# Generated by FakeRAM 2.0
VERSION 5.7 ;
BUSBITCHARS "[]" ;
PROPERTYDEFINITIONS
  MACRO width INTEGER ;
  MACRO depth INTEGER ;
  MACRO banks INTEGER ;
END PROPERTYDEFINITIONS
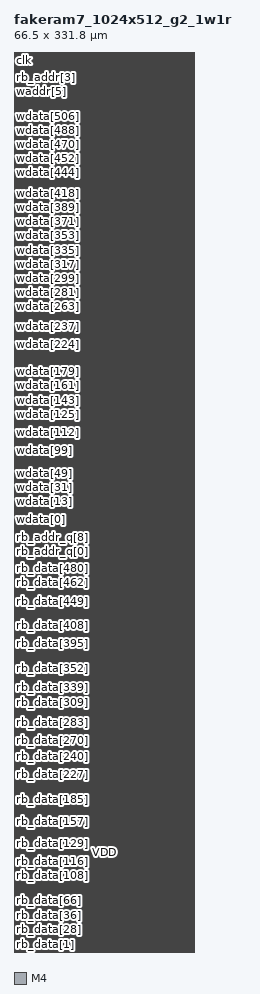
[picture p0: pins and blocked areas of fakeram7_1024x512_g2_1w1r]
MACRO fakeram7_1024x512_g2_1w1r
  PROPERTY width 512 ;
  PROPERTY depth 1024 ;
  PROPERTY banks 1 ;
  FOREIGN fakeram7_1024x512_g2_1w1r 0 0 ;
  SYMMETRY X Y R90 ;
  SIZE 66.5000 BY 331.8000 ;
  CLASS BLOCK ;
  PIN wdata[0]
    DIRECTION INPUT ;
    USE SIGNAL ;
    PORT
      LAYER M4 ;
      RECT 0.00000 159.36000 0.02400 159.38400 ;
    END
  END wdata[0]
  PIN wdata[1]
    DIRECTION INPUT ;
    USE SIGNAL ;
    PORT
      LAYER M4 ;
      RECT 0.00000 159.64800 0.02400 159.67200 ;
    END
  END wdata[1]
  PIN wdata[2]
    DIRECTION INPUT ;
    USE SIGNAL ;
    PORT
      LAYER M4 ;
      RECT 0.00000 159.93600 0.02400 159.96000 ;
    END
  END wdata[2]
  PIN wdata[3]
    DIRECTION INPUT ;
    USE SIGNAL ;
    PORT
      LAYER M4 ;
      RECT 0.00000 160.22400 0.02400 160.24800 ;
    END
  END wdata[3]
  PIN wdata[4]
    DIRECTION INPUT ;
    USE SIGNAL ;
    PORT
      LAYER M4 ;
      RECT 0.00000 160.51200 0.02400 160.53600 ;
    END
  END wdata[4]
  PIN wdata[5]
    DIRECTION INPUT ;
    USE SIGNAL ;
    PORT
      LAYER M4 ;
      RECT 0.00000 160.80000 0.02400 160.82400 ;
    END
  END wdata[5]
  PIN wdata[6]
    DIRECTION INPUT ;
    USE SIGNAL ;
    PORT
      LAYER M4 ;
      RECT 0.00000 161.08800 0.02400 161.11200 ;
    END
  END wdata[6]
  PIN wdata[7]
    DIRECTION INPUT ;
    USE SIGNAL ;
    PORT
      LAYER M4 ;
      RECT 0.00000 161.37600 0.02400 161.40000 ;
    END
  END wdata[7]
  PIN wdata[8]
    DIRECTION INPUT ;
    USE SIGNAL ;
    PORT
      LAYER M4 ;
      RECT 0.00000 161.66400 0.02400 161.68800 ;
    END
  END wdata[8]
  PIN wdata[9]
    DIRECTION INPUT ;
    USE SIGNAL ;
    PORT
      LAYER M4 ;
      RECT 0.00000 161.95200 0.02400 161.97600 ;
    END
  END wdata[9]
  PIN wdata[10]
    DIRECTION INPUT ;
    USE SIGNAL ;
    PORT
      LAYER M4 ;
      RECT 0.00000 162.24000 0.02400 162.26400 ;
    END
  END wdata[10]
  PIN wdata[11]
    DIRECTION INPUT ;
    USE SIGNAL ;
    PORT
      LAYER M4 ;
      RECT 0.00000 162.52800 0.02400 162.55200 ;
    END
  END wdata[11]
  PIN wdata[12]
    DIRECTION INPUT ;
    USE SIGNAL ;
    PORT
      LAYER M4 ;
      RECT 0.00000 162.81600 0.02400 162.84000 ;
    END
  END wdata[12]
  PIN wdata[13]
    DIRECTION INPUT ;
    USE SIGNAL ;
    PORT
      LAYER M4 ;
      RECT 0.00000 163.10400 0.02400 163.12800 ;
    END
  END wdata[13]
  PIN wdata[14]
    DIRECTION INPUT ;
    USE SIGNAL ;
    PORT
      LAYER M4 ;
      RECT 0.00000 163.39200 0.02400 163.41600 ;
    END
  END wdata[14]
  PIN wdata[15]
    DIRECTION INPUT ;
    USE SIGNAL ;
    PORT
      LAYER M4 ;
      RECT 0.00000 163.68000 0.02400 163.70400 ;
    END
  END wdata[15]
  PIN wdata[16]
    DIRECTION INPUT ;
    USE SIGNAL ;
    PORT
      LAYER M4 ;
      RECT 0.00000 163.96800 0.02400 163.99200 ;
    END
  END wdata[16]
  PIN wdata[17]
    DIRECTION INPUT ;
    USE SIGNAL ;
    PORT
      LAYER M4 ;
      RECT 0.00000 164.25600 0.02400 164.28000 ;
    END
  END wdata[17]
  PIN wdata[18]
    DIRECTION INPUT ;
    USE SIGNAL ;
    PORT
      LAYER M4 ;
      RECT 0.00000 164.54400 0.02400 164.56800 ;
    END
  END wdata[18]
  PIN wdata[19]
    DIRECTION INPUT ;
    USE SIGNAL ;
    PORT
      LAYER M4 ;
      RECT 0.00000 164.83200 0.02400 164.85600 ;
    END
  END wdata[19]
  PIN wdata[20]
    DIRECTION INPUT ;
    USE SIGNAL ;
    PORT
      LAYER M4 ;
      RECT 0.00000 165.12000 0.02400 165.14400 ;
    END
  END wdata[20]
  PIN wdata[21]
    DIRECTION INPUT ;
    USE SIGNAL ;
    PORT
      LAYER M4 ;
      RECT 0.00000 165.40800 0.02400 165.43200 ;
    END
  END wdata[21]
  PIN wdata[22]
    DIRECTION INPUT ;
    USE SIGNAL ;
    PORT
      LAYER M4 ;
      RECT 0.00000 165.69600 0.02400 165.72000 ;
    END
  END wdata[22]
  PIN wdata[23]
    DIRECTION INPUT ;
    USE SIGNAL ;
    PORT
      LAYER M4 ;
      RECT 0.00000 165.98400 0.02400 166.00800 ;
    END
  END wdata[23]
  PIN wdata[24]
    DIRECTION INPUT ;
    USE SIGNAL ;
    PORT
      LAYER M4 ;
      RECT 0.00000 166.27200 0.02400 166.29600 ;
    END
  END wdata[24]
  PIN wdata[25]
    DIRECTION INPUT ;
    USE SIGNAL ;
    PORT
      LAYER M4 ;
      RECT 0.00000 166.56000 0.02400 166.58400 ;
    END
  END wdata[25]
  PIN wdata[26]
    DIRECTION INPUT ;
    USE SIGNAL ;
    PORT
      LAYER M4 ;
      RECT 0.00000 166.84800 0.02400 166.87200 ;
    END
  END wdata[26]
  PIN wdata[27]
    DIRECTION INPUT ;
    USE SIGNAL ;
    PORT
      LAYER M4 ;
      RECT 0.00000 167.13600 0.02400 167.16000 ;
    END
  END wdata[27]
  PIN wdata[28]
    DIRECTION INPUT ;
    USE SIGNAL ;
    PORT
      LAYER M4 ;
      RECT 0.00000 167.42400 0.02400 167.44800 ;
    END
  END wdata[28]
  PIN wdata[29]
    DIRECTION INPUT ;
    USE SIGNAL ;
    PORT
      LAYER M4 ;
      RECT 0.00000 167.71200 0.02400 167.73600 ;
    END
  END wdata[29]
  PIN wdata[30]
    DIRECTION INPUT ;
    USE SIGNAL ;
    PORT
      LAYER M4 ;
      RECT 0.00000 168.00000 0.02400 168.02400 ;
    END
  END wdata[30]
  PIN wdata[31]
    DIRECTION INPUT ;
    USE SIGNAL ;
    PORT
      LAYER M4 ;
      RECT 0.00000 168.28800 0.02400 168.31200 ;
    END
  END wdata[31]
  PIN wdata[32]
    DIRECTION INPUT ;
    USE SIGNAL ;
    PORT
      LAYER M4 ;
      RECT 0.00000 168.57600 0.02400 168.60000 ;
    END
  END wdata[32]
  PIN wdata[33]
    DIRECTION INPUT ;
    USE SIGNAL ;
    PORT
      LAYER M4 ;
      RECT 0.00000 168.86400 0.02400 168.88800 ;
    END
  END wdata[33]
  PIN wdata[34]
    DIRECTION INPUT ;
    USE SIGNAL ;
    PORT
      LAYER M4 ;
      RECT 0.00000 169.15200 0.02400 169.17600 ;
    END
  END wdata[34]
  PIN wdata[35]
    DIRECTION INPUT ;
    USE SIGNAL ;
    PORT
      LAYER M4 ;
      RECT 0.00000 169.44000 0.02400 169.46400 ;
    END
  END wdata[35]
  PIN wdata[36]
    DIRECTION INPUT ;
    USE SIGNAL ;
    PORT
      LAYER M4 ;
      RECT 0.00000 169.72800 0.02400 169.75200 ;
    END
  END wdata[36]
  PIN wdata[37]
    DIRECTION INPUT ;
    USE SIGNAL ;
    PORT
      LAYER M4 ;
      RECT 0.00000 170.01600 0.02400 170.04000 ;
    END
  END wdata[37]
  PIN wdata[38]
    DIRECTION INPUT ;
    USE SIGNAL ;
    PORT
      LAYER M4 ;
      RECT 0.00000 170.30400 0.02400 170.32800 ;
    END
  END wdata[38]
  PIN wdata[39]
    DIRECTION INPUT ;
    USE SIGNAL ;
    PORT
      LAYER M4 ;
      RECT 0.00000 170.59200 0.02400 170.61600 ;
    END
  END wdata[39]
  PIN wdata[40]
    DIRECTION INPUT ;
    USE SIGNAL ;
    PORT
      LAYER M4 ;
      RECT 0.00000 170.88000 0.02400 170.90400 ;
    END
  END wdata[40]
  PIN wdata[41]
    DIRECTION INPUT ;
    USE SIGNAL ;
    PORT
      LAYER M4 ;
      RECT 0.00000 171.16800 0.02400 171.19200 ;
    END
  END wdata[41]
  PIN wdata[42]
    DIRECTION INPUT ;
    USE SIGNAL ;
    PORT
      LAYER M4 ;
      RECT 0.00000 171.45600 0.02400 171.48000 ;
    END
  END wdata[42]
  PIN wdata[43]
    DIRECTION INPUT ;
    USE SIGNAL ;
    PORT
      LAYER M4 ;
      RECT 0.00000 171.74400 0.02400 171.76800 ;
    END
  END wdata[43]
  PIN wdata[44]
    DIRECTION INPUT ;
    USE SIGNAL ;
    PORT
      LAYER M4 ;
      RECT 0.00000 172.03200 0.02400 172.05600 ;
    END
  END wdata[44]
  PIN wdata[45]
    DIRECTION INPUT ;
    USE SIGNAL ;
    PORT
      LAYER M4 ;
      RECT 0.00000 172.32000 0.02400 172.34400 ;
    END
  END wdata[45]
  PIN wdata[46]
    DIRECTION INPUT ;
    USE SIGNAL ;
    PORT
      LAYER M4 ;
      RECT 0.00000 172.60800 0.02400 172.63200 ;
    END
  END wdata[46]
  PIN wdata[47]
    DIRECTION INPUT ;
    USE SIGNAL ;
    PORT
      LAYER M4 ;
      RECT 0.00000 172.89600 0.02400 172.92000 ;
    END
  END wdata[47]
  PIN wdata[48]
    DIRECTION INPUT ;
    USE SIGNAL ;
    PORT
      LAYER M4 ;
      RECT 0.00000 173.18400 0.02400 173.20800 ;
    END
  END wdata[48]
  PIN wdata[49]
    DIRECTION INPUT ;
    USE SIGNAL ;
    PORT
      LAYER M4 ;
      RECT 0.00000 173.47200 0.02400 173.49600 ;
    END
  END wdata[49]
  PIN wdata[50]
    DIRECTION INPUT ;
    USE SIGNAL ;
    PORT
      LAYER M4 ;
      RECT 0.00000 173.76000 0.02400 173.78400 ;
    END
  END wdata[50]
  PIN wdata[51]
    DIRECTION INPUT ;
    USE SIGNAL ;
    PORT
      LAYER M4 ;
      RECT 0.00000 174.04800 0.02400 174.07200 ;
    END
  END wdata[51]
  PIN wdata[52]
    DIRECTION INPUT ;
    USE SIGNAL ;
    PORT
      LAYER M4 ;
      RECT 0.00000 174.33600 0.02400 174.36000 ;
    END
  END wdata[52]
  PIN wdata[53]
    DIRECTION INPUT ;
    USE SIGNAL ;
    PORT
      LAYER M4 ;
      RECT 0.00000 174.62400 0.02400 174.64800 ;
    END
  END wdata[53]
  PIN wdata[54]
    DIRECTION INPUT ;
    USE SIGNAL ;
    PORT
      LAYER M4 ;
      RECT 0.00000 174.91200 0.02400 174.93600 ;
    END
  END wdata[54]
  PIN wdata[55]
    DIRECTION INPUT ;
    USE SIGNAL ;
    PORT
      LAYER M4 ;
      RECT 0.00000 175.20000 0.02400 175.22400 ;
    END
  END wdata[55]
  PIN wdata[56]
    DIRECTION INPUT ;
    USE SIGNAL ;
    PORT
      LAYER M4 ;
      RECT 0.00000 175.48800 0.02400 175.51200 ;
    END
  END wdata[56]
  PIN wdata[57]
    DIRECTION INPUT ;
    USE SIGNAL ;
    PORT
      LAYER M4 ;
      RECT 0.00000 175.77600 0.02400 175.80000 ;
    END
  END wdata[57]
  PIN wdata[58]
    DIRECTION INPUT ;
    USE SIGNAL ;
    PORT
      LAYER M4 ;
      RECT 0.00000 176.06400 0.02400 176.08800 ;
    END
  END wdata[58]
  PIN wdata[59]
    DIRECTION INPUT ;
    USE SIGNAL ;
    PORT
      LAYER M4 ;
      RECT 0.00000 176.35200 0.02400 176.37600 ;
    END
  END wdata[59]
  PIN wdata[60]
    DIRECTION INPUT ;
    USE SIGNAL ;
    PORT
      LAYER M4 ;
      RECT 0.00000 176.64000 0.02400 176.66400 ;
    END
  END wdata[60]
  PIN wdata[61]
    DIRECTION INPUT ;
    USE SIGNAL ;
    PORT
      LAYER M4 ;
      RECT 0.00000 176.92800 0.02400 176.95200 ;
    END
  END wdata[61]
  PIN wdata[62]
    DIRECTION INPUT ;
    USE SIGNAL ;
    PORT
      LAYER M4 ;
      RECT 0.00000 177.21600 0.02400 177.24000 ;
    END
  END wdata[62]
  PIN wdata[63]
    DIRECTION INPUT ;
    USE SIGNAL ;
    PORT
      LAYER M4 ;
      RECT 0.00000 177.50400 0.02400 177.52800 ;
    END
  END wdata[63]
  PIN wdata[64]
    DIRECTION INPUT ;
    USE SIGNAL ;
    PORT
      LAYER M4 ;
      RECT 0.00000 177.79200 0.02400 177.81600 ;
    END
  END wdata[64]
  PIN wdata[65]
    DIRECTION INPUT ;
    USE SIGNAL ;
    PORT
      LAYER M4 ;
      RECT 0.00000 178.08000 0.02400 178.10400 ;
    END
  END wdata[65]
  PIN wdata[66]
    DIRECTION INPUT ;
    USE SIGNAL ;
    PORT
      LAYER M4 ;
      RECT 0.00000 178.36800 0.02400 178.39200 ;
    END
  END wdata[66]
  PIN wdata[67]
    DIRECTION INPUT ;
    USE SIGNAL ;
    PORT
      LAYER M4 ;
      RECT 0.00000 178.65600 0.02400 178.68000 ;
    END
  END wdata[67]
  PIN wdata[68]
    DIRECTION INPUT ;
    USE SIGNAL ;
    PORT
      LAYER M4 ;
      RECT 0.00000 178.94400 0.02400 178.96800 ;
    END
  END wdata[68]
  PIN wdata[69]
    DIRECTION INPUT ;
    USE SIGNAL ;
    PORT
      LAYER M4 ;
      RECT 0.00000 179.23200 0.02400 179.25600 ;
    END
  END wdata[69]
  PIN wdata[70]
    DIRECTION INPUT ;
    USE SIGNAL ;
    PORT
      LAYER M4 ;
      RECT 0.00000 179.52000 0.02400 179.54400 ;
    END
  END wdata[70]
  PIN wdata[71]
    DIRECTION INPUT ;
    USE SIGNAL ;
    PORT
      LAYER M4 ;
      RECT 0.00000 179.80800 0.02400 179.83200 ;
    END
  END wdata[71]
  PIN wdata[72]
    DIRECTION INPUT ;
    USE SIGNAL ;
    PORT
      LAYER M4 ;
      RECT 0.00000 180.09600 0.02400 180.12000 ;
    END
  END wdata[72]
  PIN wdata[73]
    DIRECTION INPUT ;
    USE SIGNAL ;
    PORT
      LAYER M4 ;
      RECT 0.00000 180.38400 0.02400 180.40800 ;
    END
  END wdata[73]
  PIN wdata[74]
    DIRECTION INPUT ;
    USE SIGNAL ;
    PORT
      LAYER M4 ;
      RECT 0.00000 180.67200 0.02400 180.69600 ;
    END
  END wdata[74]
  PIN wdata[75]
    DIRECTION INPUT ;
    USE SIGNAL ;
    PORT
      LAYER M4 ;
      RECT 0.00000 180.96000 0.02400 180.98400 ;
    END
  END wdata[75]
  PIN wdata[76]
    DIRECTION INPUT ;
    USE SIGNAL ;
    PORT
      LAYER M4 ;
      RECT 0.00000 181.24800 0.02400 181.27200 ;
    END
  END wdata[76]
  PIN wdata[77]
    DIRECTION INPUT ;
    USE SIGNAL ;
    PORT
      LAYER M4 ;
      RECT 0.00000 181.53600 0.02400 181.56000 ;
    END
  END wdata[77]
  PIN wdata[78]
    DIRECTION INPUT ;
    USE SIGNAL ;
    PORT
      LAYER M4 ;
      RECT 0.00000 181.82400 0.02400 181.84800 ;
    END
  END wdata[78]
  PIN wdata[79]
    DIRECTION INPUT ;
    USE SIGNAL ;
    PORT
      LAYER M4 ;
      RECT 0.00000 182.11200 0.02400 182.13600 ;
    END
  END wdata[79]
  PIN wdata[80]
    DIRECTION INPUT ;
    USE SIGNAL ;
    PORT
      LAYER M4 ;
      RECT 0.00000 182.40000 0.02400 182.42400 ;
    END
  END wdata[80]
  PIN wdata[81]
    DIRECTION INPUT ;
    USE SIGNAL ;
    PORT
      LAYER M4 ;
      RECT 0.00000 182.68800 0.02400 182.71200 ;
    END
  END wdata[81]
  PIN wdata[82]
    DIRECTION INPUT ;
    USE SIGNAL ;
    PORT
      LAYER M4 ;
      RECT 0.00000 182.97600 0.02400 183.00000 ;
    END
  END wdata[82]
  PIN wdata[83]
    DIRECTION INPUT ;
    USE SIGNAL ;
    PORT
      LAYER M4 ;
      RECT 0.00000 183.26400 0.02400 183.28800 ;
    END
  END wdata[83]
  PIN wdata[84]
    DIRECTION INPUT ;
    USE SIGNAL ;
    PORT
      LAYER M4 ;
      RECT 0.00000 183.55200 0.02400 183.57600 ;
    END
  END wdata[84]
  PIN wdata[85]
    DIRECTION INPUT ;
    USE SIGNAL ;
    PORT
      LAYER M4 ;
      RECT 0.00000 183.84000 0.02400 183.86400 ;
    END
  END wdata[85]
  PIN wdata[86]
    DIRECTION INPUT ;
    USE SIGNAL ;
    PORT
      LAYER M4 ;
      RECT 0.00000 184.12800 0.02400 184.15200 ;
    END
  END wdata[86]
  PIN wdata[87]
    DIRECTION INPUT ;
    USE SIGNAL ;
    PORT
      LAYER M4 ;
      RECT 0.00000 184.41600 0.02400 184.44000 ;
    END
  END wdata[87]
  PIN wdata[88]
    DIRECTION INPUT ;
    USE SIGNAL ;
    PORT
      LAYER M4 ;
      RECT 0.00000 184.70400 0.02400 184.72800 ;
    END
  END wdata[88]
  PIN wdata[89]
    DIRECTION INPUT ;
    USE SIGNAL ;
    PORT
      LAYER M4 ;
      RECT 0.00000 184.99200 0.02400 185.01600 ;
    END
  END wdata[89]
  PIN wdata[90]
    DIRECTION INPUT ;
    USE SIGNAL ;
    PORT
      LAYER M4 ;
      RECT 0.00000 185.28000 0.02400 185.30400 ;
    END
  END wdata[90]
  PIN wdata[91]
    DIRECTION INPUT ;
    USE SIGNAL ;
    PORT
      LAYER M4 ;
      RECT 0.00000 185.56800 0.02400 185.59200 ;
    END
  END wdata[91]
  PIN wdata[92]
    DIRECTION INPUT ;
    USE SIGNAL ;
    PORT
      LAYER M4 ;
      RECT 0.00000 185.85600 0.02400 185.88000 ;
    END
  END wdata[92]
  PIN wdata[93]
    DIRECTION INPUT ;
    USE SIGNAL ;
    PORT
      LAYER M4 ;
      RECT 0.00000 186.14400 0.02400 186.16800 ;
    END
  END wdata[93]
  PIN wdata[94]
    DIRECTION INPUT ;
    USE SIGNAL ;
    PORT
      LAYER M4 ;
      RECT 0.00000 186.43200 0.02400 186.45600 ;
    END
  END wdata[94]
  PIN wdata[95]
    DIRECTION INPUT ;
    USE SIGNAL ;
    PORT
      LAYER M4 ;
      RECT 0.00000 186.72000 0.02400 186.74400 ;
    END
  END wdata[95]
  PIN wdata[96]
    DIRECTION INPUT ;
    USE SIGNAL ;
    PORT
      LAYER M4 ;
      RECT 0.00000 187.00800 0.02400 187.03200 ;
    END
  END wdata[96]
  PIN wdata[97]
    DIRECTION INPUT ;
    USE SIGNAL ;
    PORT
      LAYER M4 ;
      RECT 0.00000 187.29600 0.02400 187.32000 ;
    END
  END wdata[97]
  PIN wdata[98]
    DIRECTION INPUT ;
    USE SIGNAL ;
    PORT
      LAYER M4 ;
      RECT 0.00000 187.58400 0.02400 187.60800 ;
    END
  END wdata[98]
  PIN wdata[99]
    DIRECTION INPUT ;
    USE SIGNAL ;
    PORT
      LAYER M4 ;
      RECT 0.00000 187.87200 0.02400 187.89600 ;
    END
  END wdata[99]
  PIN wdata[100]
    DIRECTION INPUT ;
    USE SIGNAL ;
    PORT
      LAYER M4 ;
      RECT 0.00000 188.16000 0.02400 188.18400 ;
    END
  END wdata[100]
  PIN wdata[101]
    DIRECTION INPUT ;
    USE SIGNAL ;
    PORT
      LAYER M4 ;
      RECT 0.00000 188.44800 0.02400 188.47200 ;
    END
  END wdata[101]
  PIN wdata[102]
    DIRECTION INPUT ;
    USE SIGNAL ;
    PORT
      LAYER M4 ;
      RECT 0.00000 188.73600 0.02400 188.76000 ;
    END
  END wdata[102]
  PIN wdata[103]
    DIRECTION INPUT ;
    USE SIGNAL ;
    PORT
      LAYER M4 ;
      RECT 0.00000 189.02400 0.02400 189.04800 ;
    END
  END wdata[103]
  PIN wdata[104]
    DIRECTION INPUT ;
    USE SIGNAL ;
    PORT
      LAYER M4 ;
      RECT 0.00000 189.31200 0.02400 189.33600 ;
    END
  END wdata[104]
  PIN wdata[105]
    DIRECTION INPUT ;
    USE SIGNAL ;
    PORT
      LAYER M4 ;
      RECT 0.00000 189.60000 0.02400 189.62400 ;
    END
  END wdata[105]
  PIN wdata[106]
    DIRECTION INPUT ;
    USE SIGNAL ;
    PORT
      LAYER M4 ;
      RECT 0.00000 189.88800 0.02400 189.91200 ;
    END
  END wdata[106]
  PIN wdata[107]
    DIRECTION INPUT ;
    USE SIGNAL ;
    PORT
      LAYER M4 ;
      RECT 0.00000 190.17600 0.02400 190.20000 ;
    END
  END wdata[107]
  PIN wdata[108]
    DIRECTION INPUT ;
    USE SIGNAL ;
    PORT
      LAYER M4 ;
      RECT 0.00000 190.46400 0.02400 190.48800 ;
    END
  END wdata[108]
  PIN wdata[109]
    DIRECTION INPUT ;
    USE SIGNAL ;
    PORT
      LAYER M4 ;
      RECT 0.00000 190.75200 0.02400 190.77600 ;
    END
  END wdata[109]
  PIN wdata[110]
    DIRECTION INPUT ;
    USE SIGNAL ;
    PORT
      LAYER M4 ;
      RECT 0.00000 191.04000 0.02400 191.06400 ;
    END
  END wdata[110]
  PIN wdata[111]
    DIRECTION INPUT ;
    USE SIGNAL ;
    PORT
      LAYER M4 ;
      RECT 0.00000 191.32800 0.02400 191.35200 ;
    END
  END wdata[111]
  PIN wdata[112]
    DIRECTION INPUT ;
    USE SIGNAL ;
    PORT
      LAYER M4 ;
      RECT 0.00000 191.61600 0.02400 191.64000 ;
    END
  END wdata[112]
  PIN wdata[113]
    DIRECTION INPUT ;
    USE SIGNAL ;
    PORT
      LAYER M4 ;
      RECT 0.00000 191.90400 0.02400 191.92800 ;
    END
  END wdata[113]
  PIN wdata[114]
    DIRECTION INPUT ;
    USE SIGNAL ;
    PORT
      LAYER M4 ;
      RECT 0.00000 192.19200 0.02400 192.21600 ;
    END
  END wdata[114]
  PIN wdata[115]
    DIRECTION INPUT ;
    USE SIGNAL ;
    PORT
      LAYER M4 ;
      RECT 0.00000 192.48000 0.02400 192.50400 ;
    END
  END wdata[115]
  PIN wdata[116]
    DIRECTION INPUT ;
    USE SIGNAL ;
    PORT
      LAYER M4 ;
      RECT 0.00000 192.76800 0.02400 192.79200 ;
    END
  END wdata[116]
  PIN wdata[117]
    DIRECTION INPUT ;
    USE SIGNAL ;
    PORT
      LAYER M4 ;
      RECT 0.00000 193.05600 0.02400 193.08000 ;
    END
  END wdata[117]
  PIN wdata[118]
    DIRECTION INPUT ;
    USE SIGNAL ;
    PORT
      LAYER M4 ;
      RECT 0.00000 193.34400 0.02400 193.36800 ;
    END
  END wdata[118]
  PIN wdata[119]
    DIRECTION INPUT ;
    USE SIGNAL ;
    PORT
      LAYER M4 ;
      RECT 0.00000 193.63200 0.02400 193.65600 ;
    END
  END wdata[119]
  PIN wdata[120]
    DIRECTION INPUT ;
    USE SIGNAL ;
    PORT
      LAYER M4 ;
      RECT 0.00000 193.92000 0.02400 193.94400 ;
    END
  END wdata[120]
  PIN wdata[121]
    DIRECTION INPUT ;
    USE SIGNAL ;
    PORT
      LAYER M4 ;
      RECT 0.00000 194.20800 0.02400 194.23200 ;
    END
  END wdata[121]
  PIN wdata[122]
    DIRECTION INPUT ;
    USE SIGNAL ;
    PORT
      LAYER M4 ;
      RECT 0.00000 194.49600 0.02400 194.52000 ;
    END
  END wdata[122]
  PIN wdata[123]
    DIRECTION INPUT ;
    USE SIGNAL ;
    PORT
      LAYER M4 ;
      RECT 0.00000 194.78400 0.02400 194.80800 ;
    END
  END wdata[123]
  PIN wdata[124]
    DIRECTION INPUT ;
    USE SIGNAL ;
    PORT
      LAYER M4 ;
      RECT 0.00000 195.07200 0.02400 195.09600 ;
    END
  END wdata[124]
  PIN wdata[125]
    DIRECTION INPUT ;
    USE SIGNAL ;
    PORT
      LAYER M4 ;
      RECT 0.00000 195.36000 0.02400 195.38400 ;
    END
  END wdata[125]
  PIN wdata[126]
    DIRECTION INPUT ;
    USE SIGNAL ;
    PORT
      LAYER M4 ;
      RECT 0.00000 195.64800 0.02400 195.67200 ;
    END
  END wdata[126]
  PIN wdata[127]
    DIRECTION INPUT ;
    USE SIGNAL ;
    PORT
      LAYER M4 ;
      RECT 0.00000 195.93600 0.02400 195.96000 ;
    END
  END wdata[127]
  PIN wdata[128]
    DIRECTION INPUT ;
    USE SIGNAL ;
    PORT
      LAYER M4 ;
      RECT 0.00000 196.22400 0.02400 196.24800 ;
    END
  END wdata[128]
  PIN wdata[129]
    DIRECTION INPUT ;
    USE SIGNAL ;
    PORT
      LAYER M4 ;
      RECT 0.00000 196.51200 0.02400 196.53600 ;
    END
  END wdata[129]
  PIN wdata[130]
    DIRECTION INPUT ;
    USE SIGNAL ;
    PORT
      LAYER M4 ;
      RECT 0.00000 196.80000 0.02400 196.82400 ;
    END
  END wdata[130]
  PIN wdata[131]
    DIRECTION INPUT ;
    USE SIGNAL ;
    PORT
      LAYER M4 ;
      RECT 0.00000 197.08800 0.02400 197.11200 ;
    END
  END wdata[131]
  PIN wdata[132]
    DIRECTION INPUT ;
    USE SIGNAL ;
    PORT
      LAYER M4 ;
      RECT 0.00000 197.37600 0.02400 197.40000 ;
    END
  END wdata[132]
  PIN wdata[133]
    DIRECTION INPUT ;
    USE SIGNAL ;
    PORT
      LAYER M4 ;
      RECT 0.00000 197.66400 0.02400 197.68800 ;
    END
  END wdata[133]
  PIN wdata[134]
    DIRECTION INPUT ;
    USE SIGNAL ;
    PORT
      LAYER M4 ;
      RECT 0.00000 197.95200 0.02400 197.97600 ;
    END
  END wdata[134]
  PIN wdata[135]
    DIRECTION INPUT ;
    USE SIGNAL ;
    PORT
      LAYER M4 ;
      RECT 0.00000 198.24000 0.02400 198.26400 ;
    END
  END wdata[135]
  PIN wdata[136]
    DIRECTION INPUT ;
    USE SIGNAL ;
    PORT
      LAYER M4 ;
      RECT 0.00000 198.52800 0.02400 198.55200 ;
    END
  END wdata[136]
  PIN wdata[137]
    DIRECTION INPUT ;
    USE SIGNAL ;
    PORT
      LAYER M4 ;
      RECT 0.00000 198.81600 0.02400 198.84000 ;
    END
  END wdata[137]
  PIN wdata[138]
    DIRECTION INPUT ;
    USE SIGNAL ;
    PORT
      LAYER M4 ;
      RECT 0.00000 199.10400 0.02400 199.12800 ;
    END
  END wdata[138]
  PIN wdata[139]
    DIRECTION INPUT ;
    USE SIGNAL ;
    PORT
      LAYER M4 ;
      RECT 0.00000 199.39200 0.02400 199.41600 ;
    END
  END wdata[139]
  PIN wdata[140]
    DIRECTION INPUT ;
    USE SIGNAL ;
    PORT
      LAYER M4 ;
      RECT 0.00000 199.68000 0.02400 199.70400 ;
    END
  END wdata[140]
  PIN wdata[141]
    DIRECTION INPUT ;
    USE SIGNAL ;
    PORT
      LAYER M4 ;
      RECT 0.00000 199.96800 0.02400 199.99200 ;
    END
  END wdata[141]
  PIN wdata[142]
    DIRECTION INPUT ;
    USE SIGNAL ;
    PORT
      LAYER M4 ;
      RECT 0.00000 200.25600 0.02400 200.28000 ;
    END
  END wdata[142]
  PIN wdata[143]
    DIRECTION INPUT ;
    USE SIGNAL ;
    PORT
      LAYER M4 ;
      RECT 0.00000 200.54400 0.02400 200.56800 ;
    END
  END wdata[143]
  PIN wdata[144]
    DIRECTION INPUT ;
    USE SIGNAL ;
    PORT
      LAYER M4 ;
      RECT 0.00000 200.83200 0.02400 200.85600 ;
    END
  END wdata[144]
  PIN wdata[145]
    DIRECTION INPUT ;
    USE SIGNAL ;
    PORT
      LAYER M4 ;
      RECT 0.00000 201.12000 0.02400 201.14400 ;
    END
  END wdata[145]
  PIN wdata[146]
    DIRECTION INPUT ;
    USE SIGNAL ;
    PORT
      LAYER M4 ;
      RECT 0.00000 201.40800 0.02400 201.43200 ;
    END
  END wdata[146]
  PIN wdata[147]
    DIRECTION INPUT ;
    USE SIGNAL ;
    PORT
      LAYER M4 ;
      RECT 0.00000 201.69600 0.02400 201.72000 ;
    END
  END wdata[147]
  PIN wdata[148]
    DIRECTION INPUT ;
    USE SIGNAL ;
    PORT
      LAYER M4 ;
      RECT 0.00000 201.98400 0.02400 202.00800 ;
    END
  END wdata[148]
  PIN wdata[149]
    DIRECTION INPUT ;
    USE SIGNAL ;
    PORT
      LAYER M4 ;
      RECT 0.00000 202.27200 0.02400 202.29600 ;
    END
  END wdata[149]
  PIN wdata[150]
    DIRECTION INPUT ;
    USE SIGNAL ;
    PORT
      LAYER M4 ;
      RECT 0.00000 202.56000 0.02400 202.58400 ;
    END
  END wdata[150]
  PIN wdata[151]
    DIRECTION INPUT ;
    USE SIGNAL ;
    PORT
      LAYER M4 ;
      RECT 0.00000 202.84800 0.02400 202.87200 ;
    END
  END wdata[151]
  PIN wdata[152]
    DIRECTION INPUT ;
    USE SIGNAL ;
    PORT
      LAYER M4 ;
      RECT 0.00000 203.13600 0.02400 203.16000 ;
    END
  END wdata[152]
  PIN wdata[153]
    DIRECTION INPUT ;
    USE SIGNAL ;
    PORT
      LAYER M4 ;
      RECT 0.00000 203.42400 0.02400 203.44800 ;
    END
  END wdata[153]
  PIN wdata[154]
    DIRECTION INPUT ;
    USE SIGNAL ;
    PORT
      LAYER M4 ;
      RECT 0.00000 203.71200 0.02400 203.73600 ;
    END
  END wdata[154]
  PIN wdata[155]
    DIRECTION INPUT ;
    USE SIGNAL ;
    PORT
      LAYER M4 ;
      RECT 0.00000 204.00000 0.02400 204.02400 ;
    END
  END wdata[155]
  PIN wdata[156]
    DIRECTION INPUT ;
    USE SIGNAL ;
    PORT
      LAYER M4 ;
      RECT 0.00000 204.28800 0.02400 204.31200 ;
    END
  END wdata[156]
  PIN wdata[157]
    DIRECTION INPUT ;
    USE SIGNAL ;
    PORT
      LAYER M4 ;
      RECT 0.00000 204.57600 0.02400 204.60000 ;
    END
  END wdata[157]
  PIN wdata[158]
    DIRECTION INPUT ;
    USE SIGNAL ;
    PORT
      LAYER M4 ;
      RECT 0.00000 204.86400 0.02400 204.88800 ;
    END
  END wdata[158]
  PIN wdata[159]
    DIRECTION INPUT ;
    USE SIGNAL ;
    PORT
      LAYER M4 ;
      RECT 0.00000 205.15200 0.02400 205.17600 ;
    END
  END wdata[159]
  PIN wdata[160]
    DIRECTION INPUT ;
    USE SIGNAL ;
    PORT
      LAYER M4 ;
      RECT 0.00000 205.44000 0.02400 205.46400 ;
    END
  END wdata[160]
  PIN wdata[161]
    DIRECTION INPUT ;
    USE SIGNAL ;
    PORT
      LAYER M4 ;
      RECT 0.00000 205.72800 0.02400 205.75200 ;
    END
  END wdata[161]
  PIN wdata[162]
    DIRECTION INPUT ;
    USE SIGNAL ;
    PORT
      LAYER M4 ;
      RECT 0.00000 206.01600 0.02400 206.04000 ;
    END
  END wdata[162]
  PIN wdata[163]
    DIRECTION INPUT ;
    USE SIGNAL ;
    PORT
      LAYER M4 ;
      RECT 0.00000 206.30400 0.02400 206.32800 ;
    END
  END wdata[163]
  PIN wdata[164]
    DIRECTION INPUT ;
    USE SIGNAL ;
    PORT
      LAYER M4 ;
      RECT 0.00000 206.59200 0.02400 206.61600 ;
    END
  END wdata[164]
  PIN wdata[165]
    DIRECTION INPUT ;
    USE SIGNAL ;
    PORT
      LAYER M4 ;
      RECT 0.00000 206.88000 0.02400 206.90400 ;
    END
  END wdata[165]
  PIN wdata[166]
    DIRECTION INPUT ;
    USE SIGNAL ;
    PORT
      LAYER M4 ;
      RECT 0.00000 207.16800 0.02400 207.19200 ;
    END
  END wdata[166]
  PIN wdata[167]
    DIRECTION INPUT ;
    USE SIGNAL ;
    PORT
      LAYER M4 ;
      RECT 0.00000 207.45600 0.02400 207.48000 ;
    END
  END wdata[167]
  PIN wdata[168]
    DIRECTION INPUT ;
    USE SIGNAL ;
    PORT
      LAYER M4 ;
      RECT 0.00000 207.74400 0.02400 207.76800 ;
    END
  END wdata[168]
  PIN wdata[169]
    DIRECTION INPUT ;
    USE SIGNAL ;
    PORT
      LAYER M4 ;
      RECT 0.00000 208.03200 0.02400 208.05600 ;
    END
  END wdata[169]
  PIN wdata[170]
    DIRECTION INPUT ;
    USE SIGNAL ;
    PORT
      LAYER M4 ;
      RECT 0.00000 208.32000 0.02400 208.34400 ;
    END
  END wdata[170]
  PIN wdata[171]
    DIRECTION INPUT ;
    USE SIGNAL ;
    PORT
      LAYER M4 ;
      RECT 0.00000 208.60800 0.02400 208.63200 ;
    END
  END wdata[171]
  PIN wdata[172]
    DIRECTION INPUT ;
    USE SIGNAL ;
    PORT
      LAYER M4 ;
      RECT 0.00000 208.89600 0.02400 208.92000 ;
    END
  END wdata[172]
  PIN wdata[173]
    DIRECTION INPUT ;
    USE SIGNAL ;
    PORT
      LAYER M4 ;
      RECT 0.00000 209.18400 0.02400 209.20800 ;
    END
  END wdata[173]
  PIN wdata[174]
    DIRECTION INPUT ;
    USE SIGNAL ;
    PORT
      LAYER M4 ;
      RECT 0.00000 209.47200 0.02400 209.49600 ;
    END
  END wdata[174]
  PIN wdata[175]
    DIRECTION INPUT ;
    USE SIGNAL ;
    PORT
      LAYER M4 ;
      RECT 0.00000 209.76000 0.02400 209.78400 ;
    END
  END wdata[175]
  PIN wdata[176]
    DIRECTION INPUT ;
    USE SIGNAL ;
    PORT
      LAYER M4 ;
      RECT 0.00000 210.04800 0.02400 210.07200 ;
    END
  END wdata[176]
  PIN wdata[177]
    DIRECTION INPUT ;
    USE SIGNAL ;
    PORT
      LAYER M4 ;
      RECT 0.00000 210.33600 0.02400 210.36000 ;
    END
  END wdata[177]
  PIN wdata[178]
    DIRECTION INPUT ;
    USE SIGNAL ;
    PORT
      LAYER M4 ;
      RECT 0.00000 210.62400 0.02400 210.64800 ;
    END
  END wdata[178]
  PIN wdata[179]
    DIRECTION INPUT ;
    USE SIGNAL ;
    PORT
      LAYER M4 ;
      RECT 0.00000 210.91200 0.02400 210.93600 ;
    END
  END wdata[179]
  PIN wdata[180]
    DIRECTION INPUT ;
    USE SIGNAL ;
    PORT
      LAYER M4 ;
      RECT 0.00000 211.20000 0.02400 211.22400 ;
    END
  END wdata[180]
  PIN wdata[181]
    DIRECTION INPUT ;
    USE SIGNAL ;
    PORT
      LAYER M4 ;
      RECT 0.00000 211.48800 0.02400 211.51200 ;
    END
  END wdata[181]
  PIN wdata[182]
    DIRECTION INPUT ;
    USE SIGNAL ;
    PORT
      LAYER M4 ;
      RECT 0.00000 211.77600 0.02400 211.80000 ;
    END
  END wdata[182]
  PIN wdata[183]
    DIRECTION INPUT ;
    USE SIGNAL ;
    PORT
      LAYER M4 ;
      RECT 0.00000 212.06400 0.02400 212.08800 ;
    END
  END wdata[183]
  PIN wdata[184]
    DIRECTION INPUT ;
    USE SIGNAL ;
    PORT
      LAYER M4 ;
      RECT 0.00000 212.35200 0.02400 212.37600 ;
    END
  END wdata[184]
  PIN wdata[185]
    DIRECTION INPUT ;
    USE SIGNAL ;
    PORT
      LAYER M4 ;
      RECT 0.00000 212.64000 0.02400 212.66400 ;
    END
  END wdata[185]
  PIN wdata[186]
    DIRECTION INPUT ;
    USE SIGNAL ;
    PORT
      LAYER M4 ;
      RECT 0.00000 212.92800 0.02400 212.95200 ;
    END
  END wdata[186]
  PIN wdata[187]
    DIRECTION INPUT ;
    USE SIGNAL ;
    PORT
      LAYER M4 ;
      RECT 0.00000 213.21600 0.02400 213.24000 ;
    END
  END wdata[187]
  PIN wdata[188]
    DIRECTION INPUT ;
    USE SIGNAL ;
    PORT
      LAYER M4 ;
      RECT 0.00000 213.50400 0.02400 213.52800 ;
    END
  END wdata[188]
  PIN wdata[189]
    DIRECTION INPUT ;
    USE SIGNAL ;
    PORT
      LAYER M4 ;
      RECT 0.00000 213.79200 0.02400 213.81600 ;
    END
  END wdata[189]
  PIN wdata[190]
    DIRECTION INPUT ;
    USE SIGNAL ;
    PORT
      LAYER M4 ;
      RECT 0.00000 214.08000 0.02400 214.10400 ;
    END
  END wdata[190]
  PIN wdata[191]
    DIRECTION INPUT ;
    USE SIGNAL ;
    PORT
      LAYER M4 ;
      RECT 0.00000 214.36800 0.02400 214.39200 ;
    END
  END wdata[191]
  PIN wdata[192]
    DIRECTION INPUT ;
    USE SIGNAL ;
    PORT
      LAYER M4 ;
      RECT 0.00000 214.65600 0.02400 214.68000 ;
    END
  END wdata[192]
  PIN wdata[193]
    DIRECTION INPUT ;
    USE SIGNAL ;
    PORT
      LAYER M4 ;
      RECT 0.00000 214.94400 0.02400 214.96800 ;
    END
  END wdata[193]
  PIN wdata[194]
    DIRECTION INPUT ;
    USE SIGNAL ;
    PORT
      LAYER M4 ;
      RECT 0.00000 215.23200 0.02400 215.25600 ;
    END
  END wdata[194]
  PIN wdata[195]
    DIRECTION INPUT ;
    USE SIGNAL ;
    PORT
      LAYER M4 ;
      RECT 0.00000 215.52000 0.02400 215.54400 ;
    END
  END wdata[195]
  PIN wdata[196]
    DIRECTION INPUT ;
    USE SIGNAL ;
    PORT
      LAYER M4 ;
      RECT 0.00000 215.80800 0.02400 215.83200 ;
    END
  END wdata[196]
  PIN wdata[197]
    DIRECTION INPUT ;
    USE SIGNAL ;
    PORT
      LAYER M4 ;
      RECT 0.00000 216.09600 0.02400 216.12000 ;
    END
  END wdata[197]
  PIN wdata[198]
    DIRECTION INPUT ;
    USE SIGNAL ;
    PORT
      LAYER M4 ;
      RECT 0.00000 216.38400 0.02400 216.40800 ;
    END
  END wdata[198]
  PIN wdata[199]
    DIRECTION INPUT ;
    USE SIGNAL ;
    PORT
      LAYER M4 ;
      RECT 0.00000 216.67200 0.02400 216.69600 ;
    END
  END wdata[199]
  PIN wdata[200]
    DIRECTION INPUT ;
    USE SIGNAL ;
    PORT
      LAYER M4 ;
      RECT 0.00000 216.96000 0.02400 216.98400 ;
    END
  END wdata[200]
  PIN wdata[201]
    DIRECTION INPUT ;
    USE SIGNAL ;
    PORT
      LAYER M4 ;
      RECT 0.00000 217.24800 0.02400 217.27200 ;
    END
  END wdata[201]
  PIN wdata[202]
    DIRECTION INPUT ;
    USE SIGNAL ;
    PORT
      LAYER M4 ;
      RECT 0.00000 217.53600 0.02400 217.56000 ;
    END
  END wdata[202]
  PIN wdata[203]
    DIRECTION INPUT ;
    USE SIGNAL ;
    PORT
      LAYER M4 ;
      RECT 0.00000 217.82400 0.02400 217.84800 ;
    END
  END wdata[203]
  PIN wdata[204]
    DIRECTION INPUT ;
    USE SIGNAL ;
    PORT
      LAYER M4 ;
      RECT 0.00000 218.11200 0.02400 218.13600 ;
    END
  END wdata[204]
  PIN wdata[205]
    DIRECTION INPUT ;
    USE SIGNAL ;
    PORT
      LAYER M4 ;
      RECT 0.00000 218.40000 0.02400 218.42400 ;
    END
  END wdata[205]
  PIN wdata[206]
    DIRECTION INPUT ;
    USE SIGNAL ;
    PORT
      LAYER M4 ;
      RECT 0.00000 218.68800 0.02400 218.71200 ;
    END
  END wdata[206]
  PIN wdata[207]
    DIRECTION INPUT ;
    USE SIGNAL ;
    PORT
      LAYER M4 ;
      RECT 0.00000 218.97600 0.02400 219.00000 ;
    END
  END wdata[207]
  PIN wdata[208]
    DIRECTION INPUT ;
    USE SIGNAL ;
    PORT
      LAYER M4 ;
      RECT 0.00000 219.26400 0.02400 219.28800 ;
    END
  END wdata[208]
  PIN wdata[209]
    DIRECTION INPUT ;
    USE SIGNAL ;
    PORT
      LAYER M4 ;
      RECT 0.00000 219.55200 0.02400 219.57600 ;
    END
  END wdata[209]
  PIN wdata[210]
    DIRECTION INPUT ;
    USE SIGNAL ;
    PORT
      LAYER M4 ;
      RECT 0.00000 219.84000 0.02400 219.86400 ;
    END
  END wdata[210]
  PIN wdata[211]
    DIRECTION INPUT ;
    USE SIGNAL ;
    PORT
      LAYER M4 ;
      RECT 0.00000 220.12800 0.02400 220.15200 ;
    END
  END wdata[211]
  PIN wdata[212]
    DIRECTION INPUT ;
    USE SIGNAL ;
    PORT
      LAYER M4 ;
      RECT 0.00000 220.41600 0.02400 220.44000 ;
    END
  END wdata[212]
  PIN wdata[213]
    DIRECTION INPUT ;
    USE SIGNAL ;
    PORT
      LAYER M4 ;
      RECT 0.00000 220.70400 0.02400 220.72800 ;
    END
  END wdata[213]
  PIN wdata[214]
    DIRECTION INPUT ;
    USE SIGNAL ;
    PORT
      LAYER M4 ;
      RECT 0.00000 220.99200 0.02400 221.01600 ;
    END
  END wdata[214]
  PIN wdata[215]
    DIRECTION INPUT ;
    USE SIGNAL ;
    PORT
      LAYER M4 ;
      RECT 0.00000 221.28000 0.02400 221.30400 ;
    END
  END wdata[215]
  PIN wdata[216]
    DIRECTION INPUT ;
    USE SIGNAL ;
    PORT
      LAYER M4 ;
      RECT 0.00000 221.56800 0.02400 221.59200 ;
    END
  END wdata[216]
  PIN wdata[217]
    DIRECTION INPUT ;
    USE SIGNAL ;
    PORT
      LAYER M4 ;
      RECT 0.00000 221.85600 0.02400 221.88000 ;
    END
  END wdata[217]
  PIN wdata[218]
    DIRECTION INPUT ;
    USE SIGNAL ;
    PORT
      LAYER M4 ;
      RECT 0.00000 222.14400 0.02400 222.16800 ;
    END
  END wdata[218]
  PIN wdata[219]
    DIRECTION INPUT ;
    USE SIGNAL ;
    PORT
      LAYER M4 ;
      RECT 0.00000 222.43200 0.02400 222.45600 ;
    END
  END wdata[219]
  PIN wdata[220]
    DIRECTION INPUT ;
    USE SIGNAL ;
    PORT
      LAYER M4 ;
      RECT 0.00000 222.72000 0.02400 222.74400 ;
    END
  END wdata[220]
  PIN wdata[221]
    DIRECTION INPUT ;
    USE SIGNAL ;
    PORT
      LAYER M4 ;
      RECT 0.00000 223.00800 0.02400 223.03200 ;
    END
  END wdata[221]
  PIN wdata[222]
    DIRECTION INPUT ;
    USE SIGNAL ;
    PORT
      LAYER M4 ;
      RECT 0.00000 223.29600 0.02400 223.32000 ;
    END
  END wdata[222]
  PIN wdata[223]
    DIRECTION INPUT ;
    USE SIGNAL ;
    PORT
      LAYER M4 ;
      RECT 0.00000 223.58400 0.02400 223.60800 ;
    END
  END wdata[223]
  PIN wdata[224]
    DIRECTION INPUT ;
    USE SIGNAL ;
    PORT
      LAYER M4 ;
      RECT 0.00000 223.87200 0.02400 223.89600 ;
    END
  END wdata[224]
  PIN wdata[225]
    DIRECTION INPUT ;
    USE SIGNAL ;
    PORT
      LAYER M4 ;
      RECT 0.00000 224.16000 0.02400 224.18400 ;
    END
  END wdata[225]
  PIN wdata[226]
    DIRECTION INPUT ;
    USE SIGNAL ;
    PORT
      LAYER M4 ;
      RECT 0.00000 224.44800 0.02400 224.47200 ;
    END
  END wdata[226]
  PIN wdata[227]
    DIRECTION INPUT ;
    USE SIGNAL ;
    PORT
      LAYER M4 ;
      RECT 0.00000 224.73600 0.02400 224.76000 ;
    END
  END wdata[227]
  PIN wdata[228]
    DIRECTION INPUT ;
    USE SIGNAL ;
    PORT
      LAYER M4 ;
      RECT 0.00000 225.02400 0.02400 225.04800 ;
    END
  END wdata[228]
  PIN wdata[229]
    DIRECTION INPUT ;
    USE SIGNAL ;
    PORT
      LAYER M4 ;
      RECT 0.00000 225.31200 0.02400 225.33600 ;
    END
  END wdata[229]
  PIN wdata[230]
    DIRECTION INPUT ;
    USE SIGNAL ;
    PORT
      LAYER M4 ;
      RECT 0.00000 225.60000 0.02400 225.62400 ;
    END
  END wdata[230]
  PIN wdata[231]
    DIRECTION INPUT ;
    USE SIGNAL ;
    PORT
      LAYER M4 ;
      RECT 0.00000 225.88800 0.02400 225.91200 ;
    END
  END wdata[231]
  PIN wdata[232]
    DIRECTION INPUT ;
    USE SIGNAL ;
    PORT
      LAYER M4 ;
      RECT 0.00000 226.17600 0.02400 226.20000 ;
    END
  END wdata[232]
  PIN wdata[233]
    DIRECTION INPUT ;
    USE SIGNAL ;
    PORT
      LAYER M4 ;
      RECT 0.00000 226.46400 0.02400 226.48800 ;
    END
  END wdata[233]
  PIN wdata[234]
    DIRECTION INPUT ;
    USE SIGNAL ;
    PORT
      LAYER M4 ;
      RECT 0.00000 226.75200 0.02400 226.77600 ;
    END
  END wdata[234]
  PIN wdata[235]
    DIRECTION INPUT ;
    USE SIGNAL ;
    PORT
      LAYER M4 ;
      RECT 0.00000 227.04000 0.02400 227.06400 ;
    END
  END wdata[235]
  PIN wdata[236]
    DIRECTION INPUT ;
    USE SIGNAL ;
    PORT
      LAYER M4 ;
      RECT 0.00000 227.32800 0.02400 227.35200 ;
    END
  END wdata[236]
  PIN wdata[237]
    DIRECTION INPUT ;
    USE SIGNAL ;
    PORT
      LAYER M4 ;
      RECT 0.00000 227.61600 0.02400 227.64000 ;
    END
  END wdata[237]
  PIN wdata[238]
    DIRECTION INPUT ;
    USE SIGNAL ;
    PORT
      LAYER M4 ;
      RECT 0.00000 227.90400 0.02400 227.92800 ;
    END
  END wdata[238]
  PIN wdata[239]
    DIRECTION INPUT ;
    USE SIGNAL ;
    PORT
      LAYER M4 ;
      RECT 0.00000 228.19200 0.02400 228.21600 ;
    END
  END wdata[239]
  PIN wdata[240]
    DIRECTION INPUT ;
    USE SIGNAL ;
    PORT
      LAYER M4 ;
      RECT 0.00000 228.48000 0.02400 228.50400 ;
    END
  END wdata[240]
  PIN wdata[241]
    DIRECTION INPUT ;
    USE SIGNAL ;
    PORT
      LAYER M4 ;
      RECT 0.00000 228.76800 0.02400 228.79200 ;
    END
  END wdata[241]
  PIN wdata[242]
    DIRECTION INPUT ;
    USE SIGNAL ;
    PORT
      LAYER M4 ;
      RECT 0.00000 229.05600 0.02400 229.08000 ;
    END
  END wdata[242]
  PIN wdata[243]
    DIRECTION INPUT ;
    USE SIGNAL ;
    PORT
      LAYER M4 ;
      RECT 0.00000 229.34400 0.02400 229.36800 ;
    END
  END wdata[243]
  PIN wdata[244]
    DIRECTION INPUT ;
    USE SIGNAL ;
    PORT
      LAYER M4 ;
      RECT 0.00000 229.63200 0.02400 229.65600 ;
    END
  END wdata[244]
  PIN wdata[245]
    DIRECTION INPUT ;
    USE SIGNAL ;
    PORT
      LAYER M4 ;
      RECT 0.00000 229.92000 0.02400 229.94400 ;
    END
  END wdata[245]
  PIN wdata[246]
    DIRECTION INPUT ;
    USE SIGNAL ;
    PORT
      LAYER M4 ;
      RECT 0.00000 230.20800 0.02400 230.23200 ;
    END
  END wdata[246]
  PIN wdata[247]
    DIRECTION INPUT ;
    USE SIGNAL ;
    PORT
      LAYER M4 ;
      RECT 0.00000 230.49600 0.02400 230.52000 ;
    END
  END wdata[247]
  PIN wdata[248]
    DIRECTION INPUT ;
    USE SIGNAL ;
    PORT
      LAYER M4 ;
      RECT 0.00000 230.78400 0.02400 230.80800 ;
    END
  END wdata[248]
  PIN wdata[249]
    DIRECTION INPUT ;
    USE SIGNAL ;
    PORT
      LAYER M4 ;
      RECT 0.00000 231.07200 0.02400 231.09600 ;
    END
  END wdata[249]
  PIN wdata[250]
    DIRECTION INPUT ;
    USE SIGNAL ;
    PORT
      LAYER M4 ;
      RECT 0.00000 231.36000 0.02400 231.38400 ;
    END
  END wdata[250]
  PIN wdata[251]
    DIRECTION INPUT ;
    USE SIGNAL ;
    PORT
      LAYER M4 ;
      RECT 0.00000 231.64800 0.02400 231.67200 ;
    END
  END wdata[251]
  PIN wdata[252]
    DIRECTION INPUT ;
    USE SIGNAL ;
    PORT
      LAYER M4 ;
      RECT 0.00000 231.93600 0.02400 231.96000 ;
    END
  END wdata[252]
  PIN wdata[253]
    DIRECTION INPUT ;
    USE SIGNAL ;
    PORT
      LAYER M4 ;
      RECT 0.00000 232.22400 0.02400 232.24800 ;
    END
  END wdata[253]
  PIN wdata[254]
    DIRECTION INPUT ;
    USE SIGNAL ;
    PORT
      LAYER M4 ;
      RECT 0.00000 232.51200 0.02400 232.53600 ;
    END
  END wdata[254]
  PIN wdata[255]
    DIRECTION INPUT ;
    USE SIGNAL ;
    PORT
      LAYER M4 ;
      RECT 0.00000 232.80000 0.02400 232.82400 ;
    END
  END wdata[255]
  PIN wdata[256]
    DIRECTION INPUT ;
    USE SIGNAL ;
    PORT
      LAYER M4 ;
      RECT 0.00000 233.08800 0.02400 233.11200 ;
    END
  END wdata[256]
  PIN wdata[257]
    DIRECTION INPUT ;
    USE SIGNAL ;
    PORT
      LAYER M4 ;
      RECT 0.00000 233.37600 0.02400 233.40000 ;
    END
  END wdata[257]
  PIN wdata[258]
    DIRECTION INPUT ;
    USE SIGNAL ;
    PORT
      LAYER M4 ;
      RECT 0.00000 233.66400 0.02400 233.68800 ;
    END
  END wdata[258]
  PIN wdata[259]
    DIRECTION INPUT ;
    USE SIGNAL ;
    PORT
      LAYER M4 ;
      RECT 0.00000 233.95200 0.02400 233.97600 ;
    END
  END wdata[259]
  PIN wdata[260]
    DIRECTION INPUT ;
    USE SIGNAL ;
    PORT
      LAYER M4 ;
      RECT 0.00000 234.24000 0.02400 234.26400 ;
    END
  END wdata[260]
  PIN wdata[261]
    DIRECTION INPUT ;
    USE SIGNAL ;
    PORT
      LAYER M4 ;
      RECT 0.00000 234.52800 0.02400 234.55200 ;
    END
  END wdata[261]
  PIN wdata[262]
    DIRECTION INPUT ;
    USE SIGNAL ;
    PORT
      LAYER M4 ;
      RECT 0.00000 234.81600 0.02400 234.84000 ;
    END
  END wdata[262]
  PIN wdata[263]
    DIRECTION INPUT ;
    USE SIGNAL ;
    PORT
      LAYER M4 ;
      RECT 0.00000 235.10400 0.02400 235.12800 ;
    END
  END wdata[263]
  PIN wdata[264]
    DIRECTION INPUT ;
    USE SIGNAL ;
    PORT
      LAYER M4 ;
      RECT 0.00000 235.39200 0.02400 235.41600 ;
    END
  END wdata[264]
  PIN wdata[265]
    DIRECTION INPUT ;
    USE SIGNAL ;
    PORT
      LAYER M4 ;
      RECT 0.00000 235.68000 0.02400 235.70400 ;
    END
  END wdata[265]
  PIN wdata[266]
    DIRECTION INPUT ;
    USE SIGNAL ;
    PORT
      LAYER M4 ;
      RECT 0.00000 235.96800 0.02400 235.99200 ;
    END
  END wdata[266]
  PIN wdata[267]
    DIRECTION INPUT ;
    USE SIGNAL ;
    PORT
      LAYER M4 ;
      RECT 0.00000 236.25600 0.02400 236.28000 ;
    END
  END wdata[267]
  PIN wdata[268]
    DIRECTION INPUT ;
    USE SIGNAL ;
    PORT
      LAYER M4 ;
      RECT 0.00000 236.54400 0.02400 236.56800 ;
    END
  END wdata[268]
  PIN wdata[269]
    DIRECTION INPUT ;
    USE SIGNAL ;
    PORT
      LAYER M4 ;
      RECT 0.00000 236.83200 0.02400 236.85600 ;
    END
  END wdata[269]
  PIN wdata[270]
    DIRECTION INPUT ;
    USE SIGNAL ;
    PORT
      LAYER M4 ;
      RECT 0.00000 237.12000 0.02400 237.14400 ;
    END
  END wdata[270]
  PIN wdata[271]
    DIRECTION INPUT ;
    USE SIGNAL ;
    PORT
      LAYER M4 ;
      RECT 0.00000 237.40800 0.02400 237.43200 ;
    END
  END wdata[271]
  PIN wdata[272]
    DIRECTION INPUT ;
    USE SIGNAL ;
    PORT
      LAYER M4 ;
      RECT 0.00000 237.69600 0.02400 237.72000 ;
    END
  END wdata[272]
  PIN wdata[273]
    DIRECTION INPUT ;
    USE SIGNAL ;
    PORT
      LAYER M4 ;
      RECT 0.00000 237.98400 0.02400 238.00800 ;
    END
  END wdata[273]
  PIN wdata[274]
    DIRECTION INPUT ;
    USE SIGNAL ;
    PORT
      LAYER M4 ;
      RECT 0.00000 238.27200 0.02400 238.29600 ;
    END
  END wdata[274]
  PIN wdata[275]
    DIRECTION INPUT ;
    USE SIGNAL ;
    PORT
      LAYER M4 ;
      RECT 0.00000 238.56000 0.02400 238.58400 ;
    END
  END wdata[275]
  PIN wdata[276]
    DIRECTION INPUT ;
    USE SIGNAL ;
    PORT
      LAYER M4 ;
      RECT 0.00000 238.84800 0.02400 238.87200 ;
    END
  END wdata[276]
  PIN wdata[277]
    DIRECTION INPUT ;
    USE SIGNAL ;
    PORT
      LAYER M4 ;
      RECT 0.00000 239.13600 0.02400 239.16000 ;
    END
  END wdata[277]
  PIN wdata[278]
    DIRECTION INPUT ;
    USE SIGNAL ;
    PORT
      LAYER M4 ;
      RECT 0.00000 239.42400 0.02400 239.44800 ;
    END
  END wdata[278]
  PIN wdata[279]
    DIRECTION INPUT ;
    USE SIGNAL ;
    PORT
      LAYER M4 ;
      RECT 0.00000 239.71200 0.02400 239.73600 ;
    END
  END wdata[279]
  PIN wdata[280]
    DIRECTION INPUT ;
    USE SIGNAL ;
    PORT
      LAYER M4 ;
      RECT 0.00000 240.00000 0.02400 240.02400 ;
    END
  END wdata[280]
  PIN wdata[281]
    DIRECTION INPUT ;
    USE SIGNAL ;
    PORT
      LAYER M4 ;
      RECT 0.00000 240.28800 0.02400 240.31200 ;
    END
  END wdata[281]
  PIN wdata[282]
    DIRECTION INPUT ;
    USE SIGNAL ;
    PORT
      LAYER M4 ;
      RECT 0.00000 240.57600 0.02400 240.60000 ;
    END
  END wdata[282]
  PIN wdata[283]
    DIRECTION INPUT ;
    USE SIGNAL ;
    PORT
      LAYER M4 ;
      RECT 0.00000 240.86400 0.02400 240.88800 ;
    END
  END wdata[283]
  PIN wdata[284]
    DIRECTION INPUT ;
    USE SIGNAL ;
    PORT
      LAYER M4 ;
      RECT 0.00000 241.15200 0.02400 241.17600 ;
    END
  END wdata[284]
  PIN wdata[285]
    DIRECTION INPUT ;
    USE SIGNAL ;
    PORT
      LAYER M4 ;
      RECT 0.00000 241.44000 0.02400 241.46400 ;
    END
  END wdata[285]
  PIN wdata[286]
    DIRECTION INPUT ;
    USE SIGNAL ;
    PORT
      LAYER M4 ;
      RECT 0.00000 241.72800 0.02400 241.75200 ;
    END
  END wdata[286]
  PIN wdata[287]
    DIRECTION INPUT ;
    USE SIGNAL ;
    PORT
      LAYER M4 ;
      RECT 0.00000 242.01600 0.02400 242.04000 ;
    END
  END wdata[287]
  PIN wdata[288]
    DIRECTION INPUT ;
    USE SIGNAL ;
    PORT
      LAYER M4 ;
      RECT 0.00000 242.30400 0.02400 242.32800 ;
    END
  END wdata[288]
  PIN wdata[289]
    DIRECTION INPUT ;
    USE SIGNAL ;
    PORT
      LAYER M4 ;
      RECT 0.00000 242.59200 0.02400 242.61600 ;
    END
  END wdata[289]
  PIN wdata[290]
    DIRECTION INPUT ;
    USE SIGNAL ;
    PORT
      LAYER M4 ;
      RECT 0.00000 242.88000 0.02400 242.90400 ;
    END
  END wdata[290]
  PIN wdata[291]
    DIRECTION INPUT ;
    USE SIGNAL ;
    PORT
      LAYER M4 ;
      RECT 0.00000 243.16800 0.02400 243.19200 ;
    END
  END wdata[291]
  PIN wdata[292]
    DIRECTION INPUT ;
    USE SIGNAL ;
    PORT
      LAYER M4 ;
      RECT 0.00000 243.45600 0.02400 243.48000 ;
    END
  END wdata[292]
  PIN wdata[293]
    DIRECTION INPUT ;
    USE SIGNAL ;
    PORT
      LAYER M4 ;
      RECT 0.00000 243.74400 0.02400 243.76800 ;
    END
  END wdata[293]
  PIN wdata[294]
    DIRECTION INPUT ;
    USE SIGNAL ;
    PORT
      LAYER M4 ;
      RECT 0.00000 244.03200 0.02400 244.05600 ;
    END
  END wdata[294]
  PIN wdata[295]
    DIRECTION INPUT ;
    USE SIGNAL ;
    PORT
      LAYER M4 ;
      RECT 0.00000 244.32000 0.02400 244.34400 ;
    END
  END wdata[295]
  PIN wdata[296]
    DIRECTION INPUT ;
    USE SIGNAL ;
    PORT
      LAYER M4 ;
      RECT 0.00000 244.60800 0.02400 244.63200 ;
    END
  END wdata[296]
  PIN wdata[297]
    DIRECTION INPUT ;
    USE SIGNAL ;
    PORT
      LAYER M4 ;
      RECT 0.00000 244.89600 0.02400 244.92000 ;
    END
  END wdata[297]
  PIN wdata[298]
    DIRECTION INPUT ;
    USE SIGNAL ;
    PORT
      LAYER M4 ;
      RECT 0.00000 245.18400 0.02400 245.20800 ;
    END
  END wdata[298]
  PIN wdata[299]
    DIRECTION INPUT ;
    USE SIGNAL ;
    PORT
      LAYER M4 ;
      RECT 0.00000 245.47200 0.02400 245.49600 ;
    END
  END wdata[299]
  PIN wdata[300]
    DIRECTION INPUT ;
    USE SIGNAL ;
    PORT
      LAYER M4 ;
      RECT 0.00000 245.76000 0.02400 245.78400 ;
    END
  END wdata[300]
  PIN wdata[301]
    DIRECTION INPUT ;
    USE SIGNAL ;
    PORT
      LAYER M4 ;
      RECT 0.00000 246.04800 0.02400 246.07200 ;
    END
  END wdata[301]
  PIN wdata[302]
    DIRECTION INPUT ;
    USE SIGNAL ;
    PORT
      LAYER M4 ;
      RECT 0.00000 246.33600 0.02400 246.36000 ;
    END
  END wdata[302]
  PIN wdata[303]
    DIRECTION INPUT ;
    USE SIGNAL ;
    PORT
      LAYER M4 ;
      RECT 0.00000 246.62400 0.02400 246.64800 ;
    END
  END wdata[303]
  PIN wdata[304]
    DIRECTION INPUT ;
    USE SIGNAL ;
    PORT
      LAYER M4 ;
      RECT 0.00000 246.91200 0.02400 246.93600 ;
    END
  END wdata[304]
  PIN wdata[305]
    DIRECTION INPUT ;
    USE SIGNAL ;
    PORT
      LAYER M4 ;
      RECT 0.00000 247.20000 0.02400 247.22400 ;
    END
  END wdata[305]
  PIN wdata[306]
    DIRECTION INPUT ;
    USE SIGNAL ;
    PORT
      LAYER M4 ;
      RECT 0.00000 247.48800 0.02400 247.51200 ;
    END
  END wdata[306]
  PIN wdata[307]
    DIRECTION INPUT ;
    USE SIGNAL ;
    PORT
      LAYER M4 ;
      RECT 0.00000 247.77600 0.02400 247.80000 ;
    END
  END wdata[307]
  PIN wdata[308]
    DIRECTION INPUT ;
    USE SIGNAL ;
    PORT
      LAYER M4 ;
      RECT 0.00000 248.06400 0.02400 248.08800 ;
    END
  END wdata[308]
  PIN wdata[309]
    DIRECTION INPUT ;
    USE SIGNAL ;
    PORT
      LAYER M4 ;
      RECT 0.00000 248.35200 0.02400 248.37600 ;
    END
  END wdata[309]
  PIN wdata[310]
    DIRECTION INPUT ;
    USE SIGNAL ;
    PORT
      LAYER M4 ;
      RECT 0.00000 248.64000 0.02400 248.66400 ;
    END
  END wdata[310]
  PIN wdata[311]
    DIRECTION INPUT ;
    USE SIGNAL ;
    PORT
      LAYER M4 ;
      RECT 0.00000 248.92800 0.02400 248.95200 ;
    END
  END wdata[311]
  PIN wdata[312]
    DIRECTION INPUT ;
    USE SIGNAL ;
    PORT
      LAYER M4 ;
      RECT 0.00000 249.21600 0.02400 249.24000 ;
    END
  END wdata[312]
  PIN wdata[313]
    DIRECTION INPUT ;
    USE SIGNAL ;
    PORT
      LAYER M4 ;
      RECT 0.00000 249.50400 0.02400 249.52800 ;
    END
  END wdata[313]
  PIN wdata[314]
    DIRECTION INPUT ;
    USE SIGNAL ;
    PORT
      LAYER M4 ;
      RECT 0.00000 249.79200 0.02400 249.81600 ;
    END
  END wdata[314]
  PIN wdata[315]
    DIRECTION INPUT ;
    USE SIGNAL ;
    PORT
      LAYER M4 ;
      RECT 0.00000 250.08000 0.02400 250.10400 ;
    END
  END wdata[315]
  PIN wdata[316]
    DIRECTION INPUT ;
    USE SIGNAL ;
    PORT
      LAYER M4 ;
      RECT 0.00000 250.36800 0.02400 250.39200 ;
    END
  END wdata[316]
  PIN wdata[317]
    DIRECTION INPUT ;
    USE SIGNAL ;
    PORT
      LAYER M4 ;
      RECT 0.00000 250.65600 0.02400 250.68000 ;
    END
  END wdata[317]
  PIN wdata[318]
    DIRECTION INPUT ;
    USE SIGNAL ;
    PORT
      LAYER M4 ;
      RECT 0.00000 250.94400 0.02400 250.96800 ;
    END
  END wdata[318]
  PIN wdata[319]
    DIRECTION INPUT ;
    USE SIGNAL ;
    PORT
      LAYER M4 ;
      RECT 0.00000 251.23200 0.02400 251.25600 ;
    END
  END wdata[319]
  PIN wdata[320]
    DIRECTION INPUT ;
    USE SIGNAL ;
    PORT
      LAYER M4 ;
      RECT 0.00000 251.52000 0.02400 251.54400 ;
    END
  END wdata[320]
  PIN wdata[321]
    DIRECTION INPUT ;
    USE SIGNAL ;
    PORT
      LAYER M4 ;
      RECT 0.00000 251.80800 0.02400 251.83200 ;
    END
  END wdata[321]
  PIN wdata[322]
    DIRECTION INPUT ;
    USE SIGNAL ;
    PORT
      LAYER M4 ;
      RECT 0.00000 252.09600 0.02400 252.12000 ;
    END
  END wdata[322]
  PIN wdata[323]
    DIRECTION INPUT ;
    USE SIGNAL ;
    PORT
      LAYER M4 ;
      RECT 0.00000 252.38400 0.02400 252.40800 ;
    END
  END wdata[323]
  PIN wdata[324]
    DIRECTION INPUT ;
    USE SIGNAL ;
    PORT
      LAYER M4 ;
      RECT 0.00000 252.67200 0.02400 252.69600 ;
    END
  END wdata[324]
  PIN wdata[325]
    DIRECTION INPUT ;
    USE SIGNAL ;
    PORT
      LAYER M4 ;
      RECT 0.00000 252.96000 0.02400 252.98400 ;
    END
  END wdata[325]
  PIN wdata[326]
    DIRECTION INPUT ;
    USE SIGNAL ;
    PORT
      LAYER M4 ;
      RECT 0.00000 253.24800 0.02400 253.27200 ;
    END
  END wdata[326]
  PIN wdata[327]
    DIRECTION INPUT ;
    USE SIGNAL ;
    PORT
      LAYER M4 ;
      RECT 0.00000 253.53600 0.02400 253.56000 ;
    END
  END wdata[327]
  PIN wdata[328]
    DIRECTION INPUT ;
    USE SIGNAL ;
    PORT
      LAYER M4 ;
      RECT 0.00000 253.82400 0.02400 253.84800 ;
    END
  END wdata[328]
  PIN wdata[329]
    DIRECTION INPUT ;
    USE SIGNAL ;
    PORT
      LAYER M4 ;
      RECT 0.00000 254.11200 0.02400 254.13600 ;
    END
  END wdata[329]
  PIN wdata[330]
    DIRECTION INPUT ;
    USE SIGNAL ;
    PORT
      LAYER M4 ;
      RECT 0.00000 254.40000 0.02400 254.42400 ;
    END
  END wdata[330]
  PIN wdata[331]
    DIRECTION INPUT ;
    USE SIGNAL ;
    PORT
      LAYER M4 ;
      RECT 0.00000 254.68800 0.02400 254.71200 ;
    END
  END wdata[331]
  PIN wdata[332]
    DIRECTION INPUT ;
    USE SIGNAL ;
    PORT
      LAYER M4 ;
      RECT 0.00000 254.97600 0.02400 255.00000 ;
    END
  END wdata[332]
  PIN wdata[333]
    DIRECTION INPUT ;
    USE SIGNAL ;
    PORT
      LAYER M4 ;
      RECT 0.00000 255.26400 0.02400 255.28800 ;
    END
  END wdata[333]
  PIN wdata[334]
    DIRECTION INPUT ;
    USE SIGNAL ;
    PORT
      LAYER M4 ;
      RECT 0.00000 255.55200 0.02400 255.57600 ;
    END
  END wdata[334]
  PIN wdata[335]
    DIRECTION INPUT ;
    USE SIGNAL ;
    PORT
      LAYER M4 ;
      RECT 0.00000 255.84000 0.02400 255.86400 ;
    END
  END wdata[335]
  PIN wdata[336]
    DIRECTION INPUT ;
    USE SIGNAL ;
    PORT
      LAYER M4 ;
      RECT 0.00000 256.12800 0.02400 256.15200 ;
    END
  END wdata[336]
  PIN wdata[337]
    DIRECTION INPUT ;
    USE SIGNAL ;
    PORT
      LAYER M4 ;
      RECT 0.00000 256.41600 0.02400 256.44000 ;
    END
  END wdata[337]
  PIN wdata[338]
    DIRECTION INPUT ;
    USE SIGNAL ;
    PORT
      LAYER M4 ;
      RECT 0.00000 256.70400 0.02400 256.72800 ;
    END
  END wdata[338]
  PIN wdata[339]
    DIRECTION INPUT ;
    USE SIGNAL ;
    PORT
      LAYER M4 ;
      RECT 0.00000 256.99200 0.02400 257.01600 ;
    END
  END wdata[339]
  PIN wdata[340]
    DIRECTION INPUT ;
    USE SIGNAL ;
    PORT
      LAYER M4 ;
      RECT 0.00000 257.28000 0.02400 257.30400 ;
    END
  END wdata[340]
  PIN wdata[341]
    DIRECTION INPUT ;
    USE SIGNAL ;
    PORT
      LAYER M4 ;
      RECT 0.00000 257.56800 0.02400 257.59200 ;
    END
  END wdata[341]
  PIN wdata[342]
    DIRECTION INPUT ;
    USE SIGNAL ;
    PORT
      LAYER M4 ;
      RECT 0.00000 257.85600 0.02400 257.88000 ;
    END
  END wdata[342]
  PIN wdata[343]
    DIRECTION INPUT ;
    USE SIGNAL ;
    PORT
      LAYER M4 ;
      RECT 0.00000 258.14400 0.02400 258.16800 ;
    END
  END wdata[343]
  PIN wdata[344]
    DIRECTION INPUT ;
    USE SIGNAL ;
    PORT
      LAYER M4 ;
      RECT 0.00000 258.43200 0.02400 258.45600 ;
    END
  END wdata[344]
  PIN wdata[345]
    DIRECTION INPUT ;
    USE SIGNAL ;
    PORT
      LAYER M4 ;
      RECT 0.00000 258.72000 0.02400 258.74400 ;
    END
  END wdata[345]
  PIN wdata[346]
    DIRECTION INPUT ;
    USE SIGNAL ;
    PORT
      LAYER M4 ;
      RECT 0.00000 259.00800 0.02400 259.03200 ;
    END
  END wdata[346]
  PIN wdata[347]
    DIRECTION INPUT ;
    USE SIGNAL ;
    PORT
      LAYER M4 ;
      RECT 0.00000 259.29600 0.02400 259.32000 ;
    END
  END wdata[347]
  PIN wdata[348]
    DIRECTION INPUT ;
    USE SIGNAL ;
    PORT
      LAYER M4 ;
      RECT 0.00000 259.58400 0.02400 259.60800 ;
    END
  END wdata[348]
  PIN wdata[349]
    DIRECTION INPUT ;
    USE SIGNAL ;
    PORT
      LAYER M4 ;
      RECT 0.00000 259.87200 0.02400 259.89600 ;
    END
  END wdata[349]
  PIN wdata[350]
    DIRECTION INPUT ;
    USE SIGNAL ;
    PORT
      LAYER M4 ;
      RECT 0.00000 260.16000 0.02400 260.18400 ;
    END
  END wdata[350]
  PIN wdata[351]
    DIRECTION INPUT ;
    USE SIGNAL ;
    PORT
      LAYER M4 ;
      RECT 0.00000 260.44800 0.02400 260.47200 ;
    END
  END wdata[351]
  PIN wdata[352]
    DIRECTION INPUT ;
    USE SIGNAL ;
    PORT
      LAYER M4 ;
      RECT 0.00000 260.73600 0.02400 260.76000 ;
    END
  END wdata[352]
  PIN wdata[353]
    DIRECTION INPUT ;
    USE SIGNAL ;
    PORT
      LAYER M4 ;
      RECT 0.00000 261.02400 0.02400 261.04800 ;
    END
  END wdata[353]
  PIN wdata[354]
    DIRECTION INPUT ;
    USE SIGNAL ;
    PORT
      LAYER M4 ;
      RECT 0.00000 261.31200 0.02400 261.33600 ;
    END
  END wdata[354]
  PIN wdata[355]
    DIRECTION INPUT ;
    USE SIGNAL ;
    PORT
      LAYER M4 ;
      RECT 0.00000 261.60000 0.02400 261.62400 ;
    END
  END wdata[355]
  PIN wdata[356]
    DIRECTION INPUT ;
    USE SIGNAL ;
    PORT
      LAYER M4 ;
      RECT 0.00000 261.88800 0.02400 261.91200 ;
    END
  END wdata[356]
  PIN wdata[357]
    DIRECTION INPUT ;
    USE SIGNAL ;
    PORT
      LAYER M4 ;
      RECT 0.00000 262.17600 0.02400 262.20000 ;
    END
  END wdata[357]
  PIN wdata[358]
    DIRECTION INPUT ;
    USE SIGNAL ;
    PORT
      LAYER M4 ;
      RECT 0.00000 262.46400 0.02400 262.48800 ;
    END
  END wdata[358]
  PIN wdata[359]
    DIRECTION INPUT ;
    USE SIGNAL ;
    PORT
      LAYER M4 ;
      RECT 0.00000 262.75200 0.02400 262.77600 ;
    END
  END wdata[359]
  PIN wdata[360]
    DIRECTION INPUT ;
    USE SIGNAL ;
    PORT
      LAYER M4 ;
      RECT 0.00000 263.04000 0.02400 263.06400 ;
    END
  END wdata[360]
  PIN wdata[361]
    DIRECTION INPUT ;
    USE SIGNAL ;
    PORT
      LAYER M4 ;
      RECT 0.00000 263.32800 0.02400 263.35200 ;
    END
  END wdata[361]
  PIN wdata[362]
    DIRECTION INPUT ;
    USE SIGNAL ;
    PORT
      LAYER M4 ;
      RECT 0.00000 263.61600 0.02400 263.64000 ;
    END
  END wdata[362]
  PIN wdata[363]
    DIRECTION INPUT ;
    USE SIGNAL ;
    PORT
      LAYER M4 ;
      RECT 0.00000 263.90400 0.02400 263.92800 ;
    END
  END wdata[363]
  PIN wdata[364]
    DIRECTION INPUT ;
    USE SIGNAL ;
    PORT
      LAYER M4 ;
      RECT 0.00000 264.19200 0.02400 264.21600 ;
    END
  END wdata[364]
  PIN wdata[365]
    DIRECTION INPUT ;
    USE SIGNAL ;
    PORT
      LAYER M4 ;
      RECT 0.00000 264.48000 0.02400 264.50400 ;
    END
  END wdata[365]
  PIN wdata[366]
    DIRECTION INPUT ;
    USE SIGNAL ;
    PORT
      LAYER M4 ;
      RECT 0.00000 264.76800 0.02400 264.79200 ;
    END
  END wdata[366]
  PIN wdata[367]
    DIRECTION INPUT ;
    USE SIGNAL ;
    PORT
      LAYER M4 ;
      RECT 0.00000 265.05600 0.02400 265.08000 ;
    END
  END wdata[367]
  PIN wdata[368]
    DIRECTION INPUT ;
    USE SIGNAL ;
    PORT
      LAYER M4 ;
      RECT 0.00000 265.34400 0.02400 265.36800 ;
    END
  END wdata[368]
  PIN wdata[369]
    DIRECTION INPUT ;
    USE SIGNAL ;
    PORT
      LAYER M4 ;
      RECT 0.00000 265.63200 0.02400 265.65600 ;
    END
  END wdata[369]
  PIN wdata[370]
    DIRECTION INPUT ;
    USE SIGNAL ;
    PORT
      LAYER M4 ;
      RECT 0.00000 265.92000 0.02400 265.94400 ;
    END
  END wdata[370]
  PIN wdata[371]
    DIRECTION INPUT ;
    USE SIGNAL ;
    PORT
      LAYER M4 ;
      RECT 0.00000 266.20800 0.02400 266.23200 ;
    END
  END wdata[371]
  PIN wdata[372]
    DIRECTION INPUT ;
    USE SIGNAL ;
    PORT
      LAYER M4 ;
      RECT 0.00000 266.49600 0.02400 266.52000 ;
    END
  END wdata[372]
  PIN wdata[373]
    DIRECTION INPUT ;
    USE SIGNAL ;
    PORT
      LAYER M4 ;
      RECT 0.00000 266.78400 0.02400 266.80800 ;
    END
  END wdata[373]
  PIN wdata[374]
    DIRECTION INPUT ;
    USE SIGNAL ;
    PORT
      LAYER M4 ;
      RECT 0.00000 267.07200 0.02400 267.09600 ;
    END
  END wdata[374]
  PIN wdata[375]
    DIRECTION INPUT ;
    USE SIGNAL ;
    PORT
      LAYER M4 ;
      RECT 0.00000 267.36000 0.02400 267.38400 ;
    END
  END wdata[375]
  PIN wdata[376]
    DIRECTION INPUT ;
    USE SIGNAL ;
    PORT
      LAYER M4 ;
      RECT 0.00000 267.64800 0.02400 267.67200 ;
    END
  END wdata[376]
  PIN wdata[377]
    DIRECTION INPUT ;
    USE SIGNAL ;
    PORT
      LAYER M4 ;
      RECT 0.00000 267.93600 0.02400 267.96000 ;
    END
  END wdata[377]
  PIN wdata[378]
    DIRECTION INPUT ;
    USE SIGNAL ;
    PORT
      LAYER M4 ;
      RECT 0.00000 268.22400 0.02400 268.24800 ;
    END
  END wdata[378]
  PIN wdata[379]
    DIRECTION INPUT ;
    USE SIGNAL ;
    PORT
      LAYER M4 ;
      RECT 0.00000 268.51200 0.02400 268.53600 ;
    END
  END wdata[379]
  PIN wdata[380]
    DIRECTION INPUT ;
    USE SIGNAL ;
    PORT
      LAYER M4 ;
      RECT 0.00000 268.80000 0.02400 268.82400 ;
    END
  END wdata[380]
  PIN wdata[381]
    DIRECTION INPUT ;
    USE SIGNAL ;
    PORT
      LAYER M4 ;
      RECT 0.00000 269.08800 0.02400 269.11200 ;
    END
  END wdata[381]
  PIN wdata[382]
    DIRECTION INPUT ;
    USE SIGNAL ;
    PORT
      LAYER M4 ;
      RECT 0.00000 269.37600 0.02400 269.40000 ;
    END
  END wdata[382]
  PIN wdata[383]
    DIRECTION INPUT ;
    USE SIGNAL ;
    PORT
      LAYER M4 ;
      RECT 0.00000 269.66400 0.02400 269.68800 ;
    END
  END wdata[383]
  PIN wdata[384]
    DIRECTION INPUT ;
    USE SIGNAL ;
    PORT
      LAYER M4 ;
      RECT 0.00000 269.95200 0.02400 269.97600 ;
    END
  END wdata[384]
  PIN wdata[385]
    DIRECTION INPUT ;
    USE SIGNAL ;
    PORT
      LAYER M4 ;
      RECT 0.00000 270.24000 0.02400 270.26400 ;
    END
  END wdata[385]
  PIN wdata[386]
    DIRECTION INPUT ;
    USE SIGNAL ;
    PORT
      LAYER M4 ;
      RECT 0.00000 270.52800 0.02400 270.55200 ;
    END
  END wdata[386]
  PIN wdata[387]
    DIRECTION INPUT ;
    USE SIGNAL ;
    PORT
      LAYER M4 ;
      RECT 0.00000 270.81600 0.02400 270.84000 ;
    END
  END wdata[387]
  PIN wdata[388]
    DIRECTION INPUT ;
    USE SIGNAL ;
    PORT
      LAYER M4 ;
      RECT 0.00000 271.10400 0.02400 271.12800 ;
    END
  END wdata[388]
  PIN wdata[389]
    DIRECTION INPUT ;
    USE SIGNAL ;
    PORT
      LAYER M4 ;
      RECT 0.00000 271.39200 0.02400 271.41600 ;
    END
  END wdata[389]
  PIN wdata[390]
    DIRECTION INPUT ;
    USE SIGNAL ;
    PORT
      LAYER M4 ;
      RECT 0.00000 271.68000 0.02400 271.70400 ;
    END
  END wdata[390]
  PIN wdata[391]
    DIRECTION INPUT ;
    USE SIGNAL ;
    PORT
      LAYER M4 ;
      RECT 0.00000 271.96800 0.02400 271.99200 ;
    END
  END wdata[391]
  PIN wdata[392]
    DIRECTION INPUT ;
    USE SIGNAL ;
    PORT
      LAYER M4 ;
      RECT 0.00000 272.25600 0.02400 272.28000 ;
    END
  END wdata[392]
  PIN wdata[393]
    DIRECTION INPUT ;
    USE SIGNAL ;
    PORT
      LAYER M4 ;
      RECT 0.00000 272.54400 0.02400 272.56800 ;
    END
  END wdata[393]
  PIN wdata[394]
    DIRECTION INPUT ;
    USE SIGNAL ;
    PORT
      LAYER M4 ;
      RECT 0.00000 272.83200 0.02400 272.85600 ;
    END
  END wdata[394]
  PIN wdata[395]
    DIRECTION INPUT ;
    USE SIGNAL ;
    PORT
      LAYER M4 ;
      RECT 0.00000 273.12000 0.02400 273.14400 ;
    END
  END wdata[395]
  PIN wdata[396]
    DIRECTION INPUT ;
    USE SIGNAL ;
    PORT
      LAYER M4 ;
      RECT 0.00000 273.40800 0.02400 273.43200 ;
    END
  END wdata[396]
  PIN wdata[397]
    DIRECTION INPUT ;
    USE SIGNAL ;
    PORT
      LAYER M4 ;
      RECT 0.00000 273.69600 0.02400 273.72000 ;
    END
  END wdata[397]
  PIN wdata[398]
    DIRECTION INPUT ;
    USE SIGNAL ;
    PORT
      LAYER M4 ;
      RECT 0.00000 273.98400 0.02400 274.00800 ;
    END
  END wdata[398]
  PIN wdata[399]
    DIRECTION INPUT ;
    USE SIGNAL ;
    PORT
      LAYER M4 ;
      RECT 0.00000 274.27200 0.02400 274.29600 ;
    END
  END wdata[399]
  PIN wdata[400]
    DIRECTION INPUT ;
    USE SIGNAL ;
    PORT
      LAYER M4 ;
      RECT 0.00000 274.56000 0.02400 274.58400 ;
    END
  END wdata[400]
  PIN wdata[401]
    DIRECTION INPUT ;
    USE SIGNAL ;
    PORT
      LAYER M4 ;
      RECT 0.00000 274.84800 0.02400 274.87200 ;
    END
  END wdata[401]
  PIN wdata[402]
    DIRECTION INPUT ;
    USE SIGNAL ;
    PORT
      LAYER M4 ;
      RECT 0.00000 275.13600 0.02400 275.16000 ;
    END
  END wdata[402]
  PIN wdata[403]
    DIRECTION INPUT ;
    USE SIGNAL ;
    PORT
      LAYER M4 ;
      RECT 0.00000 275.42400 0.02400 275.44800 ;
    END
  END wdata[403]
  PIN wdata[404]
    DIRECTION INPUT ;
    USE SIGNAL ;
    PORT
      LAYER M4 ;
      RECT 0.00000 275.71200 0.02400 275.73600 ;
    END
  END wdata[404]
  PIN wdata[405]
    DIRECTION INPUT ;
    USE SIGNAL ;
    PORT
      LAYER M4 ;
      RECT 0.00000 276.00000 0.02400 276.02400 ;
    END
  END wdata[405]
  PIN wdata[406]
    DIRECTION INPUT ;
    USE SIGNAL ;
    PORT
      LAYER M4 ;
      RECT 0.00000 276.28800 0.02400 276.31200 ;
    END
  END wdata[406]
  PIN wdata[407]
    DIRECTION INPUT ;
    USE SIGNAL ;
    PORT
      LAYER M4 ;
      RECT 0.00000 276.57600 0.02400 276.60000 ;
    END
  END wdata[407]
  PIN wdata[408]
    DIRECTION INPUT ;
    USE SIGNAL ;
    PORT
      LAYER M4 ;
      RECT 0.00000 276.86400 0.02400 276.88800 ;
    END
  END wdata[408]
  PIN wdata[409]
    DIRECTION INPUT ;
    USE SIGNAL ;
    PORT
      LAYER M4 ;
      RECT 0.00000 277.15200 0.02400 277.17600 ;
    END
  END wdata[409]
  PIN wdata[410]
    DIRECTION INPUT ;
    USE SIGNAL ;
    PORT
      LAYER M4 ;
      RECT 0.00000 277.44000 0.02400 277.46400 ;
    END
  END wdata[410]
  PIN wdata[411]
    DIRECTION INPUT ;
    USE SIGNAL ;
    PORT
      LAYER M4 ;
      RECT 0.00000 277.72800 0.02400 277.75200 ;
    END
  END wdata[411]
  PIN wdata[412]
    DIRECTION INPUT ;
    USE SIGNAL ;
    PORT
      LAYER M4 ;
      RECT 0.00000 278.01600 0.02400 278.04000 ;
    END
  END wdata[412]
  PIN wdata[413]
    DIRECTION INPUT ;
    USE SIGNAL ;
    PORT
      LAYER M4 ;
      RECT 0.00000 278.30400 0.02400 278.32800 ;
    END
  END wdata[413]
  PIN wdata[414]
    DIRECTION INPUT ;
    USE SIGNAL ;
    PORT
      LAYER M4 ;
      RECT 0.00000 278.59200 0.02400 278.61600 ;
    END
  END wdata[414]
  PIN wdata[415]
    DIRECTION INPUT ;
    USE SIGNAL ;
    PORT
      LAYER M4 ;
      RECT 0.00000 278.88000 0.02400 278.90400 ;
    END
  END wdata[415]
  PIN wdata[416]
    DIRECTION INPUT ;
    USE SIGNAL ;
    PORT
      LAYER M4 ;
      RECT 0.00000 279.16800 0.02400 279.19200 ;
    END
  END wdata[416]
  PIN wdata[417]
    DIRECTION INPUT ;
    USE SIGNAL ;
    PORT
      LAYER M4 ;
      RECT 0.00000 279.45600 0.02400 279.48000 ;
    END
  END wdata[417]
  PIN wdata[418]
    DIRECTION INPUT ;
    USE SIGNAL ;
    PORT
      LAYER M4 ;
      RECT 0.00000 279.74400 0.02400 279.76800 ;
    END
  END wdata[418]
  PIN wdata[419]
    DIRECTION INPUT ;
    USE SIGNAL ;
    PORT
      LAYER M4 ;
      RECT 0.00000 280.03200 0.02400 280.05600 ;
    END
  END wdata[419]
  PIN wdata[420]
    DIRECTION INPUT ;
    USE SIGNAL ;
    PORT
      LAYER M4 ;
      RECT 0.00000 280.32000 0.02400 280.34400 ;
    END
  END wdata[420]
  PIN wdata[421]
    DIRECTION INPUT ;
    USE SIGNAL ;
    PORT
      LAYER M4 ;
      RECT 0.00000 280.60800 0.02400 280.63200 ;
    END
  END wdata[421]
  PIN wdata[422]
    DIRECTION INPUT ;
    USE SIGNAL ;
    PORT
      LAYER M4 ;
      RECT 0.00000 280.89600 0.02400 280.92000 ;
    END
  END wdata[422]
  PIN wdata[423]
    DIRECTION INPUT ;
    USE SIGNAL ;
    PORT
      LAYER M4 ;
      RECT 0.00000 281.18400 0.02400 281.20800 ;
    END
  END wdata[423]
  PIN wdata[424]
    DIRECTION INPUT ;
    USE SIGNAL ;
    PORT
      LAYER M4 ;
      RECT 0.00000 281.47200 0.02400 281.49600 ;
    END
  END wdata[424]
  PIN wdata[425]
    DIRECTION INPUT ;
    USE SIGNAL ;
    PORT
      LAYER M4 ;
      RECT 0.00000 281.76000 0.02400 281.78400 ;
    END
  END wdata[425]
  PIN wdata[426]
    DIRECTION INPUT ;
    USE SIGNAL ;
    PORT
      LAYER M4 ;
      RECT 0.00000 282.04800 0.02400 282.07200 ;
    END
  END wdata[426]
  PIN wdata[427]
    DIRECTION INPUT ;
    USE SIGNAL ;
    PORT
      LAYER M4 ;
      RECT 0.00000 282.33600 0.02400 282.36000 ;
    END
  END wdata[427]
  PIN wdata[428]
    DIRECTION INPUT ;
    USE SIGNAL ;
    PORT
      LAYER M4 ;
      RECT 0.00000 282.62400 0.02400 282.64800 ;
    END
  END wdata[428]
  PIN wdata[429]
    DIRECTION INPUT ;
    USE SIGNAL ;
    PORT
      LAYER M4 ;
      RECT 0.00000 282.91200 0.02400 282.93600 ;
    END
  END wdata[429]
  PIN wdata[430]
    DIRECTION INPUT ;
    USE SIGNAL ;
    PORT
      LAYER M4 ;
      RECT 0.00000 283.20000 0.02400 283.22400 ;
    END
  END wdata[430]
  PIN wdata[431]
    DIRECTION INPUT ;
    USE SIGNAL ;
    PORT
      LAYER M4 ;
      RECT 0.00000 283.48800 0.02400 283.51200 ;
    END
  END wdata[431]
  PIN wdata[432]
    DIRECTION INPUT ;
    USE SIGNAL ;
    PORT
      LAYER M4 ;
      RECT 0.00000 283.77600 0.02400 283.80000 ;
    END
  END wdata[432]
  PIN wdata[433]
    DIRECTION INPUT ;
    USE SIGNAL ;
    PORT
      LAYER M4 ;
      RECT 0.00000 284.06400 0.02400 284.08800 ;
    END
  END wdata[433]
  PIN wdata[434]
    DIRECTION INPUT ;
    USE SIGNAL ;
    PORT
      LAYER M4 ;
      RECT 0.00000 284.35200 0.02400 284.37600 ;
    END
  END wdata[434]
  PIN wdata[435]
    DIRECTION INPUT ;
    USE SIGNAL ;
    PORT
      LAYER M4 ;
      RECT 0.00000 284.64000 0.02400 284.66400 ;
    END
  END wdata[435]
  PIN wdata[436]
    DIRECTION INPUT ;
    USE SIGNAL ;
    PORT
      LAYER M4 ;
      RECT 0.00000 284.92800 0.02400 284.95200 ;
    END
  END wdata[436]
  PIN wdata[437]
    DIRECTION INPUT ;
    USE SIGNAL ;
    PORT
      LAYER M4 ;
      RECT 0.00000 285.21600 0.02400 285.24000 ;
    END
  END wdata[437]
  PIN wdata[438]
    DIRECTION INPUT ;
    USE SIGNAL ;
    PORT
      LAYER M4 ;
      RECT 0.00000 285.50400 0.02400 285.52800 ;
    END
  END wdata[438]
  PIN wdata[439]
    DIRECTION INPUT ;
    USE SIGNAL ;
    PORT
      LAYER M4 ;
      RECT 0.00000 285.79200 0.02400 285.81600 ;
    END
  END wdata[439]
  PIN wdata[440]
    DIRECTION INPUT ;
    USE SIGNAL ;
    PORT
      LAYER M4 ;
      RECT 0.00000 286.08000 0.02400 286.10400 ;
    END
  END wdata[440]
  PIN wdata[441]
    DIRECTION INPUT ;
    USE SIGNAL ;
    PORT
      LAYER M4 ;
      RECT 0.00000 286.36800 0.02400 286.39200 ;
    END
  END wdata[441]
  PIN wdata[442]
    DIRECTION INPUT ;
    USE SIGNAL ;
    PORT
      LAYER M4 ;
      RECT 0.00000 286.65600 0.02400 286.68000 ;
    END
  END wdata[442]
  PIN wdata[443]
    DIRECTION INPUT ;
    USE SIGNAL ;
    PORT
      LAYER M4 ;
      RECT 0.00000 286.94400 0.02400 286.96800 ;
    END
  END wdata[443]
  PIN wdata[444]
    DIRECTION INPUT ;
    USE SIGNAL ;
    PORT
      LAYER M4 ;
      RECT 0.00000 287.23200 0.02400 287.25600 ;
    END
  END wdata[444]
  PIN wdata[445]
    DIRECTION INPUT ;
    USE SIGNAL ;
    PORT
      LAYER M4 ;
      RECT 0.00000 287.52000 0.02400 287.54400 ;
    END
  END wdata[445]
  PIN wdata[446]
    DIRECTION INPUT ;
    USE SIGNAL ;
    PORT
      LAYER M4 ;
      RECT 0.00000 287.80800 0.02400 287.83200 ;
    END
  END wdata[446]
  PIN wdata[447]
    DIRECTION INPUT ;
    USE SIGNAL ;
    PORT
      LAYER M4 ;
      RECT 0.00000 288.09600 0.02400 288.12000 ;
    END
  END wdata[447]
  PIN wdata[448]
    DIRECTION INPUT ;
    USE SIGNAL ;
    PORT
      LAYER M4 ;
      RECT 0.00000 288.38400 0.02400 288.40800 ;
    END
  END wdata[448]
  PIN wdata[449]
    DIRECTION INPUT ;
    USE SIGNAL ;
    PORT
      LAYER M4 ;
      RECT 0.00000 288.67200 0.02400 288.69600 ;
    END
  END wdata[449]
  PIN wdata[450]
    DIRECTION INPUT ;
    USE SIGNAL ;
    PORT
      LAYER M4 ;
      RECT 0.00000 288.96000 0.02400 288.98400 ;
    END
  END wdata[450]
  PIN wdata[451]
    DIRECTION INPUT ;
    USE SIGNAL ;
    PORT
      LAYER M4 ;
      RECT 0.00000 289.24800 0.02400 289.27200 ;
    END
  END wdata[451]
  PIN wdata[452]
    DIRECTION INPUT ;
    USE SIGNAL ;
    PORT
      LAYER M4 ;
      RECT 0.00000 289.53600 0.02400 289.56000 ;
    END
  END wdata[452]
  PIN wdata[453]
    DIRECTION INPUT ;
    USE SIGNAL ;
    PORT
      LAYER M4 ;
      RECT 0.00000 289.82400 0.02400 289.84800 ;
    END
  END wdata[453]
  PIN wdata[454]
    DIRECTION INPUT ;
    USE SIGNAL ;
    PORT
      LAYER M4 ;
      RECT 0.00000 290.11200 0.02400 290.13600 ;
    END
  END wdata[454]
  PIN wdata[455]
    DIRECTION INPUT ;
    USE SIGNAL ;
    PORT
      LAYER M4 ;
      RECT 0.00000 290.40000 0.02400 290.42400 ;
    END
  END wdata[455]
  PIN wdata[456]
    DIRECTION INPUT ;
    USE SIGNAL ;
    PORT
      LAYER M4 ;
      RECT 0.00000 290.68800 0.02400 290.71200 ;
    END
  END wdata[456]
  PIN wdata[457]
    DIRECTION INPUT ;
    USE SIGNAL ;
    PORT
      LAYER M4 ;
      RECT 0.00000 290.97600 0.02400 291.00000 ;
    END
  END wdata[457]
  PIN wdata[458]
    DIRECTION INPUT ;
    USE SIGNAL ;
    PORT
      LAYER M4 ;
      RECT 0.00000 291.26400 0.02400 291.28800 ;
    END
  END wdata[458]
  PIN wdata[459]
    DIRECTION INPUT ;
    USE SIGNAL ;
    PORT
      LAYER M4 ;
      RECT 0.00000 291.55200 0.02400 291.57600 ;
    END
  END wdata[459]
  PIN wdata[460]
    DIRECTION INPUT ;
    USE SIGNAL ;
    PORT
      LAYER M4 ;
      RECT 0.00000 291.84000 0.02400 291.86400 ;
    END
  END wdata[460]
  PIN wdata[461]
    DIRECTION INPUT ;
    USE SIGNAL ;
    PORT
      LAYER M4 ;
      RECT 0.00000 292.12800 0.02400 292.15200 ;
    END
  END wdata[461]
  PIN wdata[462]
    DIRECTION INPUT ;
    USE SIGNAL ;
    PORT
      LAYER M4 ;
      RECT 0.00000 292.41600 0.02400 292.44000 ;
    END
  END wdata[462]
  PIN wdata[463]
    DIRECTION INPUT ;
    USE SIGNAL ;
    PORT
      LAYER M4 ;
      RECT 0.00000 292.70400 0.02400 292.72800 ;
    END
  END wdata[463]
  PIN wdata[464]
    DIRECTION INPUT ;
    USE SIGNAL ;
    PORT
      LAYER M4 ;
      RECT 0.00000 292.99200 0.02400 293.01600 ;
    END
  END wdata[464]
  PIN wdata[465]
    DIRECTION INPUT ;
    USE SIGNAL ;
    PORT
      LAYER M4 ;
      RECT 0.00000 293.28000 0.02400 293.30400 ;
    END
  END wdata[465]
  PIN wdata[466]
    DIRECTION INPUT ;
    USE SIGNAL ;
    PORT
      LAYER M4 ;
      RECT 0.00000 293.56800 0.02400 293.59200 ;
    END
  END wdata[466]
  PIN wdata[467]
    DIRECTION INPUT ;
    USE SIGNAL ;
    PORT
      LAYER M4 ;
      RECT 0.00000 293.85600 0.02400 293.88000 ;
    END
  END wdata[467]
  PIN wdata[468]
    DIRECTION INPUT ;
    USE SIGNAL ;
    PORT
      LAYER M4 ;
      RECT 0.00000 294.14400 0.02400 294.16800 ;
    END
  END wdata[468]
  PIN wdata[469]
    DIRECTION INPUT ;
    USE SIGNAL ;
    PORT
      LAYER M4 ;
      RECT 0.00000 294.43200 0.02400 294.45600 ;
    END
  END wdata[469]
  PIN wdata[470]
    DIRECTION INPUT ;
    USE SIGNAL ;
    PORT
      LAYER M4 ;
      RECT 0.00000 294.72000 0.02400 294.74400 ;
    END
  END wdata[470]
  PIN wdata[471]
    DIRECTION INPUT ;
    USE SIGNAL ;
    PORT
      LAYER M4 ;
      RECT 0.00000 295.00800 0.02400 295.03200 ;
    END
  END wdata[471]
  PIN wdata[472]
    DIRECTION INPUT ;
    USE SIGNAL ;
    PORT
      LAYER M4 ;
      RECT 0.00000 295.29600 0.02400 295.32000 ;
    END
  END wdata[472]
  PIN wdata[473]
    DIRECTION INPUT ;
    USE SIGNAL ;
    PORT
      LAYER M4 ;
      RECT 0.00000 295.58400 0.02400 295.60800 ;
    END
  END wdata[473]
  PIN wdata[474]
    DIRECTION INPUT ;
    USE SIGNAL ;
    PORT
      LAYER M4 ;
      RECT 0.00000 295.87200 0.02400 295.89600 ;
    END
  END wdata[474]
  PIN wdata[475]
    DIRECTION INPUT ;
    USE SIGNAL ;
    PORT
      LAYER M4 ;
      RECT 0.00000 296.16000 0.02400 296.18400 ;
    END
  END wdata[475]
  PIN wdata[476]
    DIRECTION INPUT ;
    USE SIGNAL ;
    PORT
      LAYER M4 ;
      RECT 0.00000 296.44800 0.02400 296.47200 ;
    END
  END wdata[476]
  PIN wdata[477]
    DIRECTION INPUT ;
    USE SIGNAL ;
    PORT
      LAYER M4 ;
      RECT 0.00000 296.73600 0.02400 296.76000 ;
    END
  END wdata[477]
  PIN wdata[478]
    DIRECTION INPUT ;
    USE SIGNAL ;
    PORT
      LAYER M4 ;
      RECT 0.00000 297.02400 0.02400 297.04800 ;
    END
  END wdata[478]
  PIN wdata[479]
    DIRECTION INPUT ;
    USE SIGNAL ;
    PORT
      LAYER M4 ;
      RECT 0.00000 297.31200 0.02400 297.33600 ;
    END
  END wdata[479]
  PIN wdata[480]
    DIRECTION INPUT ;
    USE SIGNAL ;
    PORT
      LAYER M4 ;
      RECT 0.00000 297.60000 0.02400 297.62400 ;
    END
  END wdata[480]
  PIN wdata[481]
    DIRECTION INPUT ;
    USE SIGNAL ;
    PORT
      LAYER M4 ;
      RECT 0.00000 297.88800 0.02400 297.91200 ;
    END
  END wdata[481]
  PIN wdata[482]
    DIRECTION INPUT ;
    USE SIGNAL ;
    PORT
      LAYER M4 ;
      RECT 0.00000 298.17600 0.02400 298.20000 ;
    END
  END wdata[482]
  PIN wdata[483]
    DIRECTION INPUT ;
    USE SIGNAL ;
    PORT
      LAYER M4 ;
      RECT 0.00000 298.46400 0.02400 298.48800 ;
    END
  END wdata[483]
  PIN wdata[484]
    DIRECTION INPUT ;
    USE SIGNAL ;
    PORT
      LAYER M4 ;
      RECT 0.00000 298.75200 0.02400 298.77600 ;
    END
  END wdata[484]
  PIN wdata[485]
    DIRECTION INPUT ;
    USE SIGNAL ;
    PORT
      LAYER M4 ;
      RECT 0.00000 299.04000 0.02400 299.06400 ;
    END
  END wdata[485]
  PIN wdata[486]
    DIRECTION INPUT ;
    USE SIGNAL ;
    PORT
      LAYER M4 ;
      RECT 0.00000 299.32800 0.02400 299.35200 ;
    END
  END wdata[486]
  PIN wdata[487]
    DIRECTION INPUT ;
    USE SIGNAL ;
    PORT
      LAYER M4 ;
      RECT 0.00000 299.61600 0.02400 299.64000 ;
    END
  END wdata[487]
  PIN wdata[488]
    DIRECTION INPUT ;
    USE SIGNAL ;
    PORT
      LAYER M4 ;
      RECT 0.00000 299.90400 0.02400 299.92800 ;
    END
  END wdata[488]
  PIN wdata[489]
    DIRECTION INPUT ;
    USE SIGNAL ;
    PORT
      LAYER M4 ;
      RECT 0.00000 300.19200 0.02400 300.21600 ;
    END
  END wdata[489]
  PIN wdata[490]
    DIRECTION INPUT ;
    USE SIGNAL ;
    PORT
      LAYER M4 ;
      RECT 0.00000 300.48000 0.02400 300.50400 ;
    END
  END wdata[490]
  PIN wdata[491]
    DIRECTION INPUT ;
    USE SIGNAL ;
    PORT
      LAYER M4 ;
      RECT 0.00000 300.76800 0.02400 300.79200 ;
    END
  END wdata[491]
  PIN wdata[492]
    DIRECTION INPUT ;
    USE SIGNAL ;
    PORT
      LAYER M4 ;
      RECT 0.00000 301.05600 0.02400 301.08000 ;
    END
  END wdata[492]
  PIN wdata[493]
    DIRECTION INPUT ;
    USE SIGNAL ;
    PORT
      LAYER M4 ;
      RECT 0.00000 301.34400 0.02400 301.36800 ;
    END
  END wdata[493]
  PIN wdata[494]
    DIRECTION INPUT ;
    USE SIGNAL ;
    PORT
      LAYER M4 ;
      RECT 0.00000 301.63200 0.02400 301.65600 ;
    END
  END wdata[494]
  PIN wdata[495]
    DIRECTION INPUT ;
    USE SIGNAL ;
    PORT
      LAYER M4 ;
      RECT 0.00000 301.92000 0.02400 301.94400 ;
    END
  END wdata[495]
  PIN wdata[496]
    DIRECTION INPUT ;
    USE SIGNAL ;
    PORT
      LAYER M4 ;
      RECT 0.00000 302.20800 0.02400 302.23200 ;
    END
  END wdata[496]
  PIN wdata[497]
    DIRECTION INPUT ;
    USE SIGNAL ;
    PORT
      LAYER M4 ;
      RECT 0.00000 302.49600 0.02400 302.52000 ;
    END
  END wdata[497]
  PIN wdata[498]
    DIRECTION INPUT ;
    USE SIGNAL ;
    PORT
      LAYER M4 ;
      RECT 0.00000 302.78400 0.02400 302.80800 ;
    END
  END wdata[498]
  PIN wdata[499]
    DIRECTION INPUT ;
    USE SIGNAL ;
    PORT
      LAYER M4 ;
      RECT 0.00000 303.07200 0.02400 303.09600 ;
    END
  END wdata[499]
  PIN wdata[500]
    DIRECTION INPUT ;
    USE SIGNAL ;
    PORT
      LAYER M4 ;
      RECT 0.00000 303.36000 0.02400 303.38400 ;
    END
  END wdata[500]
  PIN wdata[501]
    DIRECTION INPUT ;
    USE SIGNAL ;
    PORT
      LAYER M4 ;
      RECT 0.00000 303.64800 0.02400 303.67200 ;
    END
  END wdata[501]
  PIN wdata[502]
    DIRECTION INPUT ;
    USE SIGNAL ;
    PORT
      LAYER M4 ;
      RECT 0.00000 303.93600 0.02400 303.96000 ;
    END
  END wdata[502]
  PIN wdata[503]
    DIRECTION INPUT ;
    USE SIGNAL ;
    PORT
      LAYER M4 ;
      RECT 0.00000 304.22400 0.02400 304.24800 ;
    END
  END wdata[503]
  PIN wdata[504]
    DIRECTION INPUT ;
    USE SIGNAL ;
    PORT
      LAYER M4 ;
      RECT 0.00000 304.51200 0.02400 304.53600 ;
    END
  END wdata[504]
  PIN wdata[505]
    DIRECTION INPUT ;
    USE SIGNAL ;
    PORT
      LAYER M4 ;
      RECT 0.00000 304.80000 0.02400 304.82400 ;
    END
  END wdata[505]
  PIN wdata[506]
    DIRECTION INPUT ;
    USE SIGNAL ;
    PORT
      LAYER M4 ;
      RECT 0.00000 305.08800 0.02400 305.11200 ;
    END
  END wdata[506]
  PIN wdata[507]
    DIRECTION INPUT ;
    USE SIGNAL ;
    PORT
      LAYER M4 ;
      RECT 0.00000 305.37600 0.02400 305.40000 ;
    END
  END wdata[507]
  PIN wdata[508]
    DIRECTION INPUT ;
    USE SIGNAL ;
    PORT
      LAYER M4 ;
      RECT 0.00000 305.66400 0.02400 305.68800 ;
    END
  END wdata[508]
  PIN wdata[509]
    DIRECTION INPUT ;
    USE SIGNAL ;
    PORT
      LAYER M4 ;
      RECT 0.00000 305.95200 0.02400 305.97600 ;
    END
  END wdata[509]
  PIN wdata[510]
    DIRECTION INPUT ;
    USE SIGNAL ;
    PORT
      LAYER M4 ;
      RECT 0.00000 306.24000 0.02400 306.26400 ;
    END
  END wdata[510]
  PIN wdata[511]
    DIRECTION INPUT ;
    USE SIGNAL ;
    PORT
      LAYER M4 ;
      RECT 0.00000 306.52800 0.02400 306.55200 ;
    END
  END wdata[511]
  PIN waddr[0]
    DIRECTION INPUT ;
    USE SIGNAL ;
    PORT
      LAYER M4 ;
      RECT 0.00000 315.79200 0.02400 315.81600 ;
    END
  END waddr[0]
  PIN waddr[1]
    DIRECTION INPUT ;
    USE SIGNAL ;
    PORT
      LAYER M4 ;
      RECT 0.00000 316.08000 0.02400 316.10400 ;
    END
  END waddr[1]
  PIN waddr[2]
    DIRECTION INPUT ;
    USE SIGNAL ;
    PORT
      LAYER M4 ;
      RECT 0.00000 316.36800 0.02400 316.39200 ;
    END
  END waddr[2]
  PIN waddr[3]
    DIRECTION INPUT ;
    USE SIGNAL ;
    PORT
      LAYER M4 ;
      RECT 0.00000 316.65600 0.02400 316.68000 ;
    END
  END waddr[3]
  PIN waddr[4]
    DIRECTION INPUT ;
    USE SIGNAL ;
    PORT
      LAYER M4 ;
      RECT 0.00000 316.94400 0.02400 316.96800 ;
    END
  END waddr[4]
  PIN waddr[5]
    DIRECTION INPUT ;
    USE SIGNAL ;
    PORT
      LAYER M4 ;
      RECT 0.00000 317.23200 0.02400 317.25600 ;
    END
  END waddr[5]
  PIN waddr[6]
    DIRECTION INPUT ;
    USE SIGNAL ;
    PORT
      LAYER M4 ;
      RECT 0.00000 317.52000 0.02400 317.54400 ;
    END
  END waddr[6]
  PIN waddr[7]
    DIRECTION INPUT ;
    USE SIGNAL ;
    PORT
      LAYER M4 ;
      RECT 0.00000 317.80800 0.02400 317.83200 ;
    END
  END waddr[7]
  PIN waddr[8]
    DIRECTION INPUT ;
    USE SIGNAL ;
    PORT
      LAYER M4 ;
      RECT 0.00000 318.09600 0.02400 318.12000 ;
    END
  END waddr[8]
  PIN waddr[9]
    DIRECTION INPUT ;
    USE SIGNAL ;
    PORT
      LAYER M4 ;
      RECT 0.00000 318.38400 0.02400 318.40800 ;
    END
  END waddr[9]
  PIN rb_data[0]
    DIRECTION OUTPUT ;
    USE SIGNAL ;
    PORT
      LAYER M4 ;
      RECT 0.00000 0.04800 0.02400 0.07200 ;
    END
  END rb_data[0]
  PIN rb_data[1]
    DIRECTION OUTPUT ;
    USE SIGNAL ;
    PORT
      LAYER M4 ;
      RECT 0.00000 0.33600 0.02400 0.36000 ;
    END
  END rb_data[1]
  PIN rb_data[2]
    DIRECTION OUTPUT ;
    USE SIGNAL ;
    PORT
      LAYER M4 ;
      RECT 0.00000 0.62400 0.02400 0.64800 ;
    END
  END rb_data[2]
  PIN rb_data[3]
    DIRECTION OUTPUT ;
    USE SIGNAL ;
    PORT
      LAYER M4 ;
      RECT 0.00000 0.91200 0.02400 0.93600 ;
    END
  END rb_data[3]
  PIN rb_data[4]
    DIRECTION OUTPUT ;
    USE SIGNAL ;
    PORT
      LAYER M4 ;
      RECT 0.00000 1.20000 0.02400 1.22400 ;
    END
  END rb_data[4]
  PIN rb_data[5]
    DIRECTION OUTPUT ;
    USE SIGNAL ;
    PORT
      LAYER M4 ;
      RECT 0.00000 1.48800 0.02400 1.51200 ;
    END
  END rb_data[5]
  PIN rb_data[6]
    DIRECTION OUTPUT ;
    USE SIGNAL ;
    PORT
      LAYER M4 ;
      RECT 0.00000 1.77600 0.02400 1.80000 ;
    END
  END rb_data[6]
  PIN rb_data[7]
    DIRECTION OUTPUT ;
    USE SIGNAL ;
    PORT
      LAYER M4 ;
      RECT 0.00000 2.06400 0.02400 2.08800 ;
    END
  END rb_data[7]
  PIN rb_data[8]
    DIRECTION OUTPUT ;
    USE SIGNAL ;
    PORT
      LAYER M4 ;
      RECT 0.00000 2.35200 0.02400 2.37600 ;
    END
  END rb_data[8]
  PIN rb_data[9]
    DIRECTION OUTPUT ;
    USE SIGNAL ;
    PORT
      LAYER M4 ;
      RECT 0.00000 2.64000 0.02400 2.66400 ;
    END
  END rb_data[9]
  PIN rb_data[10]
    DIRECTION OUTPUT ;
    USE SIGNAL ;
    PORT
      LAYER M4 ;
      RECT 0.00000 2.92800 0.02400 2.95200 ;
    END
  END rb_data[10]
  PIN rb_data[11]
    DIRECTION OUTPUT ;
    USE SIGNAL ;
    PORT
      LAYER M4 ;
      RECT 0.00000 3.21600 0.02400 3.24000 ;
    END
  END rb_data[11]
  PIN rb_data[12]
    DIRECTION OUTPUT ;
    USE SIGNAL ;
    PORT
      LAYER M4 ;
      RECT 0.00000 3.50400 0.02400 3.52800 ;
    END
  END rb_data[12]
  PIN rb_data[13]
    DIRECTION OUTPUT ;
    USE SIGNAL ;
    PORT
      LAYER M4 ;
      RECT 0.00000 3.79200 0.02400 3.81600 ;
    END
  END rb_data[13]
  PIN rb_data[14]
    DIRECTION OUTPUT ;
    USE SIGNAL ;
    PORT
      LAYER M4 ;
      RECT 0.00000 4.08000 0.02400 4.10400 ;
    END
  END rb_data[14]
  PIN rb_data[15]
    DIRECTION OUTPUT ;
    USE SIGNAL ;
    PORT
      LAYER M4 ;
      RECT 0.00000 4.36800 0.02400 4.39200 ;
    END
  END rb_data[15]
  PIN rb_data[16]
    DIRECTION OUTPUT ;
    USE SIGNAL ;
    PORT
      LAYER M4 ;
      RECT 0.00000 4.65600 0.02400 4.68000 ;
    END
  END rb_data[16]
  PIN rb_data[17]
    DIRECTION OUTPUT ;
    USE SIGNAL ;
    PORT
      LAYER M4 ;
      RECT 0.00000 4.94400 0.02400 4.96800 ;
    END
  END rb_data[17]
  PIN rb_data[18]
    DIRECTION OUTPUT ;
    USE SIGNAL ;
    PORT
      LAYER M4 ;
      RECT 0.00000 5.23200 0.02400 5.25600 ;
    END
  END rb_data[18]
  PIN rb_data[19]
    DIRECTION OUTPUT ;
    USE SIGNAL ;
    PORT
      LAYER M4 ;
      RECT 0.00000 5.52000 0.02400 5.54400 ;
    END
  END rb_data[19]
  PIN rb_data[20]
    DIRECTION OUTPUT ;
    USE SIGNAL ;
    PORT
      LAYER M4 ;
      RECT 0.00000 5.80800 0.02400 5.83200 ;
    END
  END rb_data[20]
  PIN rb_data[21]
    DIRECTION OUTPUT ;
    USE SIGNAL ;
    PORT
      LAYER M4 ;
      RECT 0.00000 6.09600 0.02400 6.12000 ;
    END
  END rb_data[21]
  PIN rb_data[22]
    DIRECTION OUTPUT ;
    USE SIGNAL ;
    PORT
      LAYER M4 ;
      RECT 0.00000 6.38400 0.02400 6.40800 ;
    END
  END rb_data[22]
  PIN rb_data[23]
    DIRECTION OUTPUT ;
    USE SIGNAL ;
    PORT
      LAYER M4 ;
      RECT 0.00000 6.67200 0.02400 6.69600 ;
    END
  END rb_data[23]
  PIN rb_data[24]
    DIRECTION OUTPUT ;
    USE SIGNAL ;
    PORT
      LAYER M4 ;
      RECT 0.00000 6.96000 0.02400 6.98400 ;
    END
  END rb_data[24]
  PIN rb_data[25]
    DIRECTION OUTPUT ;
    USE SIGNAL ;
    PORT
      LAYER M4 ;
      RECT 0.00000 7.24800 0.02400 7.27200 ;
    END
  END rb_data[25]
  PIN rb_data[26]
    DIRECTION OUTPUT ;
    USE SIGNAL ;
    PORT
      LAYER M4 ;
      RECT 0.00000 7.53600 0.02400 7.56000 ;
    END
  END rb_data[26]
  PIN rb_data[27]
    DIRECTION OUTPUT ;
    USE SIGNAL ;
    PORT
      LAYER M4 ;
      RECT 0.00000 7.82400 0.02400 7.84800 ;
    END
  END rb_data[27]
  PIN rb_data[28]
    DIRECTION OUTPUT ;
    USE SIGNAL ;
    PORT
      LAYER M4 ;
      RECT 0.00000 8.11200 0.02400 8.13600 ;
    END
  END rb_data[28]
  PIN rb_data[29]
    DIRECTION OUTPUT ;
    USE SIGNAL ;
    PORT
      LAYER M4 ;
      RECT 0.00000 8.40000 0.02400 8.42400 ;
    END
  END rb_data[29]
  PIN rb_data[30]
    DIRECTION OUTPUT ;
    USE SIGNAL ;
    PORT
      LAYER M4 ;
      RECT 0.00000 8.68800 0.02400 8.71200 ;
    END
  END rb_data[30]
  PIN rb_data[31]
    DIRECTION OUTPUT ;
    USE SIGNAL ;
    PORT
      LAYER M4 ;
      RECT 0.00000 8.97600 0.02400 9.00000 ;
    END
  END rb_data[31]
  PIN rb_data[32]
    DIRECTION OUTPUT ;
    USE SIGNAL ;
    PORT
      LAYER M4 ;
      RECT 0.00000 9.26400 0.02400 9.28800 ;
    END
  END rb_data[32]
  PIN rb_data[33]
    DIRECTION OUTPUT ;
    USE SIGNAL ;
    PORT
      LAYER M4 ;
      RECT 0.00000 9.55200 0.02400 9.57600 ;
    END
  END rb_data[33]
  PIN rb_data[34]
    DIRECTION OUTPUT ;
    USE SIGNAL ;
    PORT
      LAYER M4 ;
      RECT 0.00000 9.84000 0.02400 9.86400 ;
    END
  END rb_data[34]
  PIN rb_data[35]
    DIRECTION OUTPUT ;
    USE SIGNAL ;
    PORT
      LAYER M4 ;
      RECT 0.00000 10.12800 0.02400 10.15200 ;
    END
  END rb_data[35]
  PIN rb_data[36]
    DIRECTION OUTPUT ;
    USE SIGNAL ;
    PORT
      LAYER M4 ;
      RECT 0.00000 10.41600 0.02400 10.44000 ;
    END
  END rb_data[36]
  PIN rb_data[37]
    DIRECTION OUTPUT ;
    USE SIGNAL ;
    PORT
      LAYER M4 ;
      RECT 0.00000 10.70400 0.02400 10.72800 ;
    END
  END rb_data[37]
  PIN rb_data[38]
    DIRECTION OUTPUT ;
    USE SIGNAL ;
    PORT
      LAYER M4 ;
      RECT 0.00000 10.99200 0.02400 11.01600 ;
    END
  END rb_data[38]
  PIN rb_data[39]
    DIRECTION OUTPUT ;
    USE SIGNAL ;
    PORT
      LAYER M4 ;
      RECT 0.00000 11.28000 0.02400 11.30400 ;
    END
  END rb_data[39]
  PIN rb_data[40]
    DIRECTION OUTPUT ;
    USE SIGNAL ;
    PORT
      LAYER M4 ;
      RECT 0.00000 11.56800 0.02400 11.59200 ;
    END
  END rb_data[40]
  PIN rb_data[41]
    DIRECTION OUTPUT ;
    USE SIGNAL ;
    PORT
      LAYER M4 ;
      RECT 0.00000 11.85600 0.02400 11.88000 ;
    END
  END rb_data[41]
  PIN rb_data[42]
    DIRECTION OUTPUT ;
    USE SIGNAL ;
    PORT
      LAYER M4 ;
      RECT 0.00000 12.14400 0.02400 12.16800 ;
    END
  END rb_data[42]
  PIN rb_data[43]
    DIRECTION OUTPUT ;
    USE SIGNAL ;
    PORT
      LAYER M4 ;
      RECT 0.00000 12.43200 0.02400 12.45600 ;
    END
  END rb_data[43]
  PIN rb_data[44]
    DIRECTION OUTPUT ;
    USE SIGNAL ;
    PORT
      LAYER M4 ;
      RECT 0.00000 12.72000 0.02400 12.74400 ;
    END
  END rb_data[44]
  PIN rb_data[45]
    DIRECTION OUTPUT ;
    USE SIGNAL ;
    PORT
      LAYER M4 ;
      RECT 0.00000 13.00800 0.02400 13.03200 ;
    END
  END rb_data[45]
  PIN rb_data[46]
    DIRECTION OUTPUT ;
    USE SIGNAL ;
    PORT
      LAYER M4 ;
      RECT 0.00000 13.29600 0.02400 13.32000 ;
    END
  END rb_data[46]
  PIN rb_data[47]
    DIRECTION OUTPUT ;
    USE SIGNAL ;
    PORT
      LAYER M4 ;
      RECT 0.00000 13.58400 0.02400 13.60800 ;
    END
  END rb_data[47]
  PIN rb_data[48]
    DIRECTION OUTPUT ;
    USE SIGNAL ;
    PORT
      LAYER M4 ;
      RECT 0.00000 13.87200 0.02400 13.89600 ;
    END
  END rb_data[48]
  PIN rb_data[49]
    DIRECTION OUTPUT ;
    USE SIGNAL ;
    PORT
      LAYER M4 ;
      RECT 0.00000 14.16000 0.02400 14.18400 ;
    END
  END rb_data[49]
  PIN rb_data[50]
    DIRECTION OUTPUT ;
    USE SIGNAL ;
    PORT
      LAYER M4 ;
      RECT 0.00000 14.44800 0.02400 14.47200 ;
    END
  END rb_data[50]
  PIN rb_data[51]
    DIRECTION OUTPUT ;
    USE SIGNAL ;
    PORT
      LAYER M4 ;
      RECT 0.00000 14.73600 0.02400 14.76000 ;
    END
  END rb_data[51]
  PIN rb_data[52]
    DIRECTION OUTPUT ;
    USE SIGNAL ;
    PORT
      LAYER M4 ;
      RECT 0.00000 15.02400 0.02400 15.04800 ;
    END
  END rb_data[52]
  PIN rb_data[53]
    DIRECTION OUTPUT ;
    USE SIGNAL ;
    PORT
      LAYER M4 ;
      RECT 0.00000 15.31200 0.02400 15.33600 ;
    END
  END rb_data[53]
  PIN rb_data[54]
    DIRECTION OUTPUT ;
    USE SIGNAL ;
    PORT
      LAYER M4 ;
      RECT 0.00000 15.60000 0.02400 15.62400 ;
    END
  END rb_data[54]
  PIN rb_data[55]
    DIRECTION OUTPUT ;
    USE SIGNAL ;
    PORT
      LAYER M4 ;
      RECT 0.00000 15.88800 0.02400 15.91200 ;
    END
  END rb_data[55]
  PIN rb_data[56]
    DIRECTION OUTPUT ;
    USE SIGNAL ;
    PORT
      LAYER M4 ;
      RECT 0.00000 16.17600 0.02400 16.20000 ;
    END
  END rb_data[56]
  PIN rb_data[57]
    DIRECTION OUTPUT ;
    USE SIGNAL ;
    PORT
      LAYER M4 ;
      RECT 0.00000 16.46400 0.02400 16.48800 ;
    END
  END rb_data[57]
  PIN rb_data[58]
    DIRECTION OUTPUT ;
    USE SIGNAL ;
    PORT
      LAYER M4 ;
      RECT 0.00000 16.75200 0.02400 16.77600 ;
    END
  END rb_data[58]
  PIN rb_data[59]
    DIRECTION OUTPUT ;
    USE SIGNAL ;
    PORT
      LAYER M4 ;
      RECT 0.00000 17.04000 0.02400 17.06400 ;
    END
  END rb_data[59]
  PIN rb_data[60]
    DIRECTION OUTPUT ;
    USE SIGNAL ;
    PORT
      LAYER M4 ;
      RECT 0.00000 17.32800 0.02400 17.35200 ;
    END
  END rb_data[60]
  PIN rb_data[61]
    DIRECTION OUTPUT ;
    USE SIGNAL ;
    PORT
      LAYER M4 ;
      RECT 0.00000 17.61600 0.02400 17.64000 ;
    END
  END rb_data[61]
  PIN rb_data[62]
    DIRECTION OUTPUT ;
    USE SIGNAL ;
    PORT
      LAYER M4 ;
      RECT 0.00000 17.90400 0.02400 17.92800 ;
    END
  END rb_data[62]
  PIN rb_data[63]
    DIRECTION OUTPUT ;
    USE SIGNAL ;
    PORT
      LAYER M4 ;
      RECT 0.00000 18.19200 0.02400 18.21600 ;
    END
  END rb_data[63]
  PIN rb_data[64]
    DIRECTION OUTPUT ;
    USE SIGNAL ;
    PORT
      LAYER M4 ;
      RECT 0.00000 18.48000 0.02400 18.50400 ;
    END
  END rb_data[64]
  PIN rb_data[65]
    DIRECTION OUTPUT ;
    USE SIGNAL ;
    PORT
      LAYER M4 ;
      RECT 0.00000 18.76800 0.02400 18.79200 ;
    END
  END rb_data[65]
  PIN rb_data[66]
    DIRECTION OUTPUT ;
    USE SIGNAL ;
    PORT
      LAYER M4 ;
      RECT 0.00000 19.05600 0.02400 19.08000 ;
    END
  END rb_data[66]
  PIN rb_data[67]
    DIRECTION OUTPUT ;
    USE SIGNAL ;
    PORT
      LAYER M4 ;
      RECT 0.00000 19.34400 0.02400 19.36800 ;
    END
  END rb_data[67]
  PIN rb_data[68]
    DIRECTION OUTPUT ;
    USE SIGNAL ;
    PORT
      LAYER M4 ;
      RECT 0.00000 19.63200 0.02400 19.65600 ;
    END
  END rb_data[68]
  PIN rb_data[69]
    DIRECTION OUTPUT ;
    USE SIGNAL ;
    PORT
      LAYER M4 ;
      RECT 0.00000 19.92000 0.02400 19.94400 ;
    END
  END rb_data[69]
  PIN rb_data[70]
    DIRECTION OUTPUT ;
    USE SIGNAL ;
    PORT
      LAYER M4 ;
      RECT 0.00000 20.20800 0.02400 20.23200 ;
    END
  END rb_data[70]
  PIN rb_data[71]
    DIRECTION OUTPUT ;
    USE SIGNAL ;
    PORT
      LAYER M4 ;
      RECT 0.00000 20.49600 0.02400 20.52000 ;
    END
  END rb_data[71]
  PIN rb_data[72]
    DIRECTION OUTPUT ;
    USE SIGNAL ;
    PORT
      LAYER M4 ;
      RECT 0.00000 20.78400 0.02400 20.80800 ;
    END
  END rb_data[72]
  PIN rb_data[73]
    DIRECTION OUTPUT ;
    USE SIGNAL ;
    PORT
      LAYER M4 ;
      RECT 0.00000 21.07200 0.02400 21.09600 ;
    END
  END rb_data[73]
  PIN rb_data[74]
    DIRECTION OUTPUT ;
    USE SIGNAL ;
    PORT
      LAYER M4 ;
      RECT 0.00000 21.36000 0.02400 21.38400 ;
    END
  END rb_data[74]
  PIN rb_data[75]
    DIRECTION OUTPUT ;
    USE SIGNAL ;
    PORT
      LAYER M4 ;
      RECT 0.00000 21.64800 0.02400 21.67200 ;
    END
  END rb_data[75]
  PIN rb_data[76]
    DIRECTION OUTPUT ;
    USE SIGNAL ;
    PORT
      LAYER M4 ;
      RECT 0.00000 21.93600 0.02400 21.96000 ;
    END
  END rb_data[76]
  PIN rb_data[77]
    DIRECTION OUTPUT ;
    USE SIGNAL ;
    PORT
      LAYER M4 ;
      RECT 0.00000 22.22400 0.02400 22.24800 ;
    END
  END rb_data[77]
  PIN rb_data[78]
    DIRECTION OUTPUT ;
    USE SIGNAL ;
    PORT
      LAYER M4 ;
      RECT 0.00000 22.51200 0.02400 22.53600 ;
    END
  END rb_data[78]
  PIN rb_data[79]
    DIRECTION OUTPUT ;
    USE SIGNAL ;
    PORT
      LAYER M4 ;
      RECT 0.00000 22.80000 0.02400 22.82400 ;
    END
  END rb_data[79]
  PIN rb_data[80]
    DIRECTION OUTPUT ;
    USE SIGNAL ;
    PORT
      LAYER M4 ;
      RECT 0.00000 23.08800 0.02400 23.11200 ;
    END
  END rb_data[80]
  PIN rb_data[81]
    DIRECTION OUTPUT ;
    USE SIGNAL ;
    PORT
      LAYER M4 ;
      RECT 0.00000 23.37600 0.02400 23.40000 ;
    END
  END rb_data[81]
  PIN rb_data[82]
    DIRECTION OUTPUT ;
    USE SIGNAL ;
    PORT
      LAYER M4 ;
      RECT 0.00000 23.66400 0.02400 23.68800 ;
    END
  END rb_data[82]
  PIN rb_data[83]
    DIRECTION OUTPUT ;
    USE SIGNAL ;
    PORT
      LAYER M4 ;
      RECT 0.00000 23.95200 0.02400 23.97600 ;
    END
  END rb_data[83]
  PIN rb_data[84]
    DIRECTION OUTPUT ;
    USE SIGNAL ;
    PORT
      LAYER M4 ;
      RECT 0.00000 24.24000 0.02400 24.26400 ;
    END
  END rb_data[84]
  PIN rb_data[85]
    DIRECTION OUTPUT ;
    USE SIGNAL ;
    PORT
      LAYER M4 ;
      RECT 0.00000 24.52800 0.02400 24.55200 ;
    END
  END rb_data[85]
  PIN rb_data[86]
    DIRECTION OUTPUT ;
    USE SIGNAL ;
    PORT
      LAYER M4 ;
      RECT 0.00000 24.81600 0.02400 24.84000 ;
    END
  END rb_data[86]
  PIN rb_data[87]
    DIRECTION OUTPUT ;
    USE SIGNAL ;
    PORT
      LAYER M4 ;
      RECT 0.00000 25.10400 0.02400 25.12800 ;
    END
  END rb_data[87]
  PIN rb_data[88]
    DIRECTION OUTPUT ;
    USE SIGNAL ;
    PORT
      LAYER M4 ;
      RECT 0.00000 25.39200 0.02400 25.41600 ;
    END
  END rb_data[88]
  PIN rb_data[89]
    DIRECTION OUTPUT ;
    USE SIGNAL ;
    PORT
      LAYER M4 ;
      RECT 0.00000 25.68000 0.02400 25.70400 ;
    END
  END rb_data[89]
  PIN rb_data[90]
    DIRECTION OUTPUT ;
    USE SIGNAL ;
    PORT
      LAYER M4 ;
      RECT 0.00000 25.96800 0.02400 25.99200 ;
    END
  END rb_data[90]
  PIN rb_data[91]
    DIRECTION OUTPUT ;
    USE SIGNAL ;
    PORT
      LAYER M4 ;
      RECT 0.00000 26.25600 0.02400 26.28000 ;
    END
  END rb_data[91]
  PIN rb_data[92]
    DIRECTION OUTPUT ;
    USE SIGNAL ;
    PORT
      LAYER M4 ;
      RECT 0.00000 26.54400 0.02400 26.56800 ;
    END
  END rb_data[92]
  PIN rb_data[93]
    DIRECTION OUTPUT ;
    USE SIGNAL ;
    PORT
      LAYER M4 ;
      RECT 0.00000 26.83200 0.02400 26.85600 ;
    END
  END rb_data[93]
  PIN rb_data[94]
    DIRECTION OUTPUT ;
    USE SIGNAL ;
    PORT
      LAYER M4 ;
      RECT 0.00000 27.12000 0.02400 27.14400 ;
    END
  END rb_data[94]
  PIN rb_data[95]
    DIRECTION OUTPUT ;
    USE SIGNAL ;
    PORT
      LAYER M4 ;
      RECT 0.00000 27.40800 0.02400 27.43200 ;
    END
  END rb_data[95]
  PIN rb_data[96]
    DIRECTION OUTPUT ;
    USE SIGNAL ;
    PORT
      LAYER M4 ;
      RECT 0.00000 27.69600 0.02400 27.72000 ;
    END
  END rb_data[96]
  PIN rb_data[97]
    DIRECTION OUTPUT ;
    USE SIGNAL ;
    PORT
      LAYER M4 ;
      RECT 0.00000 27.98400 0.02400 28.00800 ;
    END
  END rb_data[97]
  PIN rb_data[98]
    DIRECTION OUTPUT ;
    USE SIGNAL ;
    PORT
      LAYER M4 ;
      RECT 0.00000 28.27200 0.02400 28.29600 ;
    END
  END rb_data[98]
  PIN rb_data[99]
    DIRECTION OUTPUT ;
    USE SIGNAL ;
    PORT
      LAYER M4 ;
      RECT 0.00000 28.56000 0.02400 28.58400 ;
    END
  END rb_data[99]
  PIN rb_data[100]
    DIRECTION OUTPUT ;
    USE SIGNAL ;
    PORT
      LAYER M4 ;
      RECT 0.00000 28.84800 0.02400 28.87200 ;
    END
  END rb_data[100]
  PIN rb_data[101]
    DIRECTION OUTPUT ;
    USE SIGNAL ;
    PORT
      LAYER M4 ;
      RECT 0.00000 29.13600 0.02400 29.16000 ;
    END
  END rb_data[101]
  PIN rb_data[102]
    DIRECTION OUTPUT ;
    USE SIGNAL ;
    PORT
      LAYER M4 ;
      RECT 0.00000 29.42400 0.02400 29.44800 ;
    END
  END rb_data[102]
  PIN rb_data[103]
    DIRECTION OUTPUT ;
    USE SIGNAL ;
    PORT
      LAYER M4 ;
      RECT 0.00000 29.71200 0.02400 29.73600 ;
    END
  END rb_data[103]
  PIN rb_data[104]
    DIRECTION OUTPUT ;
    USE SIGNAL ;
    PORT
      LAYER M4 ;
      RECT 0.00000 30.00000 0.02400 30.02400 ;
    END
  END rb_data[104]
  PIN rb_data[105]
    DIRECTION OUTPUT ;
    USE SIGNAL ;
    PORT
      LAYER M4 ;
      RECT 0.00000 30.28800 0.02400 30.31200 ;
    END
  END rb_data[105]
  PIN rb_data[106]
    DIRECTION OUTPUT ;
    USE SIGNAL ;
    PORT
      LAYER M4 ;
      RECT 0.00000 30.57600 0.02400 30.60000 ;
    END
  END rb_data[106]
  PIN rb_data[107]
    DIRECTION OUTPUT ;
    USE SIGNAL ;
    PORT
      LAYER M4 ;
      RECT 0.00000 30.86400 0.02400 30.88800 ;
    END
  END rb_data[107]
  PIN rb_data[108]
    DIRECTION OUTPUT ;
    USE SIGNAL ;
    PORT
      LAYER M4 ;
      RECT 0.00000 31.15200 0.02400 31.17600 ;
    END
  END rb_data[108]
  PIN rb_data[109]
    DIRECTION OUTPUT ;
    USE SIGNAL ;
    PORT
      LAYER M4 ;
      RECT 0.00000 31.44000 0.02400 31.46400 ;
    END
  END rb_data[109]
  PIN rb_data[110]
    DIRECTION OUTPUT ;
    USE SIGNAL ;
    PORT
      LAYER M4 ;
      RECT 0.00000 31.72800 0.02400 31.75200 ;
    END
  END rb_data[110]
  PIN rb_data[111]
    DIRECTION OUTPUT ;
    USE SIGNAL ;
    PORT
      LAYER M4 ;
      RECT 0.00000 32.01600 0.02400 32.04000 ;
    END
  END rb_data[111]
  PIN rb_data[112]
    DIRECTION OUTPUT ;
    USE SIGNAL ;
    PORT
      LAYER M4 ;
      RECT 0.00000 32.30400 0.02400 32.32800 ;
    END
  END rb_data[112]
  PIN rb_data[113]
    DIRECTION OUTPUT ;
    USE SIGNAL ;
    PORT
      LAYER M4 ;
      RECT 0.00000 32.59200 0.02400 32.61600 ;
    END
  END rb_data[113]
  PIN rb_data[114]
    DIRECTION OUTPUT ;
    USE SIGNAL ;
    PORT
      LAYER M4 ;
      RECT 0.00000 32.88000 0.02400 32.90400 ;
    END
  END rb_data[114]
  PIN rb_data[115]
    DIRECTION OUTPUT ;
    USE SIGNAL ;
    PORT
      LAYER M4 ;
      RECT 0.00000 33.16800 0.02400 33.19200 ;
    END
  END rb_data[115]
  PIN rb_data[116]
    DIRECTION OUTPUT ;
    USE SIGNAL ;
    PORT
      LAYER M4 ;
      RECT 0.00000 33.45600 0.02400 33.48000 ;
    END
  END rb_data[116]
  PIN rb_data[117]
    DIRECTION OUTPUT ;
    USE SIGNAL ;
    PORT
      LAYER M4 ;
      RECT 0.00000 33.74400 0.02400 33.76800 ;
    END
  END rb_data[117]
  PIN rb_data[118]
    DIRECTION OUTPUT ;
    USE SIGNAL ;
    PORT
      LAYER M4 ;
      RECT 0.00000 34.03200 0.02400 34.05600 ;
    END
  END rb_data[118]
  PIN rb_data[119]
    DIRECTION OUTPUT ;
    USE SIGNAL ;
    PORT
      LAYER M4 ;
      RECT 0.00000 34.32000 0.02400 34.34400 ;
    END
  END rb_data[119]
  PIN rb_data[120]
    DIRECTION OUTPUT ;
    USE SIGNAL ;
    PORT
      LAYER M4 ;
      RECT 0.00000 34.60800 0.02400 34.63200 ;
    END
  END rb_data[120]
  PIN rb_data[121]
    DIRECTION OUTPUT ;
    USE SIGNAL ;
    PORT
      LAYER M4 ;
      RECT 0.00000 34.89600 0.02400 34.92000 ;
    END
  END rb_data[121]
  PIN rb_data[122]
    DIRECTION OUTPUT ;
    USE SIGNAL ;
    PORT
      LAYER M4 ;
      RECT 0.00000 35.18400 0.02400 35.20800 ;
    END
  END rb_data[122]
  PIN rb_data[123]
    DIRECTION OUTPUT ;
    USE SIGNAL ;
    PORT
      LAYER M4 ;
      RECT 0.00000 35.47200 0.02400 35.49600 ;
    END
  END rb_data[123]
  PIN rb_data[124]
    DIRECTION OUTPUT ;
    USE SIGNAL ;
    PORT
      LAYER M4 ;
      RECT 0.00000 35.76000 0.02400 35.78400 ;
    END
  END rb_data[124]
  PIN rb_data[125]
    DIRECTION OUTPUT ;
    USE SIGNAL ;
    PORT
      LAYER M4 ;
      RECT 0.00000 36.04800 0.02400 36.07200 ;
    END
  END rb_data[125]
  PIN rb_data[126]
    DIRECTION OUTPUT ;
    USE SIGNAL ;
    PORT
      LAYER M4 ;
      RECT 0.00000 36.33600 0.02400 36.36000 ;
    END
  END rb_data[126]
  PIN rb_data[127]
    DIRECTION OUTPUT ;
    USE SIGNAL ;
    PORT
      LAYER M4 ;
      RECT 0.00000 36.62400 0.02400 36.64800 ;
    END
  END rb_data[127]
  PIN rb_data[128]
    DIRECTION OUTPUT ;
    USE SIGNAL ;
    PORT
      LAYER M4 ;
      RECT 0.00000 36.91200 0.02400 36.93600 ;
    END
  END rb_data[128]
  PIN rb_data[129]
    DIRECTION OUTPUT ;
    USE SIGNAL ;
    PORT
      LAYER M4 ;
      RECT 0.00000 37.20000 0.02400 37.22400 ;
    END
  END rb_data[129]
  PIN rb_data[130]
    DIRECTION OUTPUT ;
    USE SIGNAL ;
    PORT
      LAYER M4 ;
      RECT 0.00000 37.48800 0.02400 37.51200 ;
    END
  END rb_data[130]
  PIN rb_data[131]
    DIRECTION OUTPUT ;
    USE SIGNAL ;
    PORT
      LAYER M4 ;
      RECT 0.00000 37.77600 0.02400 37.80000 ;
    END
  END rb_data[131]
  PIN rb_data[132]
    DIRECTION OUTPUT ;
    USE SIGNAL ;
    PORT
      LAYER M4 ;
      RECT 0.00000 38.06400 0.02400 38.08800 ;
    END
  END rb_data[132]
  PIN rb_data[133]
    DIRECTION OUTPUT ;
    USE SIGNAL ;
    PORT
      LAYER M4 ;
      RECT 0.00000 38.35200 0.02400 38.37600 ;
    END
  END rb_data[133]
  PIN rb_data[134]
    DIRECTION OUTPUT ;
    USE SIGNAL ;
    PORT
      LAYER M4 ;
      RECT 0.00000 38.64000 0.02400 38.66400 ;
    END
  END rb_data[134]
  PIN rb_data[135]
    DIRECTION OUTPUT ;
    USE SIGNAL ;
    PORT
      LAYER M4 ;
      RECT 0.00000 38.92800 0.02400 38.95200 ;
    END
  END rb_data[135]
  PIN rb_data[136]
    DIRECTION OUTPUT ;
    USE SIGNAL ;
    PORT
      LAYER M4 ;
      RECT 0.00000 39.21600 0.02400 39.24000 ;
    END
  END rb_data[136]
  PIN rb_data[137]
    DIRECTION OUTPUT ;
    USE SIGNAL ;
    PORT
      LAYER M4 ;
      RECT 0.00000 39.50400 0.02400 39.52800 ;
    END
  END rb_data[137]
  PIN rb_data[138]
    DIRECTION OUTPUT ;
    USE SIGNAL ;
    PORT
      LAYER M4 ;
      RECT 0.00000 39.79200 0.02400 39.81600 ;
    END
  END rb_data[138]
  PIN rb_data[139]
    DIRECTION OUTPUT ;
    USE SIGNAL ;
    PORT
      LAYER M4 ;
      RECT 0.00000 40.08000 0.02400 40.10400 ;
    END
  END rb_data[139]
  PIN rb_data[140]
    DIRECTION OUTPUT ;
    USE SIGNAL ;
    PORT
      LAYER M4 ;
      RECT 0.00000 40.36800 0.02400 40.39200 ;
    END
  END rb_data[140]
  PIN rb_data[141]
    DIRECTION OUTPUT ;
    USE SIGNAL ;
    PORT
      LAYER M4 ;
      RECT 0.00000 40.65600 0.02400 40.68000 ;
    END
  END rb_data[141]
  PIN rb_data[142]
    DIRECTION OUTPUT ;
    USE SIGNAL ;
    PORT
      LAYER M4 ;
      RECT 0.00000 40.94400 0.02400 40.96800 ;
    END
  END rb_data[142]
  PIN rb_data[143]
    DIRECTION OUTPUT ;
    USE SIGNAL ;
    PORT
      LAYER M4 ;
      RECT 0.00000 41.23200 0.02400 41.25600 ;
    END
  END rb_data[143]
  PIN rb_data[144]
    DIRECTION OUTPUT ;
    USE SIGNAL ;
    PORT
      LAYER M4 ;
      RECT 0.00000 41.52000 0.02400 41.54400 ;
    END
  END rb_data[144]
  PIN rb_data[145]
    DIRECTION OUTPUT ;
    USE SIGNAL ;
    PORT
      LAYER M4 ;
      RECT 0.00000 41.80800 0.02400 41.83200 ;
    END
  END rb_data[145]
  PIN rb_data[146]
    DIRECTION OUTPUT ;
    USE SIGNAL ;
    PORT
      LAYER M4 ;
      RECT 0.00000 42.09600 0.02400 42.12000 ;
    END
  END rb_data[146]
  PIN rb_data[147]
    DIRECTION OUTPUT ;
    USE SIGNAL ;
    PORT
      LAYER M4 ;
      RECT 0.00000 42.38400 0.02400 42.40800 ;
    END
  END rb_data[147]
  PIN rb_data[148]
    DIRECTION OUTPUT ;
    USE SIGNAL ;
    PORT
      LAYER M4 ;
      RECT 0.00000 42.67200 0.02400 42.69600 ;
    END
  END rb_data[148]
  PIN rb_data[149]
    DIRECTION OUTPUT ;
    USE SIGNAL ;
    PORT
      LAYER M4 ;
      RECT 0.00000 42.96000 0.02400 42.98400 ;
    END
  END rb_data[149]
  PIN rb_data[150]
    DIRECTION OUTPUT ;
    USE SIGNAL ;
    PORT
      LAYER M4 ;
      RECT 0.00000 43.24800 0.02400 43.27200 ;
    END
  END rb_data[150]
  PIN rb_data[151]
    DIRECTION OUTPUT ;
    USE SIGNAL ;
    PORT
      LAYER M4 ;
      RECT 0.00000 43.53600 0.02400 43.56000 ;
    END
  END rb_data[151]
  PIN rb_data[152]
    DIRECTION OUTPUT ;
    USE SIGNAL ;
    PORT
      LAYER M4 ;
      RECT 0.00000 43.82400 0.02400 43.84800 ;
    END
  END rb_data[152]
  PIN rb_data[153]
    DIRECTION OUTPUT ;
    USE SIGNAL ;
    PORT
      LAYER M4 ;
      RECT 0.00000 44.11200 0.02400 44.13600 ;
    END
  END rb_data[153]
  PIN rb_data[154]
    DIRECTION OUTPUT ;
    USE SIGNAL ;
    PORT
      LAYER M4 ;
      RECT 0.00000 44.40000 0.02400 44.42400 ;
    END
  END rb_data[154]
  PIN rb_data[155]
    DIRECTION OUTPUT ;
    USE SIGNAL ;
    PORT
      LAYER M4 ;
      RECT 0.00000 44.68800 0.02400 44.71200 ;
    END
  END rb_data[155]
  PIN rb_data[156]
    DIRECTION OUTPUT ;
    USE SIGNAL ;
    PORT
      LAYER M4 ;
      RECT 0.00000 44.97600 0.02400 45.00000 ;
    END
  END rb_data[156]
  PIN rb_data[157]
    DIRECTION OUTPUT ;
    USE SIGNAL ;
    PORT
      LAYER M4 ;
      RECT 0.00000 45.26400 0.02400 45.28800 ;
    END
  END rb_data[157]
  PIN rb_data[158]
    DIRECTION OUTPUT ;
    USE SIGNAL ;
    PORT
      LAYER M4 ;
      RECT 0.00000 45.55200 0.02400 45.57600 ;
    END
  END rb_data[158]
  PIN rb_data[159]
    DIRECTION OUTPUT ;
    USE SIGNAL ;
    PORT
      LAYER M4 ;
      RECT 0.00000 45.84000 0.02400 45.86400 ;
    END
  END rb_data[159]
  PIN rb_data[160]
    DIRECTION OUTPUT ;
    USE SIGNAL ;
    PORT
      LAYER M4 ;
      RECT 0.00000 46.12800 0.02400 46.15200 ;
    END
  END rb_data[160]
  PIN rb_data[161]
    DIRECTION OUTPUT ;
    USE SIGNAL ;
    PORT
      LAYER M4 ;
      RECT 0.00000 46.41600 0.02400 46.44000 ;
    END
  END rb_data[161]
  PIN rb_data[162]
    DIRECTION OUTPUT ;
    USE SIGNAL ;
    PORT
      LAYER M4 ;
      RECT 0.00000 46.70400 0.02400 46.72800 ;
    END
  END rb_data[162]
  PIN rb_data[163]
    DIRECTION OUTPUT ;
    USE SIGNAL ;
    PORT
      LAYER M4 ;
      RECT 0.00000 46.99200 0.02400 47.01600 ;
    END
  END rb_data[163]
  PIN rb_data[164]
    DIRECTION OUTPUT ;
    USE SIGNAL ;
    PORT
      LAYER M4 ;
      RECT 0.00000 47.28000 0.02400 47.30400 ;
    END
  END rb_data[164]
  PIN rb_data[165]
    DIRECTION OUTPUT ;
    USE SIGNAL ;
    PORT
      LAYER M4 ;
      RECT 0.00000 47.56800 0.02400 47.59200 ;
    END
  END rb_data[165]
  PIN rb_data[166]
    DIRECTION OUTPUT ;
    USE SIGNAL ;
    PORT
      LAYER M4 ;
      RECT 0.00000 47.85600 0.02400 47.88000 ;
    END
  END rb_data[166]
  PIN rb_data[167]
    DIRECTION OUTPUT ;
    USE SIGNAL ;
    PORT
      LAYER M4 ;
      RECT 0.00000 48.14400 0.02400 48.16800 ;
    END
  END rb_data[167]
  PIN rb_data[168]
    DIRECTION OUTPUT ;
    USE SIGNAL ;
    PORT
      LAYER M4 ;
      RECT 0.00000 48.43200 0.02400 48.45600 ;
    END
  END rb_data[168]
  PIN rb_data[169]
    DIRECTION OUTPUT ;
    USE SIGNAL ;
    PORT
      LAYER M4 ;
      RECT 0.00000 48.72000 0.02400 48.74400 ;
    END
  END rb_data[169]
  PIN rb_data[170]
    DIRECTION OUTPUT ;
    USE SIGNAL ;
    PORT
      LAYER M4 ;
      RECT 0.00000 49.00800 0.02400 49.03200 ;
    END
  END rb_data[170]
  PIN rb_data[171]
    DIRECTION OUTPUT ;
    USE SIGNAL ;
    PORT
      LAYER M4 ;
      RECT 0.00000 49.29600 0.02400 49.32000 ;
    END
  END rb_data[171]
  PIN rb_data[172]
    DIRECTION OUTPUT ;
    USE SIGNAL ;
    PORT
      LAYER M4 ;
      RECT 0.00000 49.58400 0.02400 49.60800 ;
    END
  END rb_data[172]
  PIN rb_data[173]
    DIRECTION OUTPUT ;
    USE SIGNAL ;
    PORT
      LAYER M4 ;
      RECT 0.00000 49.87200 0.02400 49.89600 ;
    END
  END rb_data[173]
  PIN rb_data[174]
    DIRECTION OUTPUT ;
    USE SIGNAL ;
    PORT
      LAYER M4 ;
      RECT 0.00000 50.16000 0.02400 50.18400 ;
    END
  END rb_data[174]
  PIN rb_data[175]
    DIRECTION OUTPUT ;
    USE SIGNAL ;
    PORT
      LAYER M4 ;
      RECT 0.00000 50.44800 0.02400 50.47200 ;
    END
  END rb_data[175]
  PIN rb_data[176]
    DIRECTION OUTPUT ;
    USE SIGNAL ;
    PORT
      LAYER M4 ;
      RECT 0.00000 50.73600 0.02400 50.76000 ;
    END
  END rb_data[176]
  PIN rb_data[177]
    DIRECTION OUTPUT ;
    USE SIGNAL ;
    PORT
      LAYER M4 ;
      RECT 0.00000 51.02400 0.02400 51.04800 ;
    END
  END rb_data[177]
  PIN rb_data[178]
    DIRECTION OUTPUT ;
    USE SIGNAL ;
    PORT
      LAYER M4 ;
      RECT 0.00000 51.31200 0.02400 51.33600 ;
    END
  END rb_data[178]
  PIN rb_data[179]
    DIRECTION OUTPUT ;
    USE SIGNAL ;
    PORT
      LAYER M4 ;
      RECT 0.00000 51.60000 0.02400 51.62400 ;
    END
  END rb_data[179]
  PIN rb_data[180]
    DIRECTION OUTPUT ;
    USE SIGNAL ;
    PORT
      LAYER M4 ;
      RECT 0.00000 51.88800 0.02400 51.91200 ;
    END
  END rb_data[180]
  PIN rb_data[181]
    DIRECTION OUTPUT ;
    USE SIGNAL ;
    PORT
      LAYER M4 ;
      RECT 0.00000 52.17600 0.02400 52.20000 ;
    END
  END rb_data[181]
  PIN rb_data[182]
    DIRECTION OUTPUT ;
    USE SIGNAL ;
    PORT
      LAYER M4 ;
      RECT 0.00000 52.46400 0.02400 52.48800 ;
    END
  END rb_data[182]
  PIN rb_data[183]
    DIRECTION OUTPUT ;
    USE SIGNAL ;
    PORT
      LAYER M4 ;
      RECT 0.00000 52.75200 0.02400 52.77600 ;
    END
  END rb_data[183]
  PIN rb_data[184]
    DIRECTION OUTPUT ;
    USE SIGNAL ;
    PORT
      LAYER M4 ;
      RECT 0.00000 53.04000 0.02400 53.06400 ;
    END
  END rb_data[184]
  PIN rb_data[185]
    DIRECTION OUTPUT ;
    USE SIGNAL ;
    PORT
      LAYER M4 ;
      RECT 0.00000 53.32800 0.02400 53.35200 ;
    END
  END rb_data[185]
  PIN rb_data[186]
    DIRECTION OUTPUT ;
    USE SIGNAL ;
    PORT
      LAYER M4 ;
      RECT 0.00000 53.61600 0.02400 53.64000 ;
    END
  END rb_data[186]
  PIN rb_data[187]
    DIRECTION OUTPUT ;
    USE SIGNAL ;
    PORT
      LAYER M4 ;
      RECT 0.00000 53.90400 0.02400 53.92800 ;
    END
  END rb_data[187]
  PIN rb_data[188]
    DIRECTION OUTPUT ;
    USE SIGNAL ;
    PORT
      LAYER M4 ;
      RECT 0.00000 54.19200 0.02400 54.21600 ;
    END
  END rb_data[188]
  PIN rb_data[189]
    DIRECTION OUTPUT ;
    USE SIGNAL ;
    PORT
      LAYER M4 ;
      RECT 0.00000 54.48000 0.02400 54.50400 ;
    END
  END rb_data[189]
  PIN rb_data[190]
    DIRECTION OUTPUT ;
    USE SIGNAL ;
    PORT
      LAYER M4 ;
      RECT 0.00000 54.76800 0.02400 54.79200 ;
    END
  END rb_data[190]
  PIN rb_data[191]
    DIRECTION OUTPUT ;
    USE SIGNAL ;
    PORT
      LAYER M4 ;
      RECT 0.00000 55.05600 0.02400 55.08000 ;
    END
  END rb_data[191]
  PIN rb_data[192]
    DIRECTION OUTPUT ;
    USE SIGNAL ;
    PORT
      LAYER M4 ;
      RECT 0.00000 55.34400 0.02400 55.36800 ;
    END
  END rb_data[192]
  PIN rb_data[193]
    DIRECTION OUTPUT ;
    USE SIGNAL ;
    PORT
      LAYER M4 ;
      RECT 0.00000 55.63200 0.02400 55.65600 ;
    END
  END rb_data[193]
  PIN rb_data[194]
    DIRECTION OUTPUT ;
    USE SIGNAL ;
    PORT
      LAYER M4 ;
      RECT 0.00000 55.92000 0.02400 55.94400 ;
    END
  END rb_data[194]
  PIN rb_data[195]
    DIRECTION OUTPUT ;
    USE SIGNAL ;
    PORT
      LAYER M4 ;
      RECT 0.00000 56.20800 0.02400 56.23200 ;
    END
  END rb_data[195]
  PIN rb_data[196]
    DIRECTION OUTPUT ;
    USE SIGNAL ;
    PORT
      LAYER M4 ;
      RECT 0.00000 56.49600 0.02400 56.52000 ;
    END
  END rb_data[196]
  PIN rb_data[197]
    DIRECTION OUTPUT ;
    USE SIGNAL ;
    PORT
      LAYER M4 ;
      RECT 0.00000 56.78400 0.02400 56.80800 ;
    END
  END rb_data[197]
  PIN rb_data[198]
    DIRECTION OUTPUT ;
    USE SIGNAL ;
    PORT
      LAYER M4 ;
      RECT 0.00000 57.07200 0.02400 57.09600 ;
    END
  END rb_data[198]
  PIN rb_data[199]
    DIRECTION OUTPUT ;
    USE SIGNAL ;
    PORT
      LAYER M4 ;
      RECT 0.00000 57.36000 0.02400 57.38400 ;
    END
  END rb_data[199]
  PIN rb_data[200]
    DIRECTION OUTPUT ;
    USE SIGNAL ;
    PORT
      LAYER M4 ;
      RECT 0.00000 57.64800 0.02400 57.67200 ;
    END
  END rb_data[200]
  PIN rb_data[201]
    DIRECTION OUTPUT ;
    USE SIGNAL ;
    PORT
      LAYER M4 ;
      RECT 0.00000 57.93600 0.02400 57.96000 ;
    END
  END rb_data[201]
  PIN rb_data[202]
    DIRECTION OUTPUT ;
    USE SIGNAL ;
    PORT
      LAYER M4 ;
      RECT 0.00000 58.22400 0.02400 58.24800 ;
    END
  END rb_data[202]
  PIN rb_data[203]
    DIRECTION OUTPUT ;
    USE SIGNAL ;
    PORT
      LAYER M4 ;
      RECT 0.00000 58.51200 0.02400 58.53600 ;
    END
  END rb_data[203]
  PIN rb_data[204]
    DIRECTION OUTPUT ;
    USE SIGNAL ;
    PORT
      LAYER M4 ;
      RECT 0.00000 58.80000 0.02400 58.82400 ;
    END
  END rb_data[204]
  PIN rb_data[205]
    DIRECTION OUTPUT ;
    USE SIGNAL ;
    PORT
      LAYER M4 ;
      RECT 0.00000 59.08800 0.02400 59.11200 ;
    END
  END rb_data[205]
  PIN rb_data[206]
    DIRECTION OUTPUT ;
    USE SIGNAL ;
    PORT
      LAYER M4 ;
      RECT 0.00000 59.37600 0.02400 59.40000 ;
    END
  END rb_data[206]
  PIN rb_data[207]
    DIRECTION OUTPUT ;
    USE SIGNAL ;
    PORT
      LAYER M4 ;
      RECT 0.00000 59.66400 0.02400 59.68800 ;
    END
  END rb_data[207]
  PIN rb_data[208]
    DIRECTION OUTPUT ;
    USE SIGNAL ;
    PORT
      LAYER M4 ;
      RECT 0.00000 59.95200 0.02400 59.97600 ;
    END
  END rb_data[208]
  PIN rb_data[209]
    DIRECTION OUTPUT ;
    USE SIGNAL ;
    PORT
      LAYER M4 ;
      RECT 0.00000 60.24000 0.02400 60.26400 ;
    END
  END rb_data[209]
  PIN rb_data[210]
    DIRECTION OUTPUT ;
    USE SIGNAL ;
    PORT
      LAYER M4 ;
      RECT 0.00000 60.52800 0.02400 60.55200 ;
    END
  END rb_data[210]
  PIN rb_data[211]
    DIRECTION OUTPUT ;
    USE SIGNAL ;
    PORT
      LAYER M4 ;
      RECT 0.00000 60.81600 0.02400 60.84000 ;
    END
  END rb_data[211]
  PIN rb_data[212]
    DIRECTION OUTPUT ;
    USE SIGNAL ;
    PORT
      LAYER M4 ;
      RECT 0.00000 61.10400 0.02400 61.12800 ;
    END
  END rb_data[212]
  PIN rb_data[213]
    DIRECTION OUTPUT ;
    USE SIGNAL ;
    PORT
      LAYER M4 ;
      RECT 0.00000 61.39200 0.02400 61.41600 ;
    END
  END rb_data[213]
  PIN rb_data[214]
    DIRECTION OUTPUT ;
    USE SIGNAL ;
    PORT
      LAYER M4 ;
      RECT 0.00000 61.68000 0.02400 61.70400 ;
    END
  END rb_data[214]
  PIN rb_data[215]
    DIRECTION OUTPUT ;
    USE SIGNAL ;
    PORT
      LAYER M4 ;
      RECT 0.00000 61.96800 0.02400 61.99200 ;
    END
  END rb_data[215]
  PIN rb_data[216]
    DIRECTION OUTPUT ;
    USE SIGNAL ;
    PORT
      LAYER M4 ;
      RECT 0.00000 62.25600 0.02400 62.28000 ;
    END
  END rb_data[216]
  PIN rb_data[217]
    DIRECTION OUTPUT ;
    USE SIGNAL ;
    PORT
      LAYER M4 ;
      RECT 0.00000 62.54400 0.02400 62.56800 ;
    END
  END rb_data[217]
  PIN rb_data[218]
    DIRECTION OUTPUT ;
    USE SIGNAL ;
    PORT
      LAYER M4 ;
      RECT 0.00000 62.83200 0.02400 62.85600 ;
    END
  END rb_data[218]
  PIN rb_data[219]
    DIRECTION OUTPUT ;
    USE SIGNAL ;
    PORT
      LAYER M4 ;
      RECT 0.00000 63.12000 0.02400 63.14400 ;
    END
  END rb_data[219]
  PIN rb_data[220]
    DIRECTION OUTPUT ;
    USE SIGNAL ;
    PORT
      LAYER M4 ;
      RECT 0.00000 63.40800 0.02400 63.43200 ;
    END
  END rb_data[220]
  PIN rb_data[221]
    DIRECTION OUTPUT ;
    USE SIGNAL ;
    PORT
      LAYER M4 ;
      RECT 0.00000 63.69600 0.02400 63.72000 ;
    END
  END rb_data[221]
  PIN rb_data[222]
    DIRECTION OUTPUT ;
    USE SIGNAL ;
    PORT
      LAYER M4 ;
      RECT 0.00000 63.98400 0.02400 64.00800 ;
    END
  END rb_data[222]
  PIN rb_data[223]
    DIRECTION OUTPUT ;
    USE SIGNAL ;
    PORT
      LAYER M4 ;
      RECT 0.00000 64.27200 0.02400 64.29600 ;
    END
  END rb_data[223]
  PIN rb_data[224]
    DIRECTION OUTPUT ;
    USE SIGNAL ;
    PORT
      LAYER M4 ;
      RECT 0.00000 64.56000 0.02400 64.58400 ;
    END
  END rb_data[224]
  PIN rb_data[225]
    DIRECTION OUTPUT ;
    USE SIGNAL ;
    PORT
      LAYER M4 ;
      RECT 0.00000 64.84800 0.02400 64.87200 ;
    END
  END rb_data[225]
  PIN rb_data[226]
    DIRECTION OUTPUT ;
    USE SIGNAL ;
    PORT
      LAYER M4 ;
      RECT 0.00000 65.13600 0.02400 65.16000 ;
    END
  END rb_data[226]
  PIN rb_data[227]
    DIRECTION OUTPUT ;
    USE SIGNAL ;
    PORT
      LAYER M4 ;
      RECT 0.00000 65.42400 0.02400 65.44800 ;
    END
  END rb_data[227]
  PIN rb_data[228]
    DIRECTION OUTPUT ;
    USE SIGNAL ;
    PORT
      LAYER M4 ;
      RECT 0.00000 65.71200 0.02400 65.73600 ;
    END
  END rb_data[228]
  PIN rb_data[229]
    DIRECTION OUTPUT ;
    USE SIGNAL ;
    PORT
      LAYER M4 ;
      RECT 0.00000 66.00000 0.02400 66.02400 ;
    END
  END rb_data[229]
  PIN rb_data[230]
    DIRECTION OUTPUT ;
    USE SIGNAL ;
    PORT
      LAYER M4 ;
      RECT 0.00000 66.28800 0.02400 66.31200 ;
    END
  END rb_data[230]
  PIN rb_data[231]
    DIRECTION OUTPUT ;
    USE SIGNAL ;
    PORT
      LAYER M4 ;
      RECT 0.00000 66.57600 0.02400 66.60000 ;
    END
  END rb_data[231]
  PIN rb_data[232]
    DIRECTION OUTPUT ;
    USE SIGNAL ;
    PORT
      LAYER M4 ;
      RECT 0.00000 66.86400 0.02400 66.88800 ;
    END
  END rb_data[232]
  PIN rb_data[233]
    DIRECTION OUTPUT ;
    USE SIGNAL ;
    PORT
      LAYER M4 ;
      RECT 0.00000 67.15200 0.02400 67.17600 ;
    END
  END rb_data[233]
  PIN rb_data[234]
    DIRECTION OUTPUT ;
    USE SIGNAL ;
    PORT
      LAYER M4 ;
      RECT 0.00000 67.44000 0.02400 67.46400 ;
    END
  END rb_data[234]
  PIN rb_data[235]
    DIRECTION OUTPUT ;
    USE SIGNAL ;
    PORT
      LAYER M4 ;
      RECT 0.00000 67.72800 0.02400 67.75200 ;
    END
  END rb_data[235]
  PIN rb_data[236]
    DIRECTION OUTPUT ;
    USE SIGNAL ;
    PORT
      LAYER M4 ;
      RECT 0.00000 68.01600 0.02400 68.04000 ;
    END
  END rb_data[236]
  PIN rb_data[237]
    DIRECTION OUTPUT ;
    USE SIGNAL ;
    PORT
      LAYER M4 ;
      RECT 0.00000 68.30400 0.02400 68.32800 ;
    END
  END rb_data[237]
  PIN rb_data[238]
    DIRECTION OUTPUT ;
    USE SIGNAL ;
    PORT
      LAYER M4 ;
      RECT 0.00000 68.59200 0.02400 68.61600 ;
    END
  END rb_data[238]
  PIN rb_data[239]
    DIRECTION OUTPUT ;
    USE SIGNAL ;
    PORT
      LAYER M4 ;
      RECT 0.00000 68.88000 0.02400 68.90400 ;
    END
  END rb_data[239]
  PIN rb_data[240]
    DIRECTION OUTPUT ;
    USE SIGNAL ;
    PORT
      LAYER M4 ;
      RECT 0.00000 69.16800 0.02400 69.19200 ;
    END
  END rb_data[240]
  PIN rb_data[241]
    DIRECTION OUTPUT ;
    USE SIGNAL ;
    PORT
      LAYER M4 ;
      RECT 0.00000 69.45600 0.02400 69.48000 ;
    END
  END rb_data[241]
  PIN rb_data[242]
    DIRECTION OUTPUT ;
    USE SIGNAL ;
    PORT
      LAYER M4 ;
      RECT 0.00000 69.74400 0.02400 69.76800 ;
    END
  END rb_data[242]
  PIN rb_data[243]
    DIRECTION OUTPUT ;
    USE SIGNAL ;
    PORT
      LAYER M4 ;
      RECT 0.00000 70.03200 0.02400 70.05600 ;
    END
  END rb_data[243]
  PIN rb_data[244]
    DIRECTION OUTPUT ;
    USE SIGNAL ;
    PORT
      LAYER M4 ;
      RECT 0.00000 70.32000 0.02400 70.34400 ;
    END
  END rb_data[244]
  PIN rb_data[245]
    DIRECTION OUTPUT ;
    USE SIGNAL ;
    PORT
      LAYER M4 ;
      RECT 0.00000 70.60800 0.02400 70.63200 ;
    END
  END rb_data[245]
  PIN rb_data[246]
    DIRECTION OUTPUT ;
    USE SIGNAL ;
    PORT
      LAYER M4 ;
      RECT 0.00000 70.89600 0.02400 70.92000 ;
    END
  END rb_data[246]
  PIN rb_data[247]
    DIRECTION OUTPUT ;
    USE SIGNAL ;
    PORT
      LAYER M4 ;
      RECT 0.00000 71.18400 0.02400 71.20800 ;
    END
  END rb_data[247]
  PIN rb_data[248]
    DIRECTION OUTPUT ;
    USE SIGNAL ;
    PORT
      LAYER M4 ;
      RECT 0.00000 71.47200 0.02400 71.49600 ;
    END
  END rb_data[248]
  PIN rb_data[249]
    DIRECTION OUTPUT ;
    USE SIGNAL ;
    PORT
      LAYER M4 ;
      RECT 0.00000 71.76000 0.02400 71.78400 ;
    END
  END rb_data[249]
  PIN rb_data[250]
    DIRECTION OUTPUT ;
    USE SIGNAL ;
    PORT
      LAYER M4 ;
      RECT 0.00000 72.04800 0.02400 72.07200 ;
    END
  END rb_data[250]
  PIN rb_data[251]
    DIRECTION OUTPUT ;
    USE SIGNAL ;
    PORT
      LAYER M4 ;
      RECT 0.00000 72.33600 0.02400 72.36000 ;
    END
  END rb_data[251]
  PIN rb_data[252]
    DIRECTION OUTPUT ;
    USE SIGNAL ;
    PORT
      LAYER M4 ;
      RECT 0.00000 72.62400 0.02400 72.64800 ;
    END
  END rb_data[252]
  PIN rb_data[253]
    DIRECTION OUTPUT ;
    USE SIGNAL ;
    PORT
      LAYER M4 ;
      RECT 0.00000 72.91200 0.02400 72.93600 ;
    END
  END rb_data[253]
  PIN rb_data[254]
    DIRECTION OUTPUT ;
    USE SIGNAL ;
    PORT
      LAYER M4 ;
      RECT 0.00000 73.20000 0.02400 73.22400 ;
    END
  END rb_data[254]
  PIN rb_data[255]
    DIRECTION OUTPUT ;
    USE SIGNAL ;
    PORT
      LAYER M4 ;
      RECT 0.00000 73.48800 0.02400 73.51200 ;
    END
  END rb_data[255]
  PIN rb_data[256]
    DIRECTION OUTPUT ;
    USE SIGNAL ;
    PORT
      LAYER M4 ;
      RECT 0.00000 73.77600 0.02400 73.80000 ;
    END
  END rb_data[256]
  PIN rb_data[257]
    DIRECTION OUTPUT ;
    USE SIGNAL ;
    PORT
      LAYER M4 ;
      RECT 0.00000 74.06400 0.02400 74.08800 ;
    END
  END rb_data[257]
  PIN rb_data[258]
    DIRECTION OUTPUT ;
    USE SIGNAL ;
    PORT
      LAYER M4 ;
      RECT 0.00000 74.35200 0.02400 74.37600 ;
    END
  END rb_data[258]
  PIN rb_data[259]
    DIRECTION OUTPUT ;
    USE SIGNAL ;
    PORT
      LAYER M4 ;
      RECT 0.00000 74.64000 0.02400 74.66400 ;
    END
  END rb_data[259]
  PIN rb_data[260]
    DIRECTION OUTPUT ;
    USE SIGNAL ;
    PORT
      LAYER M4 ;
      RECT 0.00000 74.92800 0.02400 74.95200 ;
    END
  END rb_data[260]
  PIN rb_data[261]
    DIRECTION OUTPUT ;
    USE SIGNAL ;
    PORT
      LAYER M4 ;
      RECT 0.00000 75.21600 0.02400 75.24000 ;
    END
  END rb_data[261]
  PIN rb_data[262]
    DIRECTION OUTPUT ;
    USE SIGNAL ;
    PORT
      LAYER M4 ;
      RECT 0.00000 75.50400 0.02400 75.52800 ;
    END
  END rb_data[262]
  PIN rb_data[263]
    DIRECTION OUTPUT ;
    USE SIGNAL ;
    PORT
      LAYER M4 ;
      RECT 0.00000 75.79200 0.02400 75.81600 ;
    END
  END rb_data[263]
  PIN rb_data[264]
    DIRECTION OUTPUT ;
    USE SIGNAL ;
    PORT
      LAYER M4 ;
      RECT 0.00000 76.08000 0.02400 76.10400 ;
    END
  END rb_data[264]
  PIN rb_data[265]
    DIRECTION OUTPUT ;
    USE SIGNAL ;
    PORT
      LAYER M4 ;
      RECT 0.00000 76.36800 0.02400 76.39200 ;
    END
  END rb_data[265]
  PIN rb_data[266]
    DIRECTION OUTPUT ;
    USE SIGNAL ;
    PORT
      LAYER M4 ;
      RECT 0.00000 76.65600 0.02400 76.68000 ;
    END
  END rb_data[266]
  PIN rb_data[267]
    DIRECTION OUTPUT ;
    USE SIGNAL ;
    PORT
      LAYER M4 ;
      RECT 0.00000 76.94400 0.02400 76.96800 ;
    END
  END rb_data[267]
  PIN rb_data[268]
    DIRECTION OUTPUT ;
    USE SIGNAL ;
    PORT
      LAYER M4 ;
      RECT 0.00000 77.23200 0.02400 77.25600 ;
    END
  END rb_data[268]
  PIN rb_data[269]
    DIRECTION OUTPUT ;
    USE SIGNAL ;
    PORT
      LAYER M4 ;
      RECT 0.00000 77.52000 0.02400 77.54400 ;
    END
  END rb_data[269]
  PIN rb_data[270]
    DIRECTION OUTPUT ;
    USE SIGNAL ;
    PORT
      LAYER M4 ;
      RECT 0.00000 77.80800 0.02400 77.83200 ;
    END
  END rb_data[270]
  PIN rb_data[271]
    DIRECTION OUTPUT ;
    USE SIGNAL ;
    PORT
      LAYER M4 ;
      RECT 0.00000 78.09600 0.02400 78.12000 ;
    END
  END rb_data[271]
  PIN rb_data[272]
    DIRECTION OUTPUT ;
    USE SIGNAL ;
    PORT
      LAYER M4 ;
      RECT 0.00000 78.38400 0.02400 78.40800 ;
    END
  END rb_data[272]
  PIN rb_data[273]
    DIRECTION OUTPUT ;
    USE SIGNAL ;
    PORT
      LAYER M4 ;
      RECT 0.00000 78.67200 0.02400 78.69600 ;
    END
  END rb_data[273]
  PIN rb_data[274]
    DIRECTION OUTPUT ;
    USE SIGNAL ;
    PORT
      LAYER M4 ;
      RECT 0.00000 78.96000 0.02400 78.98400 ;
    END
  END rb_data[274]
  PIN rb_data[275]
    DIRECTION OUTPUT ;
    USE SIGNAL ;
    PORT
      LAYER M4 ;
      RECT 0.00000 79.24800 0.02400 79.27200 ;
    END
  END rb_data[275]
  PIN rb_data[276]
    DIRECTION OUTPUT ;
    USE SIGNAL ;
    PORT
      LAYER M4 ;
      RECT 0.00000 79.53600 0.02400 79.56000 ;
    END
  END rb_data[276]
  PIN rb_data[277]
    DIRECTION OUTPUT ;
    USE SIGNAL ;
    PORT
      LAYER M4 ;
      RECT 0.00000 79.82400 0.02400 79.84800 ;
    END
  END rb_data[277]
  PIN rb_data[278]
    DIRECTION OUTPUT ;
    USE SIGNAL ;
    PORT
      LAYER M4 ;
      RECT 0.00000 80.11200 0.02400 80.13600 ;
    END
  END rb_data[278]
  PIN rb_data[279]
    DIRECTION OUTPUT ;
    USE SIGNAL ;
    PORT
      LAYER M4 ;
      RECT 0.00000 80.40000 0.02400 80.42400 ;
    END
  END rb_data[279]
  PIN rb_data[280]
    DIRECTION OUTPUT ;
    USE SIGNAL ;
    PORT
      LAYER M4 ;
      RECT 0.00000 80.68800 0.02400 80.71200 ;
    END
  END rb_data[280]
  PIN rb_data[281]
    DIRECTION OUTPUT ;
    USE SIGNAL ;
    PORT
      LAYER M4 ;
      RECT 0.00000 80.97600 0.02400 81.00000 ;
    END
  END rb_data[281]
  PIN rb_data[282]
    DIRECTION OUTPUT ;
    USE SIGNAL ;
    PORT
      LAYER M4 ;
      RECT 0.00000 81.26400 0.02400 81.28800 ;
    END
  END rb_data[282]
  PIN rb_data[283]
    DIRECTION OUTPUT ;
    USE SIGNAL ;
    PORT
      LAYER M4 ;
      RECT 0.00000 81.55200 0.02400 81.57600 ;
    END
  END rb_data[283]
  PIN rb_data[284]
    DIRECTION OUTPUT ;
    USE SIGNAL ;
    PORT
      LAYER M4 ;
      RECT 0.00000 81.84000 0.02400 81.86400 ;
    END
  END rb_data[284]
  PIN rb_data[285]
    DIRECTION OUTPUT ;
    USE SIGNAL ;
    PORT
      LAYER M4 ;
      RECT 0.00000 82.12800 0.02400 82.15200 ;
    END
  END rb_data[285]
  PIN rb_data[286]
    DIRECTION OUTPUT ;
    USE SIGNAL ;
    PORT
      LAYER M4 ;
      RECT 0.00000 82.41600 0.02400 82.44000 ;
    END
  END rb_data[286]
  PIN rb_data[287]
    DIRECTION OUTPUT ;
    USE SIGNAL ;
    PORT
      LAYER M4 ;
      RECT 0.00000 82.70400 0.02400 82.72800 ;
    END
  END rb_data[287]
  PIN rb_data[288]
    DIRECTION OUTPUT ;
    USE SIGNAL ;
    PORT
      LAYER M4 ;
      RECT 0.00000 82.99200 0.02400 83.01600 ;
    END
  END rb_data[288]
  PIN rb_data[289]
    DIRECTION OUTPUT ;
    USE SIGNAL ;
    PORT
      LAYER M4 ;
      RECT 0.00000 83.28000 0.02400 83.30400 ;
    END
  END rb_data[289]
  PIN rb_data[290]
    DIRECTION OUTPUT ;
    USE SIGNAL ;
    PORT
      LAYER M4 ;
      RECT 0.00000 83.56800 0.02400 83.59200 ;
    END
  END rb_data[290]
  PIN rb_data[291]
    DIRECTION OUTPUT ;
    USE SIGNAL ;
    PORT
      LAYER M4 ;
      RECT 0.00000 83.85600 0.02400 83.88000 ;
    END
  END rb_data[291]
  PIN rb_data[292]
    DIRECTION OUTPUT ;
    USE SIGNAL ;
    PORT
      LAYER M4 ;
      RECT 0.00000 84.14400 0.02400 84.16800 ;
    END
  END rb_data[292]
  PIN rb_data[293]
    DIRECTION OUTPUT ;
    USE SIGNAL ;
    PORT
      LAYER M4 ;
      RECT 0.00000 84.43200 0.02400 84.45600 ;
    END
  END rb_data[293]
  PIN rb_data[294]
    DIRECTION OUTPUT ;
    USE SIGNAL ;
    PORT
      LAYER M4 ;
      RECT 0.00000 84.72000 0.02400 84.74400 ;
    END
  END rb_data[294]
  PIN rb_data[295]
    DIRECTION OUTPUT ;
    USE SIGNAL ;
    PORT
      LAYER M4 ;
      RECT 0.00000 85.00800 0.02400 85.03200 ;
    END
  END rb_data[295]
  PIN rb_data[296]
    DIRECTION OUTPUT ;
    USE SIGNAL ;
    PORT
      LAYER M4 ;
      RECT 0.00000 85.29600 0.02400 85.32000 ;
    END
  END rb_data[296]
  PIN rb_data[297]
    DIRECTION OUTPUT ;
    USE SIGNAL ;
    PORT
      LAYER M4 ;
      RECT 0.00000 85.58400 0.02400 85.60800 ;
    END
  END rb_data[297]
  PIN rb_data[298]
    DIRECTION OUTPUT ;
    USE SIGNAL ;
    PORT
      LAYER M4 ;
      RECT 0.00000 85.87200 0.02400 85.89600 ;
    END
  END rb_data[298]
  PIN rb_data[299]
    DIRECTION OUTPUT ;
    USE SIGNAL ;
    PORT
      LAYER M4 ;
      RECT 0.00000 86.16000 0.02400 86.18400 ;
    END
  END rb_data[299]
  PIN rb_data[300]
    DIRECTION OUTPUT ;
    USE SIGNAL ;
    PORT
      LAYER M4 ;
      RECT 0.00000 86.44800 0.02400 86.47200 ;
    END
  END rb_data[300]
  PIN rb_data[301]
    DIRECTION OUTPUT ;
    USE SIGNAL ;
    PORT
      LAYER M4 ;
      RECT 0.00000 86.73600 0.02400 86.76000 ;
    END
  END rb_data[301]
  PIN rb_data[302]
    DIRECTION OUTPUT ;
    USE SIGNAL ;
    PORT
      LAYER M4 ;
      RECT 0.00000 87.02400 0.02400 87.04800 ;
    END
  END rb_data[302]
  PIN rb_data[303]
    DIRECTION OUTPUT ;
    USE SIGNAL ;
    PORT
      LAYER M4 ;
      RECT 0.00000 87.31200 0.02400 87.33600 ;
    END
  END rb_data[303]
  PIN rb_data[304]
    DIRECTION OUTPUT ;
    USE SIGNAL ;
    PORT
      LAYER M4 ;
      RECT 0.00000 87.60000 0.02400 87.62400 ;
    END
  END rb_data[304]
  PIN rb_data[305]
    DIRECTION OUTPUT ;
    USE SIGNAL ;
    PORT
      LAYER M4 ;
      RECT 0.00000 87.88800 0.02400 87.91200 ;
    END
  END rb_data[305]
  PIN rb_data[306]
    DIRECTION OUTPUT ;
    USE SIGNAL ;
    PORT
      LAYER M4 ;
      RECT 0.00000 88.17600 0.02400 88.20000 ;
    END
  END rb_data[306]
  PIN rb_data[307]
    DIRECTION OUTPUT ;
    USE SIGNAL ;
    PORT
      LAYER M4 ;
      RECT 0.00000 88.46400 0.02400 88.48800 ;
    END
  END rb_data[307]
  PIN rb_data[308]
    DIRECTION OUTPUT ;
    USE SIGNAL ;
    PORT
      LAYER M4 ;
      RECT 0.00000 88.75200 0.02400 88.77600 ;
    END
  END rb_data[308]
  PIN rb_data[309]
    DIRECTION OUTPUT ;
    USE SIGNAL ;
    PORT
      LAYER M4 ;
      RECT 0.00000 89.04000 0.02400 89.06400 ;
    END
  END rb_data[309]
  PIN rb_data[310]
    DIRECTION OUTPUT ;
    USE SIGNAL ;
    PORT
      LAYER M4 ;
      RECT 0.00000 89.32800 0.02400 89.35200 ;
    END
  END rb_data[310]
  PIN rb_data[311]
    DIRECTION OUTPUT ;
    USE SIGNAL ;
    PORT
      LAYER M4 ;
      RECT 0.00000 89.61600 0.02400 89.64000 ;
    END
  END rb_data[311]
  PIN rb_data[312]
    DIRECTION OUTPUT ;
    USE SIGNAL ;
    PORT
      LAYER M4 ;
      RECT 0.00000 89.90400 0.02400 89.92800 ;
    END
  END rb_data[312]
  PIN rb_data[313]
    DIRECTION OUTPUT ;
    USE SIGNAL ;
    PORT
      LAYER M4 ;
      RECT 0.00000 90.19200 0.02400 90.21600 ;
    END
  END rb_data[313]
  PIN rb_data[314]
    DIRECTION OUTPUT ;
    USE SIGNAL ;
    PORT
      LAYER M4 ;
      RECT 0.00000 90.48000 0.02400 90.50400 ;
    END
  END rb_data[314]
  PIN rb_data[315]
    DIRECTION OUTPUT ;
    USE SIGNAL ;
    PORT
      LAYER M4 ;
      RECT 0.00000 90.76800 0.02400 90.79200 ;
    END
  END rb_data[315]
  PIN rb_data[316]
    DIRECTION OUTPUT ;
    USE SIGNAL ;
    PORT
      LAYER M4 ;
      RECT 0.00000 91.05600 0.02400 91.08000 ;
    END
  END rb_data[316]
  PIN rb_data[317]
    DIRECTION OUTPUT ;
    USE SIGNAL ;
    PORT
      LAYER M4 ;
      RECT 0.00000 91.34400 0.02400 91.36800 ;
    END
  END rb_data[317]
  PIN rb_data[318]
    DIRECTION OUTPUT ;
    USE SIGNAL ;
    PORT
      LAYER M4 ;
      RECT 0.00000 91.63200 0.02400 91.65600 ;
    END
  END rb_data[318]
  PIN rb_data[319]
    DIRECTION OUTPUT ;
    USE SIGNAL ;
    PORT
      LAYER M4 ;
      RECT 0.00000 91.92000 0.02400 91.94400 ;
    END
  END rb_data[319]
  PIN rb_data[320]
    DIRECTION OUTPUT ;
    USE SIGNAL ;
    PORT
      LAYER M4 ;
      RECT 0.00000 92.20800 0.02400 92.23200 ;
    END
  END rb_data[320]
  PIN rb_data[321]
    DIRECTION OUTPUT ;
    USE SIGNAL ;
    PORT
      LAYER M4 ;
      RECT 0.00000 92.49600 0.02400 92.52000 ;
    END
  END rb_data[321]
  PIN rb_data[322]
    DIRECTION OUTPUT ;
    USE SIGNAL ;
    PORT
      LAYER M4 ;
      RECT 0.00000 92.78400 0.02400 92.80800 ;
    END
  END rb_data[322]
  PIN rb_data[323]
    DIRECTION OUTPUT ;
    USE SIGNAL ;
    PORT
      LAYER M4 ;
      RECT 0.00000 93.07200 0.02400 93.09600 ;
    END
  END rb_data[323]
  PIN rb_data[324]
    DIRECTION OUTPUT ;
    USE SIGNAL ;
    PORT
      LAYER M4 ;
      RECT 0.00000 93.36000 0.02400 93.38400 ;
    END
  END rb_data[324]
  PIN rb_data[325]
    DIRECTION OUTPUT ;
    USE SIGNAL ;
    PORT
      LAYER M4 ;
      RECT 0.00000 93.64800 0.02400 93.67200 ;
    END
  END rb_data[325]
  PIN rb_data[326]
    DIRECTION OUTPUT ;
    USE SIGNAL ;
    PORT
      LAYER M4 ;
      RECT 0.00000 93.93600 0.02400 93.96000 ;
    END
  END rb_data[326]
  PIN rb_data[327]
    DIRECTION OUTPUT ;
    USE SIGNAL ;
    PORT
      LAYER M4 ;
      RECT 0.00000 94.22400 0.02400 94.24800 ;
    END
  END rb_data[327]
  PIN rb_data[328]
    DIRECTION OUTPUT ;
    USE SIGNAL ;
    PORT
      LAYER M4 ;
      RECT 0.00000 94.51200 0.02400 94.53600 ;
    END
  END rb_data[328]
  PIN rb_data[329]
    DIRECTION OUTPUT ;
    USE SIGNAL ;
    PORT
      LAYER M4 ;
      RECT 0.00000 94.80000 0.02400 94.82400 ;
    END
  END rb_data[329]
  PIN rb_data[330]
    DIRECTION OUTPUT ;
    USE SIGNAL ;
    PORT
      LAYER M4 ;
      RECT 0.00000 95.08800 0.02400 95.11200 ;
    END
  END rb_data[330]
  PIN rb_data[331]
    DIRECTION OUTPUT ;
    USE SIGNAL ;
    PORT
      LAYER M4 ;
      RECT 0.00000 95.37600 0.02400 95.40000 ;
    END
  END rb_data[331]
  PIN rb_data[332]
    DIRECTION OUTPUT ;
    USE SIGNAL ;
    PORT
      LAYER M4 ;
      RECT 0.00000 95.66400 0.02400 95.68800 ;
    END
  END rb_data[332]
  PIN rb_data[333]
    DIRECTION OUTPUT ;
    USE SIGNAL ;
    PORT
      LAYER M4 ;
      RECT 0.00000 95.95200 0.02400 95.97600 ;
    END
  END rb_data[333]
  PIN rb_data[334]
    DIRECTION OUTPUT ;
    USE SIGNAL ;
    PORT
      LAYER M4 ;
      RECT 0.00000 96.24000 0.02400 96.26400 ;
    END
  END rb_data[334]
  PIN rb_data[335]
    DIRECTION OUTPUT ;
    USE SIGNAL ;
    PORT
      LAYER M4 ;
      RECT 0.00000 96.52800 0.02400 96.55200 ;
    END
  END rb_data[335]
  PIN rb_data[336]
    DIRECTION OUTPUT ;
    USE SIGNAL ;
    PORT
      LAYER M4 ;
      RECT 0.00000 96.81600 0.02400 96.84000 ;
    END
  END rb_data[336]
  PIN rb_data[337]
    DIRECTION OUTPUT ;
    USE SIGNAL ;
    PORT
      LAYER M4 ;
      RECT 0.00000 97.10400 0.02400 97.12800 ;
    END
  END rb_data[337]
  PIN rb_data[338]
    DIRECTION OUTPUT ;
    USE SIGNAL ;
    PORT
      LAYER M4 ;
      RECT 0.00000 97.39200 0.02400 97.41600 ;
    END
  END rb_data[338]
  PIN rb_data[339]
    DIRECTION OUTPUT ;
    USE SIGNAL ;
    PORT
      LAYER M4 ;
      RECT 0.00000 97.68000 0.02400 97.70400 ;
    END
  END rb_data[339]
  PIN rb_data[340]
    DIRECTION OUTPUT ;
    USE SIGNAL ;
    PORT
      LAYER M4 ;
      RECT 0.00000 97.96800 0.02400 97.99200 ;
    END
  END rb_data[340]
  PIN rb_data[341]
    DIRECTION OUTPUT ;
    USE SIGNAL ;
    PORT
      LAYER M4 ;
      RECT 0.00000 98.25600 0.02400 98.28000 ;
    END
  END rb_data[341]
  PIN rb_data[342]
    DIRECTION OUTPUT ;
    USE SIGNAL ;
    PORT
      LAYER M4 ;
      RECT 0.00000 98.54400 0.02400 98.56800 ;
    END
  END rb_data[342]
  PIN rb_data[343]
    DIRECTION OUTPUT ;
    USE SIGNAL ;
    PORT
      LAYER M4 ;
      RECT 0.00000 98.83200 0.02400 98.85600 ;
    END
  END rb_data[343]
  PIN rb_data[344]
    DIRECTION OUTPUT ;
    USE SIGNAL ;
    PORT
      LAYER M4 ;
      RECT 0.00000 99.12000 0.02400 99.14400 ;
    END
  END rb_data[344]
  PIN rb_data[345]
    DIRECTION OUTPUT ;
    USE SIGNAL ;
    PORT
      LAYER M4 ;
      RECT 0.00000 99.40800 0.02400 99.43200 ;
    END
  END rb_data[345]
  PIN rb_data[346]
    DIRECTION OUTPUT ;
    USE SIGNAL ;
    PORT
      LAYER M4 ;
      RECT 0.00000 99.69600 0.02400 99.72000 ;
    END
  END rb_data[346]
  PIN rb_data[347]
    DIRECTION OUTPUT ;
    USE SIGNAL ;
    PORT
      LAYER M4 ;
      RECT 0.00000 99.98400 0.02400 100.00800 ;
    END
  END rb_data[347]
  PIN rb_data[348]
    DIRECTION OUTPUT ;
    USE SIGNAL ;
    PORT
      LAYER M4 ;
      RECT 0.00000 100.27200 0.02400 100.29600 ;
    END
  END rb_data[348]
  PIN rb_data[349]
    DIRECTION OUTPUT ;
    USE SIGNAL ;
    PORT
      LAYER M4 ;
      RECT 0.00000 100.56000 0.02400 100.58400 ;
    END
  END rb_data[349]
  PIN rb_data[350]
    DIRECTION OUTPUT ;
    USE SIGNAL ;
    PORT
      LAYER M4 ;
      RECT 0.00000 100.84800 0.02400 100.87200 ;
    END
  END rb_data[350]
  PIN rb_data[351]
    DIRECTION OUTPUT ;
    USE SIGNAL ;
    PORT
      LAYER M4 ;
      RECT 0.00000 101.13600 0.02400 101.16000 ;
    END
  END rb_data[351]
  PIN rb_data[352]
    DIRECTION OUTPUT ;
    USE SIGNAL ;
    PORT
      LAYER M4 ;
      RECT 0.00000 101.42400 0.02400 101.44800 ;
    END
  END rb_data[352]
  PIN rb_data[353]
    DIRECTION OUTPUT ;
    USE SIGNAL ;
    PORT
      LAYER M4 ;
      RECT 0.00000 101.71200 0.02400 101.73600 ;
    END
  END rb_data[353]
  PIN rb_data[354]
    DIRECTION OUTPUT ;
    USE SIGNAL ;
    PORT
      LAYER M4 ;
      RECT 0.00000 102.00000 0.02400 102.02400 ;
    END
  END rb_data[354]
  PIN rb_data[355]
    DIRECTION OUTPUT ;
    USE SIGNAL ;
    PORT
      LAYER M4 ;
      RECT 0.00000 102.28800 0.02400 102.31200 ;
    END
  END rb_data[355]
  PIN rb_data[356]
    DIRECTION OUTPUT ;
    USE SIGNAL ;
    PORT
      LAYER M4 ;
      RECT 0.00000 102.57600 0.02400 102.60000 ;
    END
  END rb_data[356]
  PIN rb_data[357]
    DIRECTION OUTPUT ;
    USE SIGNAL ;
    PORT
      LAYER M4 ;
      RECT 0.00000 102.86400 0.02400 102.88800 ;
    END
  END rb_data[357]
  PIN rb_data[358]
    DIRECTION OUTPUT ;
    USE SIGNAL ;
    PORT
      LAYER M4 ;
      RECT 0.00000 103.15200 0.02400 103.17600 ;
    END
  END rb_data[358]
  PIN rb_data[359]
    DIRECTION OUTPUT ;
    USE SIGNAL ;
    PORT
      LAYER M4 ;
      RECT 0.00000 103.44000 0.02400 103.46400 ;
    END
  END rb_data[359]
  PIN rb_data[360]
    DIRECTION OUTPUT ;
    USE SIGNAL ;
    PORT
      LAYER M4 ;
      RECT 0.00000 103.72800 0.02400 103.75200 ;
    END
  END rb_data[360]
  PIN rb_data[361]
    DIRECTION OUTPUT ;
    USE SIGNAL ;
    PORT
      LAYER M4 ;
      RECT 0.00000 104.01600 0.02400 104.04000 ;
    END
  END rb_data[361]
  PIN rb_data[362]
    DIRECTION OUTPUT ;
    USE SIGNAL ;
    PORT
      LAYER M4 ;
      RECT 0.00000 104.30400 0.02400 104.32800 ;
    END
  END rb_data[362]
  PIN rb_data[363]
    DIRECTION OUTPUT ;
    USE SIGNAL ;
    PORT
      LAYER M4 ;
      RECT 0.00000 104.59200 0.02400 104.61600 ;
    END
  END rb_data[363]
  PIN rb_data[364]
    DIRECTION OUTPUT ;
    USE SIGNAL ;
    PORT
      LAYER M4 ;
      RECT 0.00000 104.88000 0.02400 104.90400 ;
    END
  END rb_data[364]
  PIN rb_data[365]
    DIRECTION OUTPUT ;
    USE SIGNAL ;
    PORT
      LAYER M4 ;
      RECT 0.00000 105.16800 0.02400 105.19200 ;
    END
  END rb_data[365]
  PIN rb_data[366]
    DIRECTION OUTPUT ;
    USE SIGNAL ;
    PORT
      LAYER M4 ;
      RECT 0.00000 105.45600 0.02400 105.48000 ;
    END
  END rb_data[366]
  PIN rb_data[367]
    DIRECTION OUTPUT ;
    USE SIGNAL ;
    PORT
      LAYER M4 ;
      RECT 0.00000 105.74400 0.02400 105.76800 ;
    END
  END rb_data[367]
  PIN rb_data[368]
    DIRECTION OUTPUT ;
    USE SIGNAL ;
    PORT
      LAYER M4 ;
      RECT 0.00000 106.03200 0.02400 106.05600 ;
    END
  END rb_data[368]
  PIN rb_data[369]
    DIRECTION OUTPUT ;
    USE SIGNAL ;
    PORT
      LAYER M4 ;
      RECT 0.00000 106.32000 0.02400 106.34400 ;
    END
  END rb_data[369]
  PIN rb_data[370]
    DIRECTION OUTPUT ;
    USE SIGNAL ;
    PORT
      LAYER M4 ;
      RECT 0.00000 106.60800 0.02400 106.63200 ;
    END
  END rb_data[370]
  PIN rb_data[371]
    DIRECTION OUTPUT ;
    USE SIGNAL ;
    PORT
      LAYER M4 ;
      RECT 0.00000 106.89600 0.02400 106.92000 ;
    END
  END rb_data[371]
  PIN rb_data[372]
    DIRECTION OUTPUT ;
    USE SIGNAL ;
    PORT
      LAYER M4 ;
      RECT 0.00000 107.18400 0.02400 107.20800 ;
    END
  END rb_data[372]
  PIN rb_data[373]
    DIRECTION OUTPUT ;
    USE SIGNAL ;
    PORT
      LAYER M4 ;
      RECT 0.00000 107.47200 0.02400 107.49600 ;
    END
  END rb_data[373]
  PIN rb_data[374]
    DIRECTION OUTPUT ;
    USE SIGNAL ;
    PORT
      LAYER M4 ;
      RECT 0.00000 107.76000 0.02400 107.78400 ;
    END
  END rb_data[374]
  PIN rb_data[375]
    DIRECTION OUTPUT ;
    USE SIGNAL ;
    PORT
      LAYER M4 ;
      RECT 0.00000 108.04800 0.02400 108.07200 ;
    END
  END rb_data[375]
  PIN rb_data[376]
    DIRECTION OUTPUT ;
    USE SIGNAL ;
    PORT
      LAYER M4 ;
      RECT 0.00000 108.33600 0.02400 108.36000 ;
    END
  END rb_data[376]
  PIN rb_data[377]
    DIRECTION OUTPUT ;
    USE SIGNAL ;
    PORT
      LAYER M4 ;
      RECT 0.00000 108.62400 0.02400 108.64800 ;
    END
  END rb_data[377]
  PIN rb_data[378]
    DIRECTION OUTPUT ;
    USE SIGNAL ;
    PORT
      LAYER M4 ;
      RECT 0.00000 108.91200 0.02400 108.93600 ;
    END
  END rb_data[378]
  PIN rb_data[379]
    DIRECTION OUTPUT ;
    USE SIGNAL ;
    PORT
      LAYER M4 ;
      RECT 0.00000 109.20000 0.02400 109.22400 ;
    END
  END rb_data[379]
  PIN rb_data[380]
    DIRECTION OUTPUT ;
    USE SIGNAL ;
    PORT
      LAYER M4 ;
      RECT 0.00000 109.48800 0.02400 109.51200 ;
    END
  END rb_data[380]
  PIN rb_data[381]
    DIRECTION OUTPUT ;
    USE SIGNAL ;
    PORT
      LAYER M4 ;
      RECT 0.00000 109.77600 0.02400 109.80000 ;
    END
  END rb_data[381]
  PIN rb_data[382]
    DIRECTION OUTPUT ;
    USE SIGNAL ;
    PORT
      LAYER M4 ;
      RECT 0.00000 110.06400 0.02400 110.08800 ;
    END
  END rb_data[382]
  PIN rb_data[383]
    DIRECTION OUTPUT ;
    USE SIGNAL ;
    PORT
      LAYER M4 ;
      RECT 0.00000 110.35200 0.02400 110.37600 ;
    END
  END rb_data[383]
  PIN rb_data[384]
    DIRECTION OUTPUT ;
    USE SIGNAL ;
    PORT
      LAYER M4 ;
      RECT 0.00000 110.64000 0.02400 110.66400 ;
    END
  END rb_data[384]
  PIN rb_data[385]
    DIRECTION OUTPUT ;
    USE SIGNAL ;
    PORT
      LAYER M4 ;
      RECT 0.00000 110.92800 0.02400 110.95200 ;
    END
  END rb_data[385]
  PIN rb_data[386]
    DIRECTION OUTPUT ;
    USE SIGNAL ;
    PORT
      LAYER M4 ;
      RECT 0.00000 111.21600 0.02400 111.24000 ;
    END
  END rb_data[386]
  PIN rb_data[387]
    DIRECTION OUTPUT ;
    USE SIGNAL ;
    PORT
      LAYER M4 ;
      RECT 0.00000 111.50400 0.02400 111.52800 ;
    END
  END rb_data[387]
  PIN rb_data[388]
    DIRECTION OUTPUT ;
    USE SIGNAL ;
    PORT
      LAYER M4 ;
      RECT 0.00000 111.79200 0.02400 111.81600 ;
    END
  END rb_data[388]
  PIN rb_data[389]
    DIRECTION OUTPUT ;
    USE SIGNAL ;
    PORT
      LAYER M4 ;
      RECT 0.00000 112.08000 0.02400 112.10400 ;
    END
  END rb_data[389]
  PIN rb_data[390]
    DIRECTION OUTPUT ;
    USE SIGNAL ;
    PORT
      LAYER M4 ;
      RECT 0.00000 112.36800 0.02400 112.39200 ;
    END
  END rb_data[390]
  PIN rb_data[391]
    DIRECTION OUTPUT ;
    USE SIGNAL ;
    PORT
      LAYER M4 ;
      RECT 0.00000 112.65600 0.02400 112.68000 ;
    END
  END rb_data[391]
  PIN rb_data[392]
    DIRECTION OUTPUT ;
    USE SIGNAL ;
    PORT
      LAYER M4 ;
      RECT 0.00000 112.94400 0.02400 112.96800 ;
    END
  END rb_data[392]
  PIN rb_data[393]
    DIRECTION OUTPUT ;
    USE SIGNAL ;
    PORT
      LAYER M4 ;
      RECT 0.00000 113.23200 0.02400 113.25600 ;
    END
  END rb_data[393]
  PIN rb_data[394]
    DIRECTION OUTPUT ;
    USE SIGNAL ;
    PORT
      LAYER M4 ;
      RECT 0.00000 113.52000 0.02400 113.54400 ;
    END
  END rb_data[394]
  PIN rb_data[395]
    DIRECTION OUTPUT ;
    USE SIGNAL ;
    PORT
      LAYER M4 ;
      RECT 0.00000 113.80800 0.02400 113.83200 ;
    END
  END rb_data[395]
  PIN rb_data[396]
    DIRECTION OUTPUT ;
    USE SIGNAL ;
    PORT
      LAYER M4 ;
      RECT 0.00000 114.09600 0.02400 114.12000 ;
    END
  END rb_data[396]
  PIN rb_data[397]
    DIRECTION OUTPUT ;
    USE SIGNAL ;
    PORT
      LAYER M4 ;
      RECT 0.00000 114.38400 0.02400 114.40800 ;
    END
  END rb_data[397]
  PIN rb_data[398]
    DIRECTION OUTPUT ;
    USE SIGNAL ;
    PORT
      LAYER M4 ;
      RECT 0.00000 114.67200 0.02400 114.69600 ;
    END
  END rb_data[398]
  PIN rb_data[399]
    DIRECTION OUTPUT ;
    USE SIGNAL ;
    PORT
      LAYER M4 ;
      RECT 0.00000 114.96000 0.02400 114.98400 ;
    END
  END rb_data[399]
  PIN rb_data[400]
    DIRECTION OUTPUT ;
    USE SIGNAL ;
    PORT
      LAYER M4 ;
      RECT 0.00000 115.24800 0.02400 115.27200 ;
    END
  END rb_data[400]
  PIN rb_data[401]
    DIRECTION OUTPUT ;
    USE SIGNAL ;
    PORT
      LAYER M4 ;
      RECT 0.00000 115.53600 0.02400 115.56000 ;
    END
  END rb_data[401]
  PIN rb_data[402]
    DIRECTION OUTPUT ;
    USE SIGNAL ;
    PORT
      LAYER M4 ;
      RECT 0.00000 115.82400 0.02400 115.84800 ;
    END
  END rb_data[402]
  PIN rb_data[403]
    DIRECTION OUTPUT ;
    USE SIGNAL ;
    PORT
      LAYER M4 ;
      RECT 0.00000 116.11200 0.02400 116.13600 ;
    END
  END rb_data[403]
  PIN rb_data[404]
    DIRECTION OUTPUT ;
    USE SIGNAL ;
    PORT
      LAYER M4 ;
      RECT 0.00000 116.40000 0.02400 116.42400 ;
    END
  END rb_data[404]
  PIN rb_data[405]
    DIRECTION OUTPUT ;
    USE SIGNAL ;
    PORT
      LAYER M4 ;
      RECT 0.00000 116.68800 0.02400 116.71200 ;
    END
  END rb_data[405]
  PIN rb_data[406]
    DIRECTION OUTPUT ;
    USE SIGNAL ;
    PORT
      LAYER M4 ;
      RECT 0.00000 116.97600 0.02400 117.00000 ;
    END
  END rb_data[406]
  PIN rb_data[407]
    DIRECTION OUTPUT ;
    USE SIGNAL ;
    PORT
      LAYER M4 ;
      RECT 0.00000 117.26400 0.02400 117.28800 ;
    END
  END rb_data[407]
  PIN rb_data[408]
    DIRECTION OUTPUT ;
    USE SIGNAL ;
    PORT
      LAYER M4 ;
      RECT 0.00000 117.55200 0.02400 117.57600 ;
    END
  END rb_data[408]
  PIN rb_data[409]
    DIRECTION OUTPUT ;
    USE SIGNAL ;
    PORT
      LAYER M4 ;
      RECT 0.00000 117.84000 0.02400 117.86400 ;
    END
  END rb_data[409]
  PIN rb_data[410]
    DIRECTION OUTPUT ;
    USE SIGNAL ;
    PORT
      LAYER M4 ;
      RECT 0.00000 118.12800 0.02400 118.15200 ;
    END
  END rb_data[410]
  PIN rb_data[411]
    DIRECTION OUTPUT ;
    USE SIGNAL ;
    PORT
      LAYER M4 ;
      RECT 0.00000 118.41600 0.02400 118.44000 ;
    END
  END rb_data[411]
  PIN rb_data[412]
    DIRECTION OUTPUT ;
    USE SIGNAL ;
    PORT
      LAYER M4 ;
      RECT 0.00000 118.70400 0.02400 118.72800 ;
    END
  END rb_data[412]
  PIN rb_data[413]
    DIRECTION OUTPUT ;
    USE SIGNAL ;
    PORT
      LAYER M4 ;
      RECT 0.00000 118.99200 0.02400 119.01600 ;
    END
  END rb_data[413]
  PIN rb_data[414]
    DIRECTION OUTPUT ;
    USE SIGNAL ;
    PORT
      LAYER M4 ;
      RECT 0.00000 119.28000 0.02400 119.30400 ;
    END
  END rb_data[414]
  PIN rb_data[415]
    DIRECTION OUTPUT ;
    USE SIGNAL ;
    PORT
      LAYER M4 ;
      RECT 0.00000 119.56800 0.02400 119.59200 ;
    END
  END rb_data[415]
  PIN rb_data[416]
    DIRECTION OUTPUT ;
    USE SIGNAL ;
    PORT
      LAYER M4 ;
      RECT 0.00000 119.85600 0.02400 119.88000 ;
    END
  END rb_data[416]
  PIN rb_data[417]
    DIRECTION OUTPUT ;
    USE SIGNAL ;
    PORT
      LAYER M4 ;
      RECT 0.00000 120.14400 0.02400 120.16800 ;
    END
  END rb_data[417]
  PIN rb_data[418]
    DIRECTION OUTPUT ;
    USE SIGNAL ;
    PORT
      LAYER M4 ;
      RECT 0.00000 120.43200 0.02400 120.45600 ;
    END
  END rb_data[418]
  PIN rb_data[419]
    DIRECTION OUTPUT ;
    USE SIGNAL ;
    PORT
      LAYER M4 ;
      RECT 0.00000 120.72000 0.02400 120.74400 ;
    END
  END rb_data[419]
  PIN rb_data[420]
    DIRECTION OUTPUT ;
    USE SIGNAL ;
    PORT
      LAYER M4 ;
      RECT 0.00000 121.00800 0.02400 121.03200 ;
    END
  END rb_data[420]
  PIN rb_data[421]
    DIRECTION OUTPUT ;
    USE SIGNAL ;
    PORT
      LAYER M4 ;
      RECT 0.00000 121.29600 0.02400 121.32000 ;
    END
  END rb_data[421]
  PIN rb_data[422]
    DIRECTION OUTPUT ;
    USE SIGNAL ;
    PORT
      LAYER M4 ;
      RECT 0.00000 121.58400 0.02400 121.60800 ;
    END
  END rb_data[422]
  PIN rb_data[423]
    DIRECTION OUTPUT ;
    USE SIGNAL ;
    PORT
      LAYER M4 ;
      RECT 0.00000 121.87200 0.02400 121.89600 ;
    END
  END rb_data[423]
  PIN rb_data[424]
    DIRECTION OUTPUT ;
    USE SIGNAL ;
    PORT
      LAYER M4 ;
      RECT 0.00000 122.16000 0.02400 122.18400 ;
    END
  END rb_data[424]
  PIN rb_data[425]
    DIRECTION OUTPUT ;
    USE SIGNAL ;
    PORT
      LAYER M4 ;
      RECT 0.00000 122.44800 0.02400 122.47200 ;
    END
  END rb_data[425]
  PIN rb_data[426]
    DIRECTION OUTPUT ;
    USE SIGNAL ;
    PORT
      LAYER M4 ;
      RECT 0.00000 122.73600 0.02400 122.76000 ;
    END
  END rb_data[426]
  PIN rb_data[427]
    DIRECTION OUTPUT ;
    USE SIGNAL ;
    PORT
      LAYER M4 ;
      RECT 0.00000 123.02400 0.02400 123.04800 ;
    END
  END rb_data[427]
  PIN rb_data[428]
    DIRECTION OUTPUT ;
    USE SIGNAL ;
    PORT
      LAYER M4 ;
      RECT 0.00000 123.31200 0.02400 123.33600 ;
    END
  END rb_data[428]
  PIN rb_data[429]
    DIRECTION OUTPUT ;
    USE SIGNAL ;
    PORT
      LAYER M4 ;
      RECT 0.00000 123.60000 0.02400 123.62400 ;
    END
  END rb_data[429]
  PIN rb_data[430]
    DIRECTION OUTPUT ;
    USE SIGNAL ;
    PORT
      LAYER M4 ;
      RECT 0.00000 123.88800 0.02400 123.91200 ;
    END
  END rb_data[430]
  PIN rb_data[431]
    DIRECTION OUTPUT ;
    USE SIGNAL ;
    PORT
      LAYER M4 ;
      RECT 0.00000 124.17600 0.02400 124.20000 ;
    END
  END rb_data[431]
  PIN rb_data[432]
    DIRECTION OUTPUT ;
    USE SIGNAL ;
    PORT
      LAYER M4 ;
      RECT 0.00000 124.46400 0.02400 124.48800 ;
    END
  END rb_data[432]
  PIN rb_data[433]
    DIRECTION OUTPUT ;
    USE SIGNAL ;
    PORT
      LAYER M4 ;
      RECT 0.00000 124.75200 0.02400 124.77600 ;
    END
  END rb_data[433]
  PIN rb_data[434]
    DIRECTION OUTPUT ;
    USE SIGNAL ;
    PORT
      LAYER M4 ;
      RECT 0.00000 125.04000 0.02400 125.06400 ;
    END
  END rb_data[434]
  PIN rb_data[435]
    DIRECTION OUTPUT ;
    USE SIGNAL ;
    PORT
      LAYER M4 ;
      RECT 0.00000 125.32800 0.02400 125.35200 ;
    END
  END rb_data[435]
  PIN rb_data[436]
    DIRECTION OUTPUT ;
    USE SIGNAL ;
    PORT
      LAYER M4 ;
      RECT 0.00000 125.61600 0.02400 125.64000 ;
    END
  END rb_data[436]
  PIN rb_data[437]
    DIRECTION OUTPUT ;
    USE SIGNAL ;
    PORT
      LAYER M4 ;
      RECT 0.00000 125.90400 0.02400 125.92800 ;
    END
  END rb_data[437]
  PIN rb_data[438]
    DIRECTION OUTPUT ;
    USE SIGNAL ;
    PORT
      LAYER M4 ;
      RECT 0.00000 126.19200 0.02400 126.21600 ;
    END
  END rb_data[438]
  PIN rb_data[439]
    DIRECTION OUTPUT ;
    USE SIGNAL ;
    PORT
      LAYER M4 ;
      RECT 0.00000 126.48000 0.02400 126.50400 ;
    END
  END rb_data[439]
  PIN rb_data[440]
    DIRECTION OUTPUT ;
    USE SIGNAL ;
    PORT
      LAYER M4 ;
      RECT 0.00000 126.76800 0.02400 126.79200 ;
    END
  END rb_data[440]
  PIN rb_data[441]
    DIRECTION OUTPUT ;
    USE SIGNAL ;
    PORT
      LAYER M4 ;
      RECT 0.00000 127.05600 0.02400 127.08000 ;
    END
  END rb_data[441]
  PIN rb_data[442]
    DIRECTION OUTPUT ;
    USE SIGNAL ;
    PORT
      LAYER M4 ;
      RECT 0.00000 127.34400 0.02400 127.36800 ;
    END
  END rb_data[442]
  PIN rb_data[443]
    DIRECTION OUTPUT ;
    USE SIGNAL ;
    PORT
      LAYER M4 ;
      RECT 0.00000 127.63200 0.02400 127.65600 ;
    END
  END rb_data[443]
  PIN rb_data[444]
    DIRECTION OUTPUT ;
    USE SIGNAL ;
    PORT
      LAYER M4 ;
      RECT 0.00000 127.92000 0.02400 127.94400 ;
    END
  END rb_data[444]
  PIN rb_data[445]
    DIRECTION OUTPUT ;
    USE SIGNAL ;
    PORT
      LAYER M4 ;
      RECT 0.00000 128.20800 0.02400 128.23200 ;
    END
  END rb_data[445]
  PIN rb_data[446]
    DIRECTION OUTPUT ;
    USE SIGNAL ;
    PORT
      LAYER M4 ;
      RECT 0.00000 128.49600 0.02400 128.52000 ;
    END
  END rb_data[446]
  PIN rb_data[447]
    DIRECTION OUTPUT ;
    USE SIGNAL ;
    PORT
      LAYER M4 ;
      RECT 0.00000 128.78400 0.02400 128.80800 ;
    END
  END rb_data[447]
  PIN rb_data[448]
    DIRECTION OUTPUT ;
    USE SIGNAL ;
    PORT
      LAYER M4 ;
      RECT 0.00000 129.07200 0.02400 129.09600 ;
    END
  END rb_data[448]
  PIN rb_data[449]
    DIRECTION OUTPUT ;
    USE SIGNAL ;
    PORT
      LAYER M4 ;
      RECT 0.00000 129.36000 0.02400 129.38400 ;
    END
  END rb_data[449]
  PIN rb_data[450]
    DIRECTION OUTPUT ;
    USE SIGNAL ;
    PORT
      LAYER M4 ;
      RECT 0.00000 129.64800 0.02400 129.67200 ;
    END
  END rb_data[450]
  PIN rb_data[451]
    DIRECTION OUTPUT ;
    USE SIGNAL ;
    PORT
      LAYER M4 ;
      RECT 0.00000 129.93600 0.02400 129.96000 ;
    END
  END rb_data[451]
  PIN rb_data[452]
    DIRECTION OUTPUT ;
    USE SIGNAL ;
    PORT
      LAYER M4 ;
      RECT 0.00000 130.22400 0.02400 130.24800 ;
    END
  END rb_data[452]
  PIN rb_data[453]
    DIRECTION OUTPUT ;
    USE SIGNAL ;
    PORT
      LAYER M4 ;
      RECT 0.00000 130.51200 0.02400 130.53600 ;
    END
  END rb_data[453]
  PIN rb_data[454]
    DIRECTION OUTPUT ;
    USE SIGNAL ;
    PORT
      LAYER M4 ;
      RECT 0.00000 130.80000 0.02400 130.82400 ;
    END
  END rb_data[454]
  PIN rb_data[455]
    DIRECTION OUTPUT ;
    USE SIGNAL ;
    PORT
      LAYER M4 ;
      RECT 0.00000 131.08800 0.02400 131.11200 ;
    END
  END rb_data[455]
  PIN rb_data[456]
    DIRECTION OUTPUT ;
    USE SIGNAL ;
    PORT
      LAYER M4 ;
      RECT 0.00000 131.37600 0.02400 131.40000 ;
    END
  END rb_data[456]
  PIN rb_data[457]
    DIRECTION OUTPUT ;
    USE SIGNAL ;
    PORT
      LAYER M4 ;
      RECT 0.00000 131.66400 0.02400 131.68800 ;
    END
  END rb_data[457]
  PIN rb_data[458]
    DIRECTION OUTPUT ;
    USE SIGNAL ;
    PORT
      LAYER M4 ;
      RECT 0.00000 131.95200 0.02400 131.97600 ;
    END
  END rb_data[458]
  PIN rb_data[459]
    DIRECTION OUTPUT ;
    USE SIGNAL ;
    PORT
      LAYER M4 ;
      RECT 0.00000 132.24000 0.02400 132.26400 ;
    END
  END rb_data[459]
  PIN rb_data[460]
    DIRECTION OUTPUT ;
    USE SIGNAL ;
    PORT
      LAYER M4 ;
      RECT 0.00000 132.52800 0.02400 132.55200 ;
    END
  END rb_data[460]
  PIN rb_data[461]
    DIRECTION OUTPUT ;
    USE SIGNAL ;
    PORT
      LAYER M4 ;
      RECT 0.00000 132.81600 0.02400 132.84000 ;
    END
  END rb_data[461]
  PIN rb_data[462]
    DIRECTION OUTPUT ;
    USE SIGNAL ;
    PORT
      LAYER M4 ;
      RECT 0.00000 133.10400 0.02400 133.12800 ;
    END
  END rb_data[462]
  PIN rb_data[463]
    DIRECTION OUTPUT ;
    USE SIGNAL ;
    PORT
      LAYER M4 ;
      RECT 0.00000 133.39200 0.02400 133.41600 ;
    END
  END rb_data[463]
  PIN rb_data[464]
    DIRECTION OUTPUT ;
    USE SIGNAL ;
    PORT
      LAYER M4 ;
      RECT 0.00000 133.68000 0.02400 133.70400 ;
    END
  END rb_data[464]
  PIN rb_data[465]
    DIRECTION OUTPUT ;
    USE SIGNAL ;
    PORT
      LAYER M4 ;
      RECT 0.00000 133.96800 0.02400 133.99200 ;
    END
  END rb_data[465]
  PIN rb_data[466]
    DIRECTION OUTPUT ;
    USE SIGNAL ;
    PORT
      LAYER M4 ;
      RECT 0.00000 134.25600 0.02400 134.28000 ;
    END
  END rb_data[466]
  PIN rb_data[467]
    DIRECTION OUTPUT ;
    USE SIGNAL ;
    PORT
      LAYER M4 ;
      RECT 0.00000 134.54400 0.02400 134.56800 ;
    END
  END rb_data[467]
  PIN rb_data[468]
    DIRECTION OUTPUT ;
    USE SIGNAL ;
    PORT
      LAYER M4 ;
      RECT 0.00000 134.83200 0.02400 134.85600 ;
    END
  END rb_data[468]
  PIN rb_data[469]
    DIRECTION OUTPUT ;
    USE SIGNAL ;
    PORT
      LAYER M4 ;
      RECT 0.00000 135.12000 0.02400 135.14400 ;
    END
  END rb_data[469]
  PIN rb_data[470]
    DIRECTION OUTPUT ;
    USE SIGNAL ;
    PORT
      LAYER M4 ;
      RECT 0.00000 135.40800 0.02400 135.43200 ;
    END
  END rb_data[470]
  PIN rb_data[471]
    DIRECTION OUTPUT ;
    USE SIGNAL ;
    PORT
      LAYER M4 ;
      RECT 0.00000 135.69600 0.02400 135.72000 ;
    END
  END rb_data[471]
  PIN rb_data[472]
    DIRECTION OUTPUT ;
    USE SIGNAL ;
    PORT
      LAYER M4 ;
      RECT 0.00000 135.98400 0.02400 136.00800 ;
    END
  END rb_data[472]
  PIN rb_data[473]
    DIRECTION OUTPUT ;
    USE SIGNAL ;
    PORT
      LAYER M4 ;
      RECT 0.00000 136.27200 0.02400 136.29600 ;
    END
  END rb_data[473]
  PIN rb_data[474]
    DIRECTION OUTPUT ;
    USE SIGNAL ;
    PORT
      LAYER M4 ;
      RECT 0.00000 136.56000 0.02400 136.58400 ;
    END
  END rb_data[474]
  PIN rb_data[475]
    DIRECTION OUTPUT ;
    USE SIGNAL ;
    PORT
      LAYER M4 ;
      RECT 0.00000 136.84800 0.02400 136.87200 ;
    END
  END rb_data[475]
  PIN rb_data[476]
    DIRECTION OUTPUT ;
    USE SIGNAL ;
    PORT
      LAYER M4 ;
      RECT 0.00000 137.13600 0.02400 137.16000 ;
    END
  END rb_data[476]
  PIN rb_data[477]
    DIRECTION OUTPUT ;
    USE SIGNAL ;
    PORT
      LAYER M4 ;
      RECT 0.00000 137.42400 0.02400 137.44800 ;
    END
  END rb_data[477]
  PIN rb_data[478]
    DIRECTION OUTPUT ;
    USE SIGNAL ;
    PORT
      LAYER M4 ;
      RECT 0.00000 137.71200 0.02400 137.73600 ;
    END
  END rb_data[478]
  PIN rb_data[479]
    DIRECTION OUTPUT ;
    USE SIGNAL ;
    PORT
      LAYER M4 ;
      RECT 0.00000 138.00000 0.02400 138.02400 ;
    END
  END rb_data[479]
  PIN rb_data[480]
    DIRECTION OUTPUT ;
    USE SIGNAL ;
    PORT
      LAYER M4 ;
      RECT 0.00000 138.28800 0.02400 138.31200 ;
    END
  END rb_data[480]
  PIN rb_data[481]
    DIRECTION OUTPUT ;
    USE SIGNAL ;
    PORT
      LAYER M4 ;
      RECT 0.00000 138.57600 0.02400 138.60000 ;
    END
  END rb_data[481]
  PIN rb_data[482]
    DIRECTION OUTPUT ;
    USE SIGNAL ;
    PORT
      LAYER M4 ;
      RECT 0.00000 138.86400 0.02400 138.88800 ;
    END
  END rb_data[482]
  PIN rb_data[483]
    DIRECTION OUTPUT ;
    USE SIGNAL ;
    PORT
      LAYER M4 ;
      RECT 0.00000 139.15200 0.02400 139.17600 ;
    END
  END rb_data[483]
  PIN rb_data[484]
    DIRECTION OUTPUT ;
    USE SIGNAL ;
    PORT
      LAYER M4 ;
      RECT 0.00000 139.44000 0.02400 139.46400 ;
    END
  END rb_data[484]
  PIN rb_data[485]
    DIRECTION OUTPUT ;
    USE SIGNAL ;
    PORT
      LAYER M4 ;
      RECT 0.00000 139.72800 0.02400 139.75200 ;
    END
  END rb_data[485]
  PIN rb_data[486]
    DIRECTION OUTPUT ;
    USE SIGNAL ;
    PORT
      LAYER M4 ;
      RECT 0.00000 140.01600 0.02400 140.04000 ;
    END
  END rb_data[486]
  PIN rb_data[487]
    DIRECTION OUTPUT ;
    USE SIGNAL ;
    PORT
      LAYER M4 ;
      RECT 0.00000 140.30400 0.02400 140.32800 ;
    END
  END rb_data[487]
  PIN rb_data[488]
    DIRECTION OUTPUT ;
    USE SIGNAL ;
    PORT
      LAYER M4 ;
      RECT 0.00000 140.59200 0.02400 140.61600 ;
    END
  END rb_data[488]
  PIN rb_data[489]
    DIRECTION OUTPUT ;
    USE SIGNAL ;
    PORT
      LAYER M4 ;
      RECT 0.00000 140.88000 0.02400 140.90400 ;
    END
  END rb_data[489]
  PIN rb_data[490]
    DIRECTION OUTPUT ;
    USE SIGNAL ;
    PORT
      LAYER M4 ;
      RECT 0.00000 141.16800 0.02400 141.19200 ;
    END
  END rb_data[490]
  PIN rb_data[491]
    DIRECTION OUTPUT ;
    USE SIGNAL ;
    PORT
      LAYER M4 ;
      RECT 0.00000 141.45600 0.02400 141.48000 ;
    END
  END rb_data[491]
  PIN rb_data[492]
    DIRECTION OUTPUT ;
    USE SIGNAL ;
    PORT
      LAYER M4 ;
      RECT 0.00000 141.74400 0.02400 141.76800 ;
    END
  END rb_data[492]
  PIN rb_data[493]
    DIRECTION OUTPUT ;
    USE SIGNAL ;
    PORT
      LAYER M4 ;
      RECT 0.00000 142.03200 0.02400 142.05600 ;
    END
  END rb_data[493]
  PIN rb_data[494]
    DIRECTION OUTPUT ;
    USE SIGNAL ;
    PORT
      LAYER M4 ;
      RECT 0.00000 142.32000 0.02400 142.34400 ;
    END
  END rb_data[494]
  PIN rb_data[495]
    DIRECTION OUTPUT ;
    USE SIGNAL ;
    PORT
      LAYER M4 ;
      RECT 0.00000 142.60800 0.02400 142.63200 ;
    END
  END rb_data[495]
  PIN rb_data[496]
    DIRECTION OUTPUT ;
    USE SIGNAL ;
    PORT
      LAYER M4 ;
      RECT 0.00000 142.89600 0.02400 142.92000 ;
    END
  END rb_data[496]
  PIN rb_data[497]
    DIRECTION OUTPUT ;
    USE SIGNAL ;
    PORT
      LAYER M4 ;
      RECT 0.00000 143.18400 0.02400 143.20800 ;
    END
  END rb_data[497]
  PIN rb_data[498]
    DIRECTION OUTPUT ;
    USE SIGNAL ;
    PORT
      LAYER M4 ;
      RECT 0.00000 143.47200 0.02400 143.49600 ;
    END
  END rb_data[498]
  PIN rb_data[499]
    DIRECTION OUTPUT ;
    USE SIGNAL ;
    PORT
      LAYER M4 ;
      RECT 0.00000 143.76000 0.02400 143.78400 ;
    END
  END rb_data[499]
  PIN rb_data[500]
    DIRECTION OUTPUT ;
    USE SIGNAL ;
    PORT
      LAYER M4 ;
      RECT 0.00000 144.04800 0.02400 144.07200 ;
    END
  END rb_data[500]
  PIN rb_data[501]
    DIRECTION OUTPUT ;
    USE SIGNAL ;
    PORT
      LAYER M4 ;
      RECT 0.00000 144.33600 0.02400 144.36000 ;
    END
  END rb_data[501]
  PIN rb_data[502]
    DIRECTION OUTPUT ;
    USE SIGNAL ;
    PORT
      LAYER M4 ;
      RECT 0.00000 144.62400 0.02400 144.64800 ;
    END
  END rb_data[502]
  PIN rb_data[503]
    DIRECTION OUTPUT ;
    USE SIGNAL ;
    PORT
      LAYER M4 ;
      RECT 0.00000 144.91200 0.02400 144.93600 ;
    END
  END rb_data[503]
  PIN rb_data[504]
    DIRECTION OUTPUT ;
    USE SIGNAL ;
    PORT
      LAYER M4 ;
      RECT 0.00000 145.20000 0.02400 145.22400 ;
    END
  END rb_data[504]
  PIN rb_data[505]
    DIRECTION OUTPUT ;
    USE SIGNAL ;
    PORT
      LAYER M4 ;
      RECT 0.00000 145.48800 0.02400 145.51200 ;
    END
  END rb_data[505]
  PIN rb_data[506]
    DIRECTION OUTPUT ;
    USE SIGNAL ;
    PORT
      LAYER M4 ;
      RECT 0.00000 145.77600 0.02400 145.80000 ;
    END
  END rb_data[506]
  PIN rb_data[507]
    DIRECTION OUTPUT ;
    USE SIGNAL ;
    PORT
      LAYER M4 ;
      RECT 0.00000 146.06400 0.02400 146.08800 ;
    END
  END rb_data[507]
  PIN rb_data[508]
    DIRECTION OUTPUT ;
    USE SIGNAL ;
    PORT
      LAYER M4 ;
      RECT 0.00000 146.35200 0.02400 146.37600 ;
    END
  END rb_data[508]
  PIN rb_data[509]
    DIRECTION OUTPUT ;
    USE SIGNAL ;
    PORT
      LAYER M4 ;
      RECT 0.00000 146.64000 0.02400 146.66400 ;
    END
  END rb_data[509]
  PIN rb_data[510]
    DIRECTION OUTPUT ;
    USE SIGNAL ;
    PORT
      LAYER M4 ;
      RECT 0.00000 146.92800 0.02400 146.95200 ;
    END
  END rb_data[510]
  PIN rb_data[511]
    DIRECTION OUTPUT ;
    USE SIGNAL ;
    PORT
      LAYER M4 ;
      RECT 0.00000 147.21600 0.02400 147.24000 ;
    END
  END rb_data[511]
  PIN rb_addr[0]
    DIRECTION INPUT ;
    USE SIGNAL ;
    PORT
      LAYER M4 ;
      RECT 0.00000 318.67200 0.02400 318.69600 ;
    END
  END rb_addr[0]
  PIN rb_addr[1]
    DIRECTION INPUT ;
    USE SIGNAL ;
    PORT
      LAYER M4 ;
      RECT 0.00000 318.96000 0.02400 318.98400 ;
    END
  END rb_addr[1]
  PIN rb_addr[2]
    DIRECTION INPUT ;
    USE SIGNAL ;
    PORT
      LAYER M4 ;
      RECT 0.00000 319.24800 0.02400 319.27200 ;
    END
  END rb_addr[2]
  PIN rb_addr[3]
    DIRECTION INPUT ;
    USE SIGNAL ;
    PORT
      LAYER M4 ;
      RECT 0.00000 319.53600 0.02400 319.56000 ;
    END
  END rb_addr[3]
  PIN rb_addr[4]
    DIRECTION INPUT ;
    USE SIGNAL ;
    PORT
      LAYER M4 ;
      RECT 0.00000 319.82400 0.02400 319.84800 ;
    END
  END rb_addr[4]
  PIN rb_addr[5]
    DIRECTION INPUT ;
    USE SIGNAL ;
    PORT
      LAYER M4 ;
      RECT 0.00000 320.11200 0.02400 320.13600 ;
    END
  END rb_addr[5]
  PIN rb_addr[6]
    DIRECTION INPUT ;
    USE SIGNAL ;
    PORT
      LAYER M4 ;
      RECT 0.00000 320.40000 0.02400 320.42400 ;
    END
  END rb_addr[6]
  PIN rb_addr[7]
    DIRECTION INPUT ;
    USE SIGNAL ;
    PORT
      LAYER M4 ;
      RECT 0.00000 320.68800 0.02400 320.71200 ;
    END
  END rb_addr[7]
  PIN rb_addr[8]
    DIRECTION INPUT ;
    USE SIGNAL ;
    PORT
      LAYER M4 ;
      RECT 0.00000 320.97600 0.02400 321.00000 ;
    END
  END rb_addr[8]
  PIN rb_addr[9]
    DIRECTION INPUT ;
    USE SIGNAL ;
    PORT
      LAYER M4 ;
      RECT 0.00000 321.26400 0.02400 321.28800 ;
    END
  END rb_addr[9]
  PIN we[0]
    DIRECTION INPUT ;
    USE SIGNAL ;
    PORT
      LAYER M4 ;
      RECT 0.00000 330.81600 0.02400 330.84000 ;
    END
  END we[0]
  PIN we[1]
    DIRECTION INPUT ;
    USE SIGNAL ;
    PORT
      LAYER M4 ;
      RECT 0.00000 331.10400 0.02400 331.12800 ;
    END
  END we[1]
  PIN clk
    DIRECTION INPUT ;
    USE SIGNAL ;
    PORT
      LAYER M4 ;
      RECT 0.00000 330.52800 0.02400 330.55200 ;
    END
  END clk
  PIN rb_en
    DIRECTION INPUT ;
    USE SIGNAL ;
    PORT
      LAYER M4 ;
      RECT 0.00000 331.39200 0.02400 331.41600 ;
    END
  END rb_en
  PIN rb_addr_q[0]
    DIRECTION OUTPUT ;
    USE SIGNAL ;
    PORT
      LAYER M4 ;
      RECT 0.00000 147.50400 0.02400 147.52800 ;
    END
  END rb_addr_q[0]
  PIN rb_addr_q[1]
    DIRECTION OUTPUT ;
    USE SIGNAL ;
    PORT
      LAYER M4 ;
      RECT 0.00000 147.79200 0.02400 147.81600 ;
    END
  END rb_addr_q[1]
  PIN rb_addr_q[2]
    DIRECTION OUTPUT ;
    USE SIGNAL ;
    PORT
      LAYER M4 ;
      RECT 0.00000 148.08000 0.02400 148.10400 ;
    END
  END rb_addr_q[2]
  PIN rb_addr_q[3]
    DIRECTION OUTPUT ;
    USE SIGNAL ;
    PORT
      LAYER M4 ;
      RECT 0.00000 148.36800 0.02400 148.39200 ;
    END
  END rb_addr_q[3]
  PIN rb_addr_q[4]
    DIRECTION OUTPUT ;
    USE SIGNAL ;
    PORT
      LAYER M4 ;
      RECT 0.00000 148.65600 0.02400 148.68000 ;
    END
  END rb_addr_q[4]
  PIN rb_addr_q[5]
    DIRECTION OUTPUT ;
    USE SIGNAL ;
    PORT
      LAYER M4 ;
      RECT 0.00000 148.94400 0.02400 148.96800 ;
    END
  END rb_addr_q[5]
  PIN rb_addr_q[6]
    DIRECTION OUTPUT ;
    USE SIGNAL ;
    PORT
      LAYER M4 ;
      RECT 0.00000 149.23200 0.02400 149.25600 ;
    END
  END rb_addr_q[6]
  PIN rb_addr_q[7]
    DIRECTION OUTPUT ;
    USE SIGNAL ;
    PORT
      LAYER M4 ;
      RECT 0.00000 149.52000 0.02400 149.54400 ;
    END
  END rb_addr_q[7]
  PIN rb_addr_q[8]
    DIRECTION OUTPUT ;
    USE SIGNAL ;
    PORT
      LAYER M4 ;
      RECT 0.00000 149.80800 0.02400 149.83200 ;
    END
  END rb_addr_q[8]
  PIN rb_addr_q[9]
    DIRECTION OUTPUT ;
    USE SIGNAL ;
    PORT
      LAYER M4 ;
      RECT 0.00000 150.09600 0.02400 150.12000 ;
    END
  END rb_addr_q[9]
  PIN VDD
    DIRECTION INOUT ;
    USE POWER ;
    PORT
      LAYER M4 ;
      RECT 0.04800 0.38400 66.45200 0.48000 ;
      RECT 0.04800 1.15200 66.45200 1.24800 ;
      RECT 0.04800 1.92000 66.45200 2.01600 ;
      RECT 0.04800 2.68800 66.45200 2.78400 ;
      RECT 0.04800 3.45600 66.45200 3.55200 ;
      RECT 0.04800 4.22400 66.45200 4.32000 ;
      RECT 0.04800 4.99200 66.45200 5.08800 ;
      RECT 0.04800 5.76000 66.45200 5.85600 ;
      RECT 0.04800 6.52800 66.45200 6.62400 ;
      RECT 0.04800 7.29600 66.45200 7.39200 ;
      RECT 0.04800 8.06400 66.45200 8.16000 ;
      RECT 0.04800 8.83200 66.45200 8.92800 ;
      RECT 0.04800 9.60000 66.45200 9.69600 ;
      RECT 0.04800 10.36800 66.45200 10.46400 ;
      RECT 0.04800 11.13600 66.45200 11.23200 ;
      RECT 0.04800 11.90400 66.45200 12.00000 ;
      RECT 0.04800 12.67200 66.45200 12.76800 ;
      RECT 0.04800 13.44000 66.45200 13.53600 ;
      RECT 0.04800 14.20800 66.45200 14.30400 ;
      RECT 0.04800 14.97600 66.45200 15.07200 ;
      RECT 0.04800 15.74400 66.45200 15.84000 ;
      RECT 0.04800 16.51200 66.45200 16.60800 ;
      RECT 0.04800 17.28000 66.45200 17.37600 ;
      RECT 0.04800 18.04800 66.45200 18.14400 ;
      RECT 0.04800 18.81600 66.45200 18.91200 ;
      RECT 0.04800 19.58400 66.45200 19.68000 ;
      RECT 0.04800 20.35200 66.45200 20.44800 ;
      RECT 0.04800 21.12000 66.45200 21.21600 ;
      RECT 0.04800 21.88800 66.45200 21.98400 ;
      RECT 0.04800 22.65600 66.45200 22.75200 ;
      RECT 0.04800 23.42400 66.45200 23.52000 ;
      RECT 0.04800 24.19200 66.45200 24.28800 ;
      RECT 0.04800 24.96000 66.45200 25.05600 ;
      RECT 0.04800 25.72800 66.45200 25.82400 ;
      RECT 0.04800 26.49600 66.45200 26.59200 ;
      RECT 0.04800 27.26400 66.45200 27.36000 ;
      RECT 0.04800 28.03200 66.45200 28.12800 ;
      RECT 0.04800 28.80000 66.45200 28.89600 ;
      RECT 0.04800 29.56800 66.45200 29.66400 ;
      RECT 0.04800 30.33600 66.45200 30.43200 ;
      RECT 0.04800 31.10400 66.45200 31.20000 ;
      RECT 0.04800 31.87200 66.45200 31.96800 ;
      RECT 0.04800 32.64000 66.45200 32.73600 ;
      RECT 0.04800 33.40800 66.45200 33.50400 ;
      RECT 0.04800 34.17600 66.45200 34.27200 ;
      RECT 0.04800 34.94400 66.45200 35.04000 ;
      RECT 0.04800 35.71200 66.45200 35.80800 ;
      RECT 0.04800 36.48000 66.45200 36.57600 ;
      RECT 0.04800 37.24800 66.45200 37.34400 ;
      RECT 0.04800 38.01600 66.45200 38.11200 ;
      RECT 0.04800 38.78400 66.45200 38.88000 ;
      RECT 0.04800 39.55200 66.45200 39.64800 ;
      RECT 0.04800 40.32000 66.45200 40.41600 ;
      RECT 0.04800 41.08800 66.45200 41.18400 ;
      RECT 0.04800 41.85600 66.45200 41.95200 ;
      RECT 0.04800 42.62400 66.45200 42.72000 ;
      RECT 0.04800 43.39200 66.45200 43.48800 ;
      RECT 0.04800 44.16000 66.45200 44.25600 ;
      RECT 0.04800 44.92800 66.45200 45.02400 ;
      RECT 0.04800 45.69600 66.45200 45.79200 ;
      RECT 0.04800 46.46400 66.45200 46.56000 ;
      RECT 0.04800 47.23200 66.45200 47.32800 ;
      RECT 0.04800 48.00000 66.45200 48.09600 ;
      RECT 0.04800 48.76800 66.45200 48.86400 ;
      RECT 0.04800 49.53600 66.45200 49.63200 ;
      RECT 0.04800 50.30400 66.45200 50.40000 ;
      RECT 0.04800 51.07200 66.45200 51.16800 ;
      RECT 0.04800 51.84000 66.45200 51.93600 ;
      RECT 0.04800 52.60800 66.45200 52.70400 ;
      RECT 0.04800 53.37600 66.45200 53.47200 ;
      RECT 0.04800 54.14400 66.45200 54.24000 ;
      RECT 0.04800 54.91200 66.45200 55.00800 ;
      RECT 0.04800 55.68000 66.45200 55.77600 ;
      RECT 0.04800 56.44800 66.45200 56.54400 ;
      RECT 0.04800 57.21600 66.45200 57.31200 ;
      RECT 0.04800 57.98400 66.45200 58.08000 ;
      RECT 0.04800 58.75200 66.45200 58.84800 ;
      RECT 0.04800 59.52000 66.45200 59.61600 ;
      RECT 0.04800 60.28800 66.45200 60.38400 ;
      RECT 0.04800 61.05600 66.45200 61.15200 ;
      RECT 0.04800 61.82400 66.45200 61.92000 ;
      RECT 0.04800 62.59200 66.45200 62.68800 ;
      RECT 0.04800 63.36000 66.45200 63.45600 ;
      RECT 0.04800 64.12800 66.45200 64.22400 ;
      RECT 0.04800 64.89600 66.45200 64.99200 ;
      RECT 0.04800 65.66400 66.45200 65.76000 ;
      RECT 0.04800 66.43200 66.45200 66.52800 ;
      RECT 0.04800 67.20000 66.45200 67.29600 ;
      RECT 0.04800 67.96800 66.45200 68.06400 ;
      RECT 0.04800 68.73600 66.45200 68.83200 ;
      RECT 0.04800 69.50400 66.45200 69.60000 ;
      RECT 0.04800 70.27200 66.45200 70.36800 ;
      RECT 0.04800 71.04000 66.45200 71.13600 ;
      RECT 0.04800 71.80800 66.45200 71.90400 ;
      RECT 0.04800 72.57600 66.45200 72.67200 ;
      RECT 0.04800 73.34400 66.45200 73.44000 ;
      RECT 0.04800 74.11200 66.45200 74.20800 ;
      RECT 0.04800 74.88000 66.45200 74.97600 ;
      RECT 0.04800 75.64800 66.45200 75.74400 ;
      RECT 0.04800 76.41600 66.45200 76.51200 ;
      RECT 0.04800 77.18400 66.45200 77.28000 ;
      RECT 0.04800 77.95200 66.45200 78.04800 ;
      RECT 0.04800 78.72000 66.45200 78.81600 ;
      RECT 0.04800 79.48800 66.45200 79.58400 ;
      RECT 0.04800 80.25600 66.45200 80.35200 ;
      RECT 0.04800 81.02400 66.45200 81.12000 ;
      RECT 0.04800 81.79200 66.45200 81.88800 ;
      RECT 0.04800 82.56000 66.45200 82.65600 ;
      RECT 0.04800 83.32800 66.45200 83.42400 ;
      RECT 0.04800 84.09600 66.45200 84.19200 ;
      RECT 0.04800 84.86400 66.45200 84.96000 ;
      RECT 0.04800 85.63200 66.45200 85.72800 ;
      RECT 0.04800 86.40000 66.45200 86.49600 ;
      RECT 0.04800 87.16800 66.45200 87.26400 ;
      RECT 0.04800 87.93600 66.45200 88.03200 ;
      RECT 0.04800 88.70400 66.45200 88.80000 ;
      RECT 0.04800 89.47200 66.45200 89.56800 ;
      RECT 0.04800 90.24000 66.45200 90.33600 ;
      RECT 0.04800 91.00800 66.45200 91.10400 ;
      RECT 0.04800 91.77600 66.45200 91.87200 ;
      RECT 0.04800 92.54400 66.45200 92.64000 ;
      RECT 0.04800 93.31200 66.45200 93.40800 ;
      RECT 0.04800 94.08000 66.45200 94.17600 ;
      RECT 0.04800 94.84800 66.45200 94.94400 ;
      RECT 0.04800 95.61600 66.45200 95.71200 ;
      RECT 0.04800 96.38400 66.45200 96.48000 ;
      RECT 0.04800 97.15200 66.45200 97.24800 ;
      RECT 0.04800 97.92000 66.45200 98.01600 ;
      RECT 0.04800 98.68800 66.45200 98.78400 ;
      RECT 0.04800 99.45600 66.45200 99.55200 ;
      RECT 0.04800 100.22400 66.45200 100.32000 ;
      RECT 0.04800 100.99200 66.45200 101.08800 ;
      RECT 0.04800 101.76000 66.45200 101.85600 ;
      RECT 0.04800 102.52800 66.45200 102.62400 ;
      RECT 0.04800 103.29600 66.45200 103.39200 ;
      RECT 0.04800 104.06400 66.45200 104.16000 ;
      RECT 0.04800 104.83200 66.45200 104.92800 ;
      RECT 0.04800 105.60000 66.45200 105.69600 ;
      RECT 0.04800 106.36800 66.45200 106.46400 ;
      RECT 0.04800 107.13600 66.45200 107.23200 ;
      RECT 0.04800 107.90400 66.45200 108.00000 ;
      RECT 0.04800 108.67200 66.45200 108.76800 ;
      RECT 0.04800 109.44000 66.45200 109.53600 ;
      RECT 0.04800 110.20800 66.45200 110.30400 ;
      RECT 0.04800 110.97600 66.45200 111.07200 ;
      RECT 0.04800 111.74400 66.45200 111.84000 ;
      RECT 0.04800 112.51200 66.45200 112.60800 ;
      RECT 0.04800 113.28000 66.45200 113.37600 ;
      RECT 0.04800 114.04800 66.45200 114.14400 ;
      RECT 0.04800 114.81600 66.45200 114.91200 ;
      RECT 0.04800 115.58400 66.45200 115.68000 ;
      RECT 0.04800 116.35200 66.45200 116.44800 ;
      RECT 0.04800 117.12000 66.45200 117.21600 ;
      RECT 0.04800 117.88800 66.45200 117.98400 ;
      RECT 0.04800 118.65600 66.45200 118.75200 ;
      RECT 0.04800 119.42400 66.45200 119.52000 ;
      RECT 0.04800 120.19200 66.45200 120.28800 ;
      RECT 0.04800 120.96000 66.45200 121.05600 ;
      RECT 0.04800 121.72800 66.45200 121.82400 ;
      RECT 0.04800 122.49600 66.45200 122.59200 ;
      RECT 0.04800 123.26400 66.45200 123.36000 ;
      RECT 0.04800 124.03200 66.45200 124.12800 ;
      RECT 0.04800 124.80000 66.45200 124.89600 ;
      RECT 0.04800 125.56800 66.45200 125.66400 ;
      RECT 0.04800 126.33600 66.45200 126.43200 ;
      RECT 0.04800 127.10400 66.45200 127.20000 ;
      RECT 0.04800 127.87200 66.45200 127.96800 ;
      RECT 0.04800 128.64000 66.45200 128.73600 ;
      RECT 0.04800 129.40800 66.45200 129.50400 ;
      RECT 0.04800 130.17600 66.45200 130.27200 ;
      RECT 0.04800 130.94400 66.45200 131.04000 ;
      RECT 0.04800 131.71200 66.45200 131.80800 ;
      RECT 0.04800 132.48000 66.45200 132.57600 ;
      RECT 0.04800 133.24800 66.45200 133.34400 ;
      RECT 0.04800 134.01600 66.45200 134.11200 ;
      RECT 0.04800 134.78400 66.45200 134.88000 ;
      RECT 0.04800 135.55200 66.45200 135.64800 ;
      RECT 0.04800 136.32000 66.45200 136.41600 ;
      RECT 0.04800 137.08800 66.45200 137.18400 ;
      RECT 0.04800 137.85600 66.45200 137.95200 ;
      RECT 0.04800 138.62400 66.45200 138.72000 ;
      RECT 0.04800 139.39200 66.45200 139.48800 ;
      RECT 0.04800 140.16000 66.45200 140.25600 ;
      RECT 0.04800 140.92800 66.45200 141.02400 ;
      RECT 0.04800 141.69600 66.45200 141.79200 ;
      RECT 0.04800 142.46400 66.45200 142.56000 ;
      RECT 0.04800 143.23200 66.45200 143.32800 ;
      RECT 0.04800 144.00000 66.45200 144.09600 ;
      RECT 0.04800 144.76800 66.45200 144.86400 ;
      RECT 0.04800 145.53600 66.45200 145.63200 ;
      RECT 0.04800 146.30400 66.45200 146.40000 ;
      RECT 0.04800 147.07200 66.45200 147.16800 ;
      RECT 0.04800 147.84000 66.45200 147.93600 ;
      RECT 0.04800 148.60800 66.45200 148.70400 ;
      RECT 0.04800 149.37600 66.45200 149.47200 ;
      RECT 0.04800 150.14400 66.45200 150.24000 ;
      RECT 0.04800 150.91200 66.45200 151.00800 ;
      RECT 0.04800 151.68000 66.45200 151.77600 ;
      RECT 0.04800 152.44800 66.45200 152.54400 ;
      RECT 0.04800 153.21600 66.45200 153.31200 ;
      RECT 0.04800 153.98400 66.45200 154.08000 ;
      RECT 0.04800 154.75200 66.45200 154.84800 ;
      RECT 0.04800 155.52000 66.45200 155.61600 ;
      RECT 0.04800 156.28800 66.45200 156.38400 ;
      RECT 0.04800 157.05600 66.45200 157.15200 ;
      RECT 0.04800 157.82400 66.45200 157.92000 ;
      RECT 0.04800 158.59200 66.45200 158.68800 ;
      RECT 0.04800 159.36000 66.45200 159.45600 ;
      RECT 0.04800 160.12800 66.45200 160.22400 ;
      RECT 0.04800 160.89600 66.45200 160.99200 ;
      RECT 0.04800 161.66400 66.45200 161.76000 ;
      RECT 0.04800 162.43200 66.45200 162.52800 ;
      RECT 0.04800 163.20000 66.45200 163.29600 ;
      RECT 0.04800 163.96800 66.45200 164.06400 ;
      RECT 0.04800 164.73600 66.45200 164.83200 ;
      RECT 0.04800 165.50400 66.45200 165.60000 ;
      RECT 0.04800 166.27200 66.45200 166.36800 ;
      RECT 0.04800 167.04000 66.45200 167.13600 ;
      RECT 0.04800 167.80800 66.45200 167.90400 ;
      RECT 0.04800 168.57600 66.45200 168.67200 ;
      RECT 0.04800 169.34400 66.45200 169.44000 ;
      RECT 0.04800 170.11200 66.45200 170.20800 ;
      RECT 0.04800 170.88000 66.45200 170.97600 ;
      RECT 0.04800 171.64800 66.45200 171.74400 ;
      RECT 0.04800 172.41600 66.45200 172.51200 ;
      RECT 0.04800 173.18400 66.45200 173.28000 ;
      RECT 0.04800 173.95200 66.45200 174.04800 ;
      RECT 0.04800 174.72000 66.45200 174.81600 ;
      RECT 0.04800 175.48800 66.45200 175.58400 ;
      RECT 0.04800 176.25600 66.45200 176.35200 ;
      RECT 0.04800 177.02400 66.45200 177.12000 ;
      RECT 0.04800 177.79200 66.45200 177.88800 ;
      RECT 0.04800 178.56000 66.45200 178.65600 ;
      RECT 0.04800 179.32800 66.45200 179.42400 ;
      RECT 0.04800 180.09600 66.45200 180.19200 ;
      RECT 0.04800 180.86400 66.45200 180.96000 ;
      RECT 0.04800 181.63200 66.45200 181.72800 ;
      RECT 0.04800 182.40000 66.45200 182.49600 ;
      RECT 0.04800 183.16800 66.45200 183.26400 ;
      RECT 0.04800 183.93600 66.45200 184.03200 ;
      RECT 0.04800 184.70400 66.45200 184.80000 ;
      RECT 0.04800 185.47200 66.45200 185.56800 ;
      RECT 0.04800 186.24000 66.45200 186.33600 ;
      RECT 0.04800 187.00800 66.45200 187.10400 ;
      RECT 0.04800 187.77600 66.45200 187.87200 ;
      RECT 0.04800 188.54400 66.45200 188.64000 ;
      RECT 0.04800 189.31200 66.45200 189.40800 ;
      RECT 0.04800 190.08000 66.45200 190.17600 ;
      RECT 0.04800 190.84800 66.45200 190.94400 ;
      RECT 0.04800 191.61600 66.45200 191.71200 ;
      RECT 0.04800 192.38400 66.45200 192.48000 ;
      RECT 0.04800 193.15200 66.45200 193.24800 ;
      RECT 0.04800 193.92000 66.45200 194.01600 ;
      RECT 0.04800 194.68800 66.45200 194.78400 ;
      RECT 0.04800 195.45600 66.45200 195.55200 ;
      RECT 0.04800 196.22400 66.45200 196.32000 ;
      RECT 0.04800 196.99200 66.45200 197.08800 ;
      RECT 0.04800 197.76000 66.45200 197.85600 ;
      RECT 0.04800 198.52800 66.45200 198.62400 ;
      RECT 0.04800 199.29600 66.45200 199.39200 ;
      RECT 0.04800 200.06400 66.45200 200.16000 ;
      RECT 0.04800 200.83200 66.45200 200.92800 ;
      RECT 0.04800 201.60000 66.45200 201.69600 ;
      RECT 0.04800 202.36800 66.45200 202.46400 ;
      RECT 0.04800 203.13600 66.45200 203.23200 ;
      RECT 0.04800 203.90400 66.45200 204.00000 ;
      RECT 0.04800 204.67200 66.45200 204.76800 ;
      RECT 0.04800 205.44000 66.45200 205.53600 ;
      RECT 0.04800 206.20800 66.45200 206.30400 ;
      RECT 0.04800 206.97600 66.45200 207.07200 ;
      RECT 0.04800 207.74400 66.45200 207.84000 ;
      RECT 0.04800 208.51200 66.45200 208.60800 ;
      RECT 0.04800 209.28000 66.45200 209.37600 ;
      RECT 0.04800 210.04800 66.45200 210.14400 ;
      RECT 0.04800 210.81600 66.45200 210.91200 ;
      RECT 0.04800 211.58400 66.45200 211.68000 ;
      RECT 0.04800 212.35200 66.45200 212.44800 ;
      RECT 0.04800 213.12000 66.45200 213.21600 ;
      RECT 0.04800 213.88800 66.45200 213.98400 ;
      RECT 0.04800 214.65600 66.45200 214.75200 ;
      RECT 0.04800 215.42400 66.45200 215.52000 ;
      RECT 0.04800 216.19200 66.45200 216.28800 ;
      RECT 0.04800 216.96000 66.45200 217.05600 ;
      RECT 0.04800 217.72800 66.45200 217.82400 ;
      RECT 0.04800 218.49600 66.45200 218.59200 ;
      RECT 0.04800 219.26400 66.45200 219.36000 ;
      RECT 0.04800 220.03200 66.45200 220.12800 ;
      RECT 0.04800 220.80000 66.45200 220.89600 ;
      RECT 0.04800 221.56800 66.45200 221.66400 ;
      RECT 0.04800 222.33600 66.45200 222.43200 ;
      RECT 0.04800 223.10400 66.45200 223.20000 ;
      RECT 0.04800 223.87200 66.45200 223.96800 ;
      RECT 0.04800 224.64000 66.45200 224.73600 ;
      RECT 0.04800 225.40800 66.45200 225.50400 ;
      RECT 0.04800 226.17600 66.45200 226.27200 ;
      RECT 0.04800 226.94400 66.45200 227.04000 ;
      RECT 0.04800 227.71200 66.45200 227.80800 ;
      RECT 0.04800 228.48000 66.45200 228.57600 ;
      RECT 0.04800 229.24800 66.45200 229.34400 ;
      RECT 0.04800 230.01600 66.45200 230.11200 ;
      RECT 0.04800 230.78400 66.45200 230.88000 ;
      RECT 0.04800 231.55200 66.45200 231.64800 ;
      RECT 0.04800 232.32000 66.45200 232.41600 ;
      RECT 0.04800 233.08800 66.45200 233.18400 ;
      RECT 0.04800 233.85600 66.45200 233.95200 ;
      RECT 0.04800 234.62400 66.45200 234.72000 ;
      RECT 0.04800 235.39200 66.45200 235.48800 ;
      RECT 0.04800 236.16000 66.45200 236.25600 ;
      RECT 0.04800 236.92800 66.45200 237.02400 ;
      RECT 0.04800 237.69600 66.45200 237.79200 ;
      RECT 0.04800 238.46400 66.45200 238.56000 ;
      RECT 0.04800 239.23200 66.45200 239.32800 ;
      RECT 0.04800 240.00000 66.45200 240.09600 ;
      RECT 0.04800 240.76800 66.45200 240.86400 ;
      RECT 0.04800 241.53600 66.45200 241.63200 ;
      RECT 0.04800 242.30400 66.45200 242.40000 ;
      RECT 0.04800 243.07200 66.45200 243.16800 ;
      RECT 0.04800 243.84000 66.45200 243.93600 ;
      RECT 0.04800 244.60800 66.45200 244.70400 ;
      RECT 0.04800 245.37600 66.45200 245.47200 ;
      RECT 0.04800 246.14400 66.45200 246.24000 ;
      RECT 0.04800 246.91200 66.45200 247.00800 ;
      RECT 0.04800 247.68000 66.45200 247.77600 ;
      RECT 0.04800 248.44800 66.45200 248.54400 ;
      RECT 0.04800 249.21600 66.45200 249.31200 ;
      RECT 0.04800 249.98400 66.45200 250.08000 ;
      RECT 0.04800 250.75200 66.45200 250.84800 ;
      RECT 0.04800 251.52000 66.45200 251.61600 ;
      RECT 0.04800 252.28800 66.45200 252.38400 ;
      RECT 0.04800 253.05600 66.45200 253.15200 ;
      RECT 0.04800 253.82400 66.45200 253.92000 ;
      RECT 0.04800 254.59200 66.45200 254.68800 ;
      RECT 0.04800 255.36000 66.45200 255.45600 ;
      RECT 0.04800 256.12800 66.45200 256.22400 ;
      RECT 0.04800 256.89600 66.45200 256.99200 ;
      RECT 0.04800 257.66400 66.45200 257.76000 ;
      RECT 0.04800 258.43200 66.45200 258.52800 ;
      RECT 0.04800 259.20000 66.45200 259.29600 ;
      RECT 0.04800 259.96800 66.45200 260.06400 ;
      RECT 0.04800 260.73600 66.45200 260.83200 ;
      RECT 0.04800 261.50400 66.45200 261.60000 ;
      RECT 0.04800 262.27200 66.45200 262.36800 ;
      RECT 0.04800 263.04000 66.45200 263.13600 ;
      RECT 0.04800 263.80800 66.45200 263.90400 ;
      RECT 0.04800 264.57600 66.45200 264.67200 ;
      RECT 0.04800 265.34400 66.45200 265.44000 ;
      RECT 0.04800 266.11200 66.45200 266.20800 ;
      RECT 0.04800 266.88000 66.45200 266.97600 ;
      RECT 0.04800 267.64800 66.45200 267.74400 ;
      RECT 0.04800 268.41600 66.45200 268.51200 ;
      RECT 0.04800 269.18400 66.45200 269.28000 ;
      RECT 0.04800 269.95200 66.45200 270.04800 ;
      RECT 0.04800 270.72000 66.45200 270.81600 ;
      RECT 0.04800 271.48800 66.45200 271.58400 ;
      RECT 0.04800 272.25600 66.45200 272.35200 ;
      RECT 0.04800 273.02400 66.45200 273.12000 ;
      RECT 0.04800 273.79200 66.45200 273.88800 ;
      RECT 0.04800 274.56000 66.45200 274.65600 ;
      RECT 0.04800 275.32800 66.45200 275.42400 ;
      RECT 0.04800 276.09600 66.45200 276.19200 ;
      RECT 0.04800 276.86400 66.45200 276.96000 ;
      RECT 0.04800 277.63200 66.45200 277.72800 ;
      RECT 0.04800 278.40000 66.45200 278.49600 ;
      RECT 0.04800 279.16800 66.45200 279.26400 ;
      RECT 0.04800 279.93600 66.45200 280.03200 ;
      RECT 0.04800 280.70400 66.45200 280.80000 ;
      RECT 0.04800 281.47200 66.45200 281.56800 ;
      RECT 0.04800 282.24000 66.45200 282.33600 ;
      RECT 0.04800 283.00800 66.45200 283.10400 ;
      RECT 0.04800 283.77600 66.45200 283.87200 ;
      RECT 0.04800 284.54400 66.45200 284.64000 ;
      RECT 0.04800 285.31200 66.45200 285.40800 ;
      RECT 0.04800 286.08000 66.45200 286.17600 ;
      RECT 0.04800 286.84800 66.45200 286.94400 ;
      RECT 0.04800 287.61600 66.45200 287.71200 ;
      RECT 0.04800 288.38400 66.45200 288.48000 ;
      RECT 0.04800 289.15200 66.45200 289.24800 ;
      RECT 0.04800 289.92000 66.45200 290.01600 ;
      RECT 0.04800 290.68800 66.45200 290.78400 ;
      RECT 0.04800 291.45600 66.45200 291.55200 ;
      RECT 0.04800 292.22400 66.45200 292.32000 ;
      RECT 0.04800 292.99200 66.45200 293.08800 ;
      RECT 0.04800 293.76000 66.45200 293.85600 ;
      RECT 0.04800 294.52800 66.45200 294.62400 ;
      RECT 0.04800 295.29600 66.45200 295.39200 ;
      RECT 0.04800 296.06400 66.45200 296.16000 ;
      RECT 0.04800 296.83200 66.45200 296.92800 ;
      RECT 0.04800 297.60000 66.45200 297.69600 ;
      RECT 0.04800 298.36800 66.45200 298.46400 ;
      RECT 0.04800 299.13600 66.45200 299.23200 ;
      RECT 0.04800 299.90400 66.45200 300.00000 ;
      RECT 0.04800 300.67200 66.45200 300.76800 ;
      RECT 0.04800 301.44000 66.45200 301.53600 ;
      RECT 0.04800 302.20800 66.45200 302.30400 ;
      RECT 0.04800 302.97600 66.45200 303.07200 ;
      RECT 0.04800 303.74400 66.45200 303.84000 ;
      RECT 0.04800 304.51200 66.45200 304.60800 ;
      RECT 0.04800 305.28000 66.45200 305.37600 ;
      RECT 0.04800 306.04800 66.45200 306.14400 ;
      RECT 0.04800 306.81600 66.45200 306.91200 ;
      RECT 0.04800 307.58400 66.45200 307.68000 ;
      RECT 0.04800 308.35200 66.45200 308.44800 ;
      RECT 0.04800 309.12000 66.45200 309.21600 ;
      RECT 0.04800 309.88800 66.45200 309.98400 ;
      RECT 0.04800 310.65600 66.45200 310.75200 ;
      RECT 0.04800 311.42400 66.45200 311.52000 ;
      RECT 0.04800 312.19200 66.45200 312.28800 ;
      RECT 0.04800 312.96000 66.45200 313.05600 ;
      RECT 0.04800 313.72800 66.45200 313.82400 ;
      RECT 0.04800 314.49600 66.45200 314.59200 ;
      RECT 0.04800 315.26400 66.45200 315.36000 ;
      RECT 0.04800 316.03200 66.45200 316.12800 ;
      RECT 0.04800 316.80000 66.45200 316.89600 ;
      RECT 0.04800 317.56800 66.45200 317.66400 ;
      RECT 0.04800 318.33600 66.45200 318.43200 ;
      RECT 0.04800 319.10400 66.45200 319.20000 ;
      RECT 0.04800 319.87200 66.45200 319.96800 ;
      RECT 0.04800 320.64000 66.45200 320.73600 ;
      RECT 0.04800 321.40800 66.45200 321.50400 ;
      RECT 0.04800 322.17600 66.45200 322.27200 ;
      RECT 0.04800 322.94400 66.45200 323.04000 ;
      RECT 0.04800 323.71200 66.45200 323.80800 ;
      RECT 0.04800 324.48000 66.45200 324.57600 ;
      RECT 0.04800 325.24800 66.45200 325.34400 ;
      RECT 0.04800 326.01600 66.45200 326.11200 ;
      RECT 0.04800 326.78400 66.45200 326.88000 ;
      RECT 0.04800 327.55200 66.45200 327.64800 ;
      RECT 0.04800 328.32000 66.45200 328.41600 ;
      RECT 0.04800 329.08800 66.45200 329.18400 ;
      RECT 0.04800 329.85600 66.45200 329.95200 ;
      RECT 0.04800 330.62400 66.45200 330.72000 ;
      RECT 0.04800 331.39200 66.45200 331.48800 ;
    END
  END VDD
  PIN VSS
    DIRECTION INOUT ;
    USE GROUND ;
    PORT
      LAYER M4 ;
      RECT 0.04800 0.00000 66.45200 0.09600 ;
      RECT 0.04800 0.76800 66.45200 0.86400 ;
      RECT 0.04800 1.53600 66.45200 1.63200 ;
      RECT 0.04800 2.30400 66.45200 2.40000 ;
      RECT 0.04800 3.07200 66.45200 3.16800 ;
      RECT 0.04800 3.84000 66.45200 3.93600 ;
      RECT 0.04800 4.60800 66.45200 4.70400 ;
      RECT 0.04800 5.37600 66.45200 5.47200 ;
      RECT 0.04800 6.14400 66.45200 6.24000 ;
      RECT 0.04800 6.91200 66.45200 7.00800 ;
      RECT 0.04800 7.68000 66.45200 7.77600 ;
      RECT 0.04800 8.44800 66.45200 8.54400 ;
      RECT 0.04800 9.21600 66.45200 9.31200 ;
      RECT 0.04800 9.98400 66.45200 10.08000 ;
      RECT 0.04800 10.75200 66.45200 10.84800 ;
      RECT 0.04800 11.52000 66.45200 11.61600 ;
      RECT 0.04800 12.28800 66.45200 12.38400 ;
      RECT 0.04800 13.05600 66.45200 13.15200 ;
      RECT 0.04800 13.82400 66.45200 13.92000 ;
      RECT 0.04800 14.59200 66.45200 14.68800 ;
      RECT 0.04800 15.36000 66.45200 15.45600 ;
      RECT 0.04800 16.12800 66.45200 16.22400 ;
      RECT 0.04800 16.89600 66.45200 16.99200 ;
      RECT 0.04800 17.66400 66.45200 17.76000 ;
      RECT 0.04800 18.43200 66.45200 18.52800 ;
      RECT 0.04800 19.20000 66.45200 19.29600 ;
      RECT 0.04800 19.96800 66.45200 20.06400 ;
      RECT 0.04800 20.73600 66.45200 20.83200 ;
      RECT 0.04800 21.50400 66.45200 21.60000 ;
      RECT 0.04800 22.27200 66.45200 22.36800 ;
      RECT 0.04800 23.04000 66.45200 23.13600 ;
      RECT 0.04800 23.80800 66.45200 23.90400 ;
      RECT 0.04800 24.57600 66.45200 24.67200 ;
      RECT 0.04800 25.34400 66.45200 25.44000 ;
      RECT 0.04800 26.11200 66.45200 26.20800 ;
      RECT 0.04800 26.88000 66.45200 26.97600 ;
      RECT 0.04800 27.64800 66.45200 27.74400 ;
      RECT 0.04800 28.41600 66.45200 28.51200 ;
      RECT 0.04800 29.18400 66.45200 29.28000 ;
      RECT 0.04800 29.95200 66.45200 30.04800 ;
      RECT 0.04800 30.72000 66.45200 30.81600 ;
      RECT 0.04800 31.48800 66.45200 31.58400 ;
      RECT 0.04800 32.25600 66.45200 32.35200 ;
      RECT 0.04800 33.02400 66.45200 33.12000 ;
      RECT 0.04800 33.79200 66.45200 33.88800 ;
      RECT 0.04800 34.56000 66.45200 34.65600 ;
      RECT 0.04800 35.32800 66.45200 35.42400 ;
      RECT 0.04800 36.09600 66.45200 36.19200 ;
      RECT 0.04800 36.86400 66.45200 36.96000 ;
      RECT 0.04800 37.63200 66.45200 37.72800 ;
      RECT 0.04800 38.40000 66.45200 38.49600 ;
      RECT 0.04800 39.16800 66.45200 39.26400 ;
      RECT 0.04800 39.93600 66.45200 40.03200 ;
      RECT 0.04800 40.70400 66.45200 40.80000 ;
      RECT 0.04800 41.47200 66.45200 41.56800 ;
      RECT 0.04800 42.24000 66.45200 42.33600 ;
      RECT 0.04800 43.00800 66.45200 43.10400 ;
      RECT 0.04800 43.77600 66.45200 43.87200 ;
      RECT 0.04800 44.54400 66.45200 44.64000 ;
      RECT 0.04800 45.31200 66.45200 45.40800 ;
      RECT 0.04800 46.08000 66.45200 46.17600 ;
      RECT 0.04800 46.84800 66.45200 46.94400 ;
      RECT 0.04800 47.61600 66.45200 47.71200 ;
      RECT 0.04800 48.38400 66.45200 48.48000 ;
      RECT 0.04800 49.15200 66.45200 49.24800 ;
      RECT 0.04800 49.92000 66.45200 50.01600 ;
      RECT 0.04800 50.68800 66.45200 50.78400 ;
      RECT 0.04800 51.45600 66.45200 51.55200 ;
      RECT 0.04800 52.22400 66.45200 52.32000 ;
      RECT 0.04800 52.99200 66.45200 53.08800 ;
      RECT 0.04800 53.76000 66.45200 53.85600 ;
      RECT 0.04800 54.52800 66.45200 54.62400 ;
      RECT 0.04800 55.29600 66.45200 55.39200 ;
      RECT 0.04800 56.06400 66.45200 56.16000 ;
      RECT 0.04800 56.83200 66.45200 56.92800 ;
      RECT 0.04800 57.60000 66.45200 57.69600 ;
      RECT 0.04800 58.36800 66.45200 58.46400 ;
      RECT 0.04800 59.13600 66.45200 59.23200 ;
      RECT 0.04800 59.90400 66.45200 60.00000 ;
      RECT 0.04800 60.67200 66.45200 60.76800 ;
      RECT 0.04800 61.44000 66.45200 61.53600 ;
      RECT 0.04800 62.20800 66.45200 62.30400 ;
      RECT 0.04800 62.97600 66.45200 63.07200 ;
      RECT 0.04800 63.74400 66.45200 63.84000 ;
      RECT 0.04800 64.51200 66.45200 64.60800 ;
      RECT 0.04800 65.28000 66.45200 65.37600 ;
      RECT 0.04800 66.04800 66.45200 66.14400 ;
      RECT 0.04800 66.81600 66.45200 66.91200 ;
      RECT 0.04800 67.58400 66.45200 67.68000 ;
      RECT 0.04800 68.35200 66.45200 68.44800 ;
      RECT 0.04800 69.12000 66.45200 69.21600 ;
      RECT 0.04800 69.88800 66.45200 69.98400 ;
      RECT 0.04800 70.65600 66.45200 70.75200 ;
      RECT 0.04800 71.42400 66.45200 71.52000 ;
      RECT 0.04800 72.19200 66.45200 72.28800 ;
      RECT 0.04800 72.96000 66.45200 73.05600 ;
      RECT 0.04800 73.72800 66.45200 73.82400 ;
      RECT 0.04800 74.49600 66.45200 74.59200 ;
      RECT 0.04800 75.26400 66.45200 75.36000 ;
      RECT 0.04800 76.03200 66.45200 76.12800 ;
      RECT 0.04800 76.80000 66.45200 76.89600 ;
      RECT 0.04800 77.56800 66.45200 77.66400 ;
      RECT 0.04800 78.33600 66.45200 78.43200 ;
      RECT 0.04800 79.10400 66.45200 79.20000 ;
      RECT 0.04800 79.87200 66.45200 79.96800 ;
      RECT 0.04800 80.64000 66.45200 80.73600 ;
      RECT 0.04800 81.40800 66.45200 81.50400 ;
      RECT 0.04800 82.17600 66.45200 82.27200 ;
      RECT 0.04800 82.94400 66.45200 83.04000 ;
      RECT 0.04800 83.71200 66.45200 83.80800 ;
      RECT 0.04800 84.48000 66.45200 84.57600 ;
      RECT 0.04800 85.24800 66.45200 85.34400 ;
      RECT 0.04800 86.01600 66.45200 86.11200 ;
      RECT 0.04800 86.78400 66.45200 86.88000 ;
      RECT 0.04800 87.55200 66.45200 87.64800 ;
      RECT 0.04800 88.32000 66.45200 88.41600 ;
      RECT 0.04800 89.08800 66.45200 89.18400 ;
      RECT 0.04800 89.85600 66.45200 89.95200 ;
      RECT 0.04800 90.62400 66.45200 90.72000 ;
      RECT 0.04800 91.39200 66.45200 91.48800 ;
      RECT 0.04800 92.16000 66.45200 92.25600 ;
      RECT 0.04800 92.92800 66.45200 93.02400 ;
      RECT 0.04800 93.69600 66.45200 93.79200 ;
      RECT 0.04800 94.46400 66.45200 94.56000 ;
      RECT 0.04800 95.23200 66.45200 95.32800 ;
      RECT 0.04800 96.00000 66.45200 96.09600 ;
      RECT 0.04800 96.76800 66.45200 96.86400 ;
      RECT 0.04800 97.53600 66.45200 97.63200 ;
      RECT 0.04800 98.30400 66.45200 98.40000 ;
      RECT 0.04800 99.07200 66.45200 99.16800 ;
      RECT 0.04800 99.84000 66.45200 99.93600 ;
      RECT 0.04800 100.60800 66.45200 100.70400 ;
      RECT 0.04800 101.37600 66.45200 101.47200 ;
      RECT 0.04800 102.14400 66.45200 102.24000 ;
      RECT 0.04800 102.91200 66.45200 103.00800 ;
      RECT 0.04800 103.68000 66.45200 103.77600 ;
      RECT 0.04800 104.44800 66.45200 104.54400 ;
      RECT 0.04800 105.21600 66.45200 105.31200 ;
      RECT 0.04800 105.98400 66.45200 106.08000 ;
      RECT 0.04800 106.75200 66.45200 106.84800 ;
      RECT 0.04800 107.52000 66.45200 107.61600 ;
      RECT 0.04800 108.28800 66.45200 108.38400 ;
      RECT 0.04800 109.05600 66.45200 109.15200 ;
      RECT 0.04800 109.82400 66.45200 109.92000 ;
      RECT 0.04800 110.59200 66.45200 110.68800 ;
      RECT 0.04800 111.36000 66.45200 111.45600 ;
      RECT 0.04800 112.12800 66.45200 112.22400 ;
      RECT 0.04800 112.89600 66.45200 112.99200 ;
      RECT 0.04800 113.66400 66.45200 113.76000 ;
      RECT 0.04800 114.43200 66.45200 114.52800 ;
      RECT 0.04800 115.20000 66.45200 115.29600 ;
      RECT 0.04800 115.96800 66.45200 116.06400 ;
      RECT 0.04800 116.73600 66.45200 116.83200 ;
      RECT 0.04800 117.50400 66.45200 117.60000 ;
      RECT 0.04800 118.27200 66.45200 118.36800 ;
      RECT 0.04800 119.04000 66.45200 119.13600 ;
      RECT 0.04800 119.80800 66.45200 119.90400 ;
      RECT 0.04800 120.57600 66.45200 120.67200 ;
      RECT 0.04800 121.34400 66.45200 121.44000 ;
      RECT 0.04800 122.11200 66.45200 122.20800 ;
      RECT 0.04800 122.88000 66.45200 122.97600 ;
      RECT 0.04800 123.64800 66.45200 123.74400 ;
      RECT 0.04800 124.41600 66.45200 124.51200 ;
      RECT 0.04800 125.18400 66.45200 125.28000 ;
      RECT 0.04800 125.95200 66.45200 126.04800 ;
      RECT 0.04800 126.72000 66.45200 126.81600 ;
      RECT 0.04800 127.48800 66.45200 127.58400 ;
      RECT 0.04800 128.25600 66.45200 128.35200 ;
      RECT 0.04800 129.02400 66.45200 129.12000 ;
      RECT 0.04800 129.79200 66.45200 129.88800 ;
      RECT 0.04800 130.56000 66.45200 130.65600 ;
      RECT 0.04800 131.32800 66.45200 131.42400 ;
      RECT 0.04800 132.09600 66.45200 132.19200 ;
      RECT 0.04800 132.86400 66.45200 132.96000 ;
      RECT 0.04800 133.63200 66.45200 133.72800 ;
      RECT 0.04800 134.40000 66.45200 134.49600 ;
      RECT 0.04800 135.16800 66.45200 135.26400 ;
      RECT 0.04800 135.93600 66.45200 136.03200 ;
      RECT 0.04800 136.70400 66.45200 136.80000 ;
      RECT 0.04800 137.47200 66.45200 137.56800 ;
      RECT 0.04800 138.24000 66.45200 138.33600 ;
      RECT 0.04800 139.00800 66.45200 139.10400 ;
      RECT 0.04800 139.77600 66.45200 139.87200 ;
      RECT 0.04800 140.54400 66.45200 140.64000 ;
      RECT 0.04800 141.31200 66.45200 141.40800 ;
      RECT 0.04800 142.08000 66.45200 142.17600 ;
      RECT 0.04800 142.84800 66.45200 142.94400 ;
      RECT 0.04800 143.61600 66.45200 143.71200 ;
      RECT 0.04800 144.38400 66.45200 144.48000 ;
      RECT 0.04800 145.15200 66.45200 145.24800 ;
      RECT 0.04800 145.92000 66.45200 146.01600 ;
      RECT 0.04800 146.68800 66.45200 146.78400 ;
      RECT 0.04800 147.45600 66.45200 147.55200 ;
      RECT 0.04800 148.22400 66.45200 148.32000 ;
      RECT 0.04800 148.99200 66.45200 149.08800 ;
      RECT 0.04800 149.76000 66.45200 149.85600 ;
      RECT 0.04800 150.52800 66.45200 150.62400 ;
      RECT 0.04800 151.29600 66.45200 151.39200 ;
      RECT 0.04800 152.06400 66.45200 152.16000 ;
      RECT 0.04800 152.83200 66.45200 152.92800 ;
      RECT 0.04800 153.60000 66.45200 153.69600 ;
      RECT 0.04800 154.36800 66.45200 154.46400 ;
      RECT 0.04800 155.13600 66.45200 155.23200 ;
      RECT 0.04800 155.90400 66.45200 156.00000 ;
      RECT 0.04800 156.67200 66.45200 156.76800 ;
      RECT 0.04800 157.44000 66.45200 157.53600 ;
      RECT 0.04800 158.20800 66.45200 158.30400 ;
      RECT 0.04800 158.97600 66.45200 159.07200 ;
      RECT 0.04800 159.74400 66.45200 159.84000 ;
      RECT 0.04800 160.51200 66.45200 160.60800 ;
      RECT 0.04800 161.28000 66.45200 161.37600 ;
      RECT 0.04800 162.04800 66.45200 162.14400 ;
      RECT 0.04800 162.81600 66.45200 162.91200 ;
      RECT 0.04800 163.58400 66.45200 163.68000 ;
      RECT 0.04800 164.35200 66.45200 164.44800 ;
      RECT 0.04800 165.12000 66.45200 165.21600 ;
      RECT 0.04800 165.88800 66.45200 165.98400 ;
      RECT 0.04800 166.65600 66.45200 166.75200 ;
      RECT 0.04800 167.42400 66.45200 167.52000 ;
      RECT 0.04800 168.19200 66.45200 168.28800 ;
      RECT 0.04800 168.96000 66.45200 169.05600 ;
      RECT 0.04800 169.72800 66.45200 169.82400 ;
      RECT 0.04800 170.49600 66.45200 170.59200 ;
      RECT 0.04800 171.26400 66.45200 171.36000 ;
      RECT 0.04800 172.03200 66.45200 172.12800 ;
      RECT 0.04800 172.80000 66.45200 172.89600 ;
      RECT 0.04800 173.56800 66.45200 173.66400 ;
      RECT 0.04800 174.33600 66.45200 174.43200 ;
      RECT 0.04800 175.10400 66.45200 175.20000 ;
      RECT 0.04800 175.87200 66.45200 175.96800 ;
      RECT 0.04800 176.64000 66.45200 176.73600 ;
      RECT 0.04800 177.40800 66.45200 177.50400 ;
      RECT 0.04800 178.17600 66.45200 178.27200 ;
      RECT 0.04800 178.94400 66.45200 179.04000 ;
      RECT 0.04800 179.71200 66.45200 179.80800 ;
      RECT 0.04800 180.48000 66.45200 180.57600 ;
      RECT 0.04800 181.24800 66.45200 181.34400 ;
      RECT 0.04800 182.01600 66.45200 182.11200 ;
      RECT 0.04800 182.78400 66.45200 182.88000 ;
      RECT 0.04800 183.55200 66.45200 183.64800 ;
      RECT 0.04800 184.32000 66.45200 184.41600 ;
      RECT 0.04800 185.08800 66.45200 185.18400 ;
      RECT 0.04800 185.85600 66.45200 185.95200 ;
      RECT 0.04800 186.62400 66.45200 186.72000 ;
      RECT 0.04800 187.39200 66.45200 187.48800 ;
      RECT 0.04800 188.16000 66.45200 188.25600 ;
      RECT 0.04800 188.92800 66.45200 189.02400 ;
      RECT 0.04800 189.69600 66.45200 189.79200 ;
      RECT 0.04800 190.46400 66.45200 190.56000 ;
      RECT 0.04800 191.23200 66.45200 191.32800 ;
      RECT 0.04800 192.00000 66.45200 192.09600 ;
      RECT 0.04800 192.76800 66.45200 192.86400 ;
      RECT 0.04800 193.53600 66.45200 193.63200 ;
      RECT 0.04800 194.30400 66.45200 194.40000 ;
      RECT 0.04800 195.07200 66.45200 195.16800 ;
      RECT 0.04800 195.84000 66.45200 195.93600 ;
      RECT 0.04800 196.60800 66.45200 196.70400 ;
      RECT 0.04800 197.37600 66.45200 197.47200 ;
      RECT 0.04800 198.14400 66.45200 198.24000 ;
      RECT 0.04800 198.91200 66.45200 199.00800 ;
      RECT 0.04800 199.68000 66.45200 199.77600 ;
      RECT 0.04800 200.44800 66.45200 200.54400 ;
      RECT 0.04800 201.21600 66.45200 201.31200 ;
      RECT 0.04800 201.98400 66.45200 202.08000 ;
      RECT 0.04800 202.75200 66.45200 202.84800 ;
      RECT 0.04800 203.52000 66.45200 203.61600 ;
      RECT 0.04800 204.28800 66.45200 204.38400 ;
      RECT 0.04800 205.05600 66.45200 205.15200 ;
      RECT 0.04800 205.82400 66.45200 205.92000 ;
      RECT 0.04800 206.59200 66.45200 206.68800 ;
      RECT 0.04800 207.36000 66.45200 207.45600 ;
      RECT 0.04800 208.12800 66.45200 208.22400 ;
      RECT 0.04800 208.89600 66.45200 208.99200 ;
      RECT 0.04800 209.66400 66.45200 209.76000 ;
      RECT 0.04800 210.43200 66.45200 210.52800 ;
      RECT 0.04800 211.20000 66.45200 211.29600 ;
      RECT 0.04800 211.96800 66.45200 212.06400 ;
      RECT 0.04800 212.73600 66.45200 212.83200 ;
      RECT 0.04800 213.50400 66.45200 213.60000 ;
      RECT 0.04800 214.27200 66.45200 214.36800 ;
      RECT 0.04800 215.04000 66.45200 215.13600 ;
      RECT 0.04800 215.80800 66.45200 215.90400 ;
      RECT 0.04800 216.57600 66.45200 216.67200 ;
      RECT 0.04800 217.34400 66.45200 217.44000 ;
      RECT 0.04800 218.11200 66.45200 218.20800 ;
      RECT 0.04800 218.88000 66.45200 218.97600 ;
      RECT 0.04800 219.64800 66.45200 219.74400 ;
      RECT 0.04800 220.41600 66.45200 220.51200 ;
      RECT 0.04800 221.18400 66.45200 221.28000 ;
      RECT 0.04800 221.95200 66.45200 222.04800 ;
      RECT 0.04800 222.72000 66.45200 222.81600 ;
      RECT 0.04800 223.48800 66.45200 223.58400 ;
      RECT 0.04800 224.25600 66.45200 224.35200 ;
      RECT 0.04800 225.02400 66.45200 225.12000 ;
      RECT 0.04800 225.79200 66.45200 225.88800 ;
      RECT 0.04800 226.56000 66.45200 226.65600 ;
      RECT 0.04800 227.32800 66.45200 227.42400 ;
      RECT 0.04800 228.09600 66.45200 228.19200 ;
      RECT 0.04800 228.86400 66.45200 228.96000 ;
      RECT 0.04800 229.63200 66.45200 229.72800 ;
      RECT 0.04800 230.40000 66.45200 230.49600 ;
      RECT 0.04800 231.16800 66.45200 231.26400 ;
      RECT 0.04800 231.93600 66.45200 232.03200 ;
      RECT 0.04800 232.70400 66.45200 232.80000 ;
      RECT 0.04800 233.47200 66.45200 233.56800 ;
      RECT 0.04800 234.24000 66.45200 234.33600 ;
      RECT 0.04800 235.00800 66.45200 235.10400 ;
      RECT 0.04800 235.77600 66.45200 235.87200 ;
      RECT 0.04800 236.54400 66.45200 236.64000 ;
      RECT 0.04800 237.31200 66.45200 237.40800 ;
      RECT 0.04800 238.08000 66.45200 238.17600 ;
      RECT 0.04800 238.84800 66.45200 238.94400 ;
      RECT 0.04800 239.61600 66.45200 239.71200 ;
      RECT 0.04800 240.38400 66.45200 240.48000 ;
      RECT 0.04800 241.15200 66.45200 241.24800 ;
      RECT 0.04800 241.92000 66.45200 242.01600 ;
      RECT 0.04800 242.68800 66.45200 242.78400 ;
      RECT 0.04800 243.45600 66.45200 243.55200 ;
      RECT 0.04800 244.22400 66.45200 244.32000 ;
      RECT 0.04800 244.99200 66.45200 245.08800 ;
      RECT 0.04800 245.76000 66.45200 245.85600 ;
      RECT 0.04800 246.52800 66.45200 246.62400 ;
      RECT 0.04800 247.29600 66.45200 247.39200 ;
      RECT 0.04800 248.06400 66.45200 248.16000 ;
      RECT 0.04800 248.83200 66.45200 248.92800 ;
      RECT 0.04800 249.60000 66.45200 249.69600 ;
      RECT 0.04800 250.36800 66.45200 250.46400 ;
      RECT 0.04800 251.13600 66.45200 251.23200 ;
      RECT 0.04800 251.90400 66.45200 252.00000 ;
      RECT 0.04800 252.67200 66.45200 252.76800 ;
      RECT 0.04800 253.44000 66.45200 253.53600 ;
      RECT 0.04800 254.20800 66.45200 254.30400 ;
      RECT 0.04800 254.97600 66.45200 255.07200 ;
      RECT 0.04800 255.74400 66.45200 255.84000 ;
      RECT 0.04800 256.51200 66.45200 256.60800 ;
      RECT 0.04800 257.28000 66.45200 257.37600 ;
      RECT 0.04800 258.04800 66.45200 258.14400 ;
      RECT 0.04800 258.81600 66.45200 258.91200 ;
      RECT 0.04800 259.58400 66.45200 259.68000 ;
      RECT 0.04800 260.35200 66.45200 260.44800 ;
      RECT 0.04800 261.12000 66.45200 261.21600 ;
      RECT 0.04800 261.88800 66.45200 261.98400 ;
      RECT 0.04800 262.65600 66.45200 262.75200 ;
      RECT 0.04800 263.42400 66.45200 263.52000 ;
      RECT 0.04800 264.19200 66.45200 264.28800 ;
      RECT 0.04800 264.96000 66.45200 265.05600 ;
      RECT 0.04800 265.72800 66.45200 265.82400 ;
      RECT 0.04800 266.49600 66.45200 266.59200 ;
      RECT 0.04800 267.26400 66.45200 267.36000 ;
      RECT 0.04800 268.03200 66.45200 268.12800 ;
      RECT 0.04800 268.80000 66.45200 268.89600 ;
      RECT 0.04800 269.56800 66.45200 269.66400 ;
      RECT 0.04800 270.33600 66.45200 270.43200 ;
      RECT 0.04800 271.10400 66.45200 271.20000 ;
      RECT 0.04800 271.87200 66.45200 271.96800 ;
      RECT 0.04800 272.64000 66.45200 272.73600 ;
      RECT 0.04800 273.40800 66.45200 273.50400 ;
      RECT 0.04800 274.17600 66.45200 274.27200 ;
      RECT 0.04800 274.94400 66.45200 275.04000 ;
      RECT 0.04800 275.71200 66.45200 275.80800 ;
      RECT 0.04800 276.48000 66.45200 276.57600 ;
      RECT 0.04800 277.24800 66.45200 277.34400 ;
      RECT 0.04800 278.01600 66.45200 278.11200 ;
      RECT 0.04800 278.78400 66.45200 278.88000 ;
      RECT 0.04800 279.55200 66.45200 279.64800 ;
      RECT 0.04800 280.32000 66.45200 280.41600 ;
      RECT 0.04800 281.08800 66.45200 281.18400 ;
      RECT 0.04800 281.85600 66.45200 281.95200 ;
      RECT 0.04800 282.62400 66.45200 282.72000 ;
      RECT 0.04800 283.39200 66.45200 283.48800 ;
      RECT 0.04800 284.16000 66.45200 284.25600 ;
      RECT 0.04800 284.92800 66.45200 285.02400 ;
      RECT 0.04800 285.69600 66.45200 285.79200 ;
      RECT 0.04800 286.46400 66.45200 286.56000 ;
      RECT 0.04800 287.23200 66.45200 287.32800 ;
      RECT 0.04800 288.00000 66.45200 288.09600 ;
      RECT 0.04800 288.76800 66.45200 288.86400 ;
      RECT 0.04800 289.53600 66.45200 289.63200 ;
      RECT 0.04800 290.30400 66.45200 290.40000 ;
      RECT 0.04800 291.07200 66.45200 291.16800 ;
      RECT 0.04800 291.84000 66.45200 291.93600 ;
      RECT 0.04800 292.60800 66.45200 292.70400 ;
      RECT 0.04800 293.37600 66.45200 293.47200 ;
      RECT 0.04800 294.14400 66.45200 294.24000 ;
      RECT 0.04800 294.91200 66.45200 295.00800 ;
      RECT 0.04800 295.68000 66.45200 295.77600 ;
      RECT 0.04800 296.44800 66.45200 296.54400 ;
      RECT 0.04800 297.21600 66.45200 297.31200 ;
      RECT 0.04800 297.98400 66.45200 298.08000 ;
      RECT 0.04800 298.75200 66.45200 298.84800 ;
      RECT 0.04800 299.52000 66.45200 299.61600 ;
      RECT 0.04800 300.28800 66.45200 300.38400 ;
      RECT 0.04800 301.05600 66.45200 301.15200 ;
      RECT 0.04800 301.82400 66.45200 301.92000 ;
      RECT 0.04800 302.59200 66.45200 302.68800 ;
      RECT 0.04800 303.36000 66.45200 303.45600 ;
      RECT 0.04800 304.12800 66.45200 304.22400 ;
      RECT 0.04800 304.89600 66.45200 304.99200 ;
      RECT 0.04800 305.66400 66.45200 305.76000 ;
      RECT 0.04800 306.43200 66.45200 306.52800 ;
      RECT 0.04800 307.20000 66.45200 307.29600 ;
      RECT 0.04800 307.96800 66.45200 308.06400 ;
      RECT 0.04800 308.73600 66.45200 308.83200 ;
      RECT 0.04800 309.50400 66.45200 309.60000 ;
      RECT 0.04800 310.27200 66.45200 310.36800 ;
      RECT 0.04800 311.04000 66.45200 311.13600 ;
      RECT 0.04800 311.80800 66.45200 311.90400 ;
      RECT 0.04800 312.57600 66.45200 312.67200 ;
      RECT 0.04800 313.34400 66.45200 313.44000 ;
      RECT 0.04800 314.11200 66.45200 314.20800 ;
      RECT 0.04800 314.88000 66.45200 314.97600 ;
      RECT 0.04800 315.64800 66.45200 315.74400 ;
      RECT 0.04800 316.41600 66.45200 316.51200 ;
      RECT 0.04800 317.18400 66.45200 317.28000 ;
      RECT 0.04800 317.95200 66.45200 318.04800 ;
      RECT 0.04800 318.72000 66.45200 318.81600 ;
      RECT 0.04800 319.48800 66.45200 319.58400 ;
      RECT 0.04800 320.25600 66.45200 320.35200 ;
      RECT 0.04800 321.02400 66.45200 321.12000 ;
      RECT 0.04800 321.79200 66.45200 321.88800 ;
      RECT 0.04800 322.56000 66.45200 322.65600 ;
      RECT 0.04800 323.32800 66.45200 323.42400 ;
      RECT 0.04800 324.09600 66.45200 324.19200 ;
      RECT 0.04800 324.86400 66.45200 324.96000 ;
      RECT 0.04800 325.63200 66.45200 325.72800 ;
      RECT 0.04800 326.40000 66.45200 326.49600 ;
      RECT 0.04800 327.16800 66.45200 327.26400 ;
      RECT 0.04800 327.93600 66.45200 328.03200 ;
      RECT 0.04800 328.70400 66.45200 328.80000 ;
      RECT 0.04800 329.47200 66.45200 329.56800 ;
      RECT 0.04800 330.24000 66.45200 330.33600 ;
      RECT 0.04800 331.00800 66.45200 331.10400 ;
    END
  END VSS
  OBS
    LAYER M1 ;
    RECT 0 0 66.50000 331.80000 ;
    LAYER M2 ;
    RECT 0 0 66.50000 331.80000 ;
    LAYER M3 ;
    RECT 0 0 66.50000 331.80000 ;
    LAYER M4 ;
    RECT 0 0 66.50000 331.80000 ;
  END
END fakeram7_1024x512_g2_1w1r

END LIBRARY
